VERSION 5.8 ;
BUSBITCHARS "[]" ;
DIVIDERCHAR "/" ;
UNITS
    DATABASE MICRONS 1000 ;
END UNITS

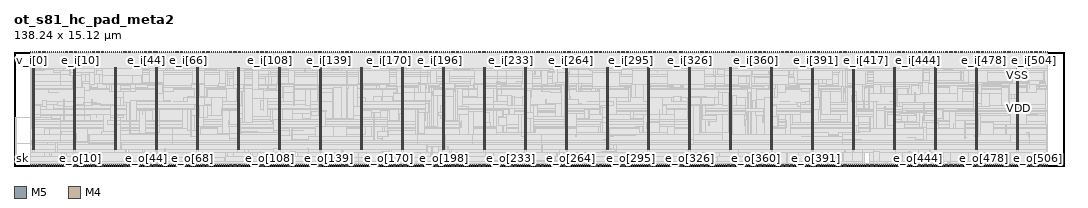
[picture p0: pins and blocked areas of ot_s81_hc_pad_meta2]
MACRO ot_s81_hc_pad_meta2
  FOREIGN ot_s81_hc_pad_meta2 0 0 ;
  CLASS BLOCK ;
  SIZE 138.24 BY 15.12 ;
  PIN e_i[0]
    DIRECTION INPUT ;
    USE SIGNAL ;
    PORT
      LAYER M5 ;
        RECT  6.192 14.928 6.216 15.12 ;
    END
  END e_i[0]
  PIN e_i[100]
    DIRECTION INPUT ;
    USE SIGNAL ;
    PORT
      LAYER M5 ;
        RECT  31.632 14.928 31.656 15.12 ;
    END
  END e_i[100]
  PIN e_i[101]
    DIRECTION INPUT ;
    USE SIGNAL ;
    PORT
      LAYER M5 ;
        RECT  31.872 14.928 31.896 15.12 ;
    END
  END e_i[101]
  PIN e_i[102]
    DIRECTION INPUT ;
    USE SIGNAL ;
    PORT
      LAYER M5 ;
        RECT  32.112 14.928 32.136 15.12 ;
    END
  END e_i[102]
  PIN e_i[103]
    DIRECTION INPUT ;
    USE SIGNAL ;
    PORT
      LAYER M5 ;
        RECT  32.4 14.928 32.424 15.12 ;
    END
  END e_i[103]
  PIN e_i[104]
    DIRECTION INPUT ;
    USE SIGNAL ;
    PORT
      LAYER M5 ;
        RECT  32.64 14.928 32.664 15.12 ;
    END
  END e_i[104]
  PIN e_i[105]
    DIRECTION INPUT ;
    USE SIGNAL ;
    PORT
      LAYER M5 ;
        RECT  32.88 14.928 32.904 15.12 ;
    END
  END e_i[105]
  PIN e_i[106]
    DIRECTION INPUT ;
    USE SIGNAL ;
    PORT
      LAYER M5 ;
        RECT  33.168 14.928 33.192 15.12 ;
    END
  END e_i[106]
  PIN e_i[107]
    DIRECTION INPUT ;
    USE SIGNAL ;
    PORT
      LAYER M5 ;
        RECT  33.408 14.928 33.432 15.12 ;
    END
  END e_i[107]
  PIN e_i[108]
    DIRECTION INPUT ;
    USE SIGNAL ;
    PORT
      LAYER M5 ;
        RECT  33.648 14.928 33.672 15.12 ;
    END
  END e_i[108]
  PIN e_i[109]
    DIRECTION INPUT ;
    USE SIGNAL ;
    PORT
      LAYER M5 ;
        RECT  33.936 14.928 33.96 15.12 ;
    END
  END e_i[109]
  PIN e_i[10]
    DIRECTION INPUT ;
    USE SIGNAL ;
    PORT
      LAYER M5 ;
        RECT  8.736 14.928 8.76 15.12 ;
    END
  END e_i[10]
  PIN e_i[110]
    DIRECTION INPUT ;
    USE SIGNAL ;
    PORT
      LAYER M5 ;
        RECT  34.176 14.928 34.2 15.12 ;
    END
  END e_i[110]
  PIN e_i[111]
    DIRECTION INPUT ;
    USE SIGNAL ;
    PORT
      LAYER M5 ;
        RECT  34.416 14.928 34.44 15.12 ;
    END
  END e_i[111]
  PIN e_i[112]
    DIRECTION INPUT ;
    USE SIGNAL ;
    PORT
      LAYER M5 ;
        RECT  34.656 14.928 34.68 15.12 ;
    END
  END e_i[112]
  PIN e_i[113]
    DIRECTION INPUT ;
    USE SIGNAL ;
    PORT
      LAYER M5 ;
        RECT  34.944 14.928 34.968 15.12 ;
    END
  END e_i[113]
  PIN e_i[114]
    DIRECTION INPUT ;
    USE SIGNAL ;
    PORT
      LAYER M5 ;
        RECT  35.184 14.928 35.208 15.12 ;
    END
  END e_i[114]
  PIN e_i[115]
    DIRECTION INPUT ;
    USE SIGNAL ;
    PORT
      LAYER M5 ;
        RECT  35.424 14.928 35.448 15.12 ;
    END
  END e_i[115]
  PIN e_i[116]
    DIRECTION INPUT ;
    USE SIGNAL ;
    PORT
      LAYER M5 ;
        RECT  35.712 14.928 35.736 15.12 ;
    END
  END e_i[116]
  PIN e_i[117]
    DIRECTION INPUT ;
    USE SIGNAL ;
    PORT
      LAYER M5 ;
        RECT  35.952 14.928 35.976 15.12 ;
    END
  END e_i[117]
  PIN e_i[118]
    DIRECTION INPUT ;
    USE SIGNAL ;
    PORT
      LAYER M5 ;
        RECT  36.192 14.928 36.216 15.12 ;
    END
  END e_i[118]
  PIN e_i[119]
    DIRECTION INPUT ;
    USE SIGNAL ;
    PORT
      LAYER M5 ;
        RECT  36.432 14.928 36.456 15.12 ;
    END
  END e_i[119]
  PIN e_i[11]
    DIRECTION INPUT ;
    USE SIGNAL ;
    PORT
      LAYER M5 ;
        RECT  9.024 14.928 9.048 15.12 ;
    END
  END e_i[11]
  PIN e_i[120]
    DIRECTION INPUT ;
    USE SIGNAL ;
    PORT
      LAYER M5 ;
        RECT  36.72 14.928 36.744 15.12 ;
    END
  END e_i[120]
  PIN e_i[121]
    DIRECTION INPUT ;
    USE SIGNAL ;
    PORT
      LAYER M5 ;
        RECT  36.96 14.928 36.984 15.12 ;
    END
  END e_i[121]
  PIN e_i[122]
    DIRECTION INPUT ;
    USE SIGNAL ;
    PORT
      LAYER M5 ;
        RECT  37.2 14.928 37.224 15.12 ;
    END
  END e_i[122]
  PIN e_i[123]
    DIRECTION INPUT ;
    USE SIGNAL ;
    PORT
      LAYER M5 ;
        RECT  37.488 14.928 37.512 15.12 ;
    END
  END e_i[123]
  PIN e_i[124]
    DIRECTION INPUT ;
    USE SIGNAL ;
    PORT
      LAYER M5 ;
        RECT  37.728 14.928 37.752 15.12 ;
    END
  END e_i[124]
  PIN e_i[125]
    DIRECTION INPUT ;
    USE SIGNAL ;
    PORT
      LAYER M5 ;
        RECT  37.968 14.928 37.992 15.12 ;
    END
  END e_i[125]
  PIN e_i[126]
    DIRECTION INPUT ;
    USE SIGNAL ;
    PORT
      LAYER M5 ;
        RECT  38.256 14.928 38.28 15.12 ;
    END
  END e_i[126]
  PIN e_i[127]
    DIRECTION INPUT ;
    USE SIGNAL ;
    PORT
      LAYER M5 ;
        RECT  38.496 14.928 38.52 15.12 ;
    END
  END e_i[127]
  PIN e_i[128]
    DIRECTION INPUT ;
    USE SIGNAL ;
    PORT
      LAYER M5 ;
        RECT  38.736 14.928 38.76 15.12 ;
    END
  END e_i[128]
  PIN e_i[129]
    DIRECTION INPUT ;
    USE SIGNAL ;
    PORT
      LAYER M5 ;
        RECT  38.976 14.928 39 15.12 ;
    END
  END e_i[129]
  PIN e_i[12]
    DIRECTION INPUT ;
    USE SIGNAL ;
    PORT
      LAYER M5 ;
        RECT  9.264 14.928 9.288 15.12 ;
    END
  END e_i[12]
  PIN e_i[130]
    DIRECTION INPUT ;
    USE SIGNAL ;
    PORT
      LAYER M5 ;
        RECT  39.264 14.928 39.288 15.12 ;
    END
  END e_i[130]
  PIN e_i[131]
    DIRECTION INPUT ;
    USE SIGNAL ;
    PORT
      LAYER M5 ;
        RECT  39.504 14.928 39.528 15.12 ;
    END
  END e_i[131]
  PIN e_i[132]
    DIRECTION INPUT ;
    USE SIGNAL ;
    PORT
      LAYER M5 ;
        RECT  39.744 14.928 39.768 15.12 ;
    END
  END e_i[132]
  PIN e_i[133]
    DIRECTION INPUT ;
    USE SIGNAL ;
    PORT
      LAYER M5 ;
        RECT  40.032 14.928 40.056 15.12 ;
    END
  END e_i[133]
  PIN e_i[134]
    DIRECTION INPUT ;
    USE SIGNAL ;
    PORT
      LAYER M5 ;
        RECT  40.272 14.928 40.296 15.12 ;
    END
  END e_i[134]
  PIN e_i[135]
    DIRECTION INPUT ;
    USE SIGNAL ;
    PORT
      LAYER M5 ;
        RECT  40.512 14.928 40.536 15.12 ;
    END
  END e_i[135]
  PIN e_i[136]
    DIRECTION INPUT ;
    USE SIGNAL ;
    PORT
      LAYER M5 ;
        RECT  40.752 14.928 40.776 15.12 ;
    END
  END e_i[136]
  PIN e_i[137]
    DIRECTION INPUT ;
    USE SIGNAL ;
    PORT
      LAYER M5 ;
        RECT  41.04 14.928 41.064 15.12 ;
    END
  END e_i[137]
  PIN e_i[138]
    DIRECTION INPUT ;
    USE SIGNAL ;
    PORT
      LAYER M5 ;
        RECT  41.28 14.928 41.304 15.12 ;
    END
  END e_i[138]
  PIN e_i[139]
    DIRECTION INPUT ;
    USE SIGNAL ;
    PORT
      LAYER M5 ;
        RECT  41.52 14.928 41.544 15.12 ;
    END
  END e_i[139]
  PIN e_i[13]
    DIRECTION INPUT ;
    USE SIGNAL ;
    PORT
      LAYER M5 ;
        RECT  9.504 14.928 9.528 15.12 ;
    END
  END e_i[13]
  PIN e_i[140]
    DIRECTION INPUT ;
    USE SIGNAL ;
    PORT
      LAYER M5 ;
        RECT  41.808 14.928 41.832 15.12 ;
    END
  END e_i[140]
  PIN e_i[141]
    DIRECTION INPUT ;
    USE SIGNAL ;
    PORT
      LAYER M5 ;
        RECT  42.048 14.928 42.072 15.12 ;
    END
  END e_i[141]
  PIN e_i[142]
    DIRECTION INPUT ;
    USE SIGNAL ;
    PORT
      LAYER M5 ;
        RECT  42.288 14.928 42.312 15.12 ;
    END
  END e_i[142]
  PIN e_i[143]
    DIRECTION INPUT ;
    USE SIGNAL ;
    PORT
      LAYER M5 ;
        RECT  42.576 14.928 42.6 15.12 ;
    END
  END e_i[143]
  PIN e_i[144]
    DIRECTION INPUT ;
    USE SIGNAL ;
    PORT
      LAYER M5 ;
        RECT  42.816 14.928 42.84 15.12 ;
    END
  END e_i[144]
  PIN e_i[145]
    DIRECTION INPUT ;
    USE SIGNAL ;
    PORT
      LAYER M5 ;
        RECT  43.056 14.928 43.08 15.12 ;
    END
  END e_i[145]
  PIN e_i[146]
    DIRECTION INPUT ;
    USE SIGNAL ;
    PORT
      LAYER M5 ;
        RECT  43.296 14.928 43.32 15.12 ;
    END
  END e_i[146]
  PIN e_i[147]
    DIRECTION INPUT ;
    USE SIGNAL ;
    PORT
      LAYER M5 ;
        RECT  43.584 14.928 43.608 15.12 ;
    END
  END e_i[147]
  PIN e_i[148]
    DIRECTION INPUT ;
    USE SIGNAL ;
    PORT
      LAYER M5 ;
        RECT  43.824 14.928 43.848 15.12 ;
    END
  END e_i[148]
  PIN e_i[149]
    DIRECTION INPUT ;
    USE SIGNAL ;
    PORT
      LAYER M5 ;
        RECT  44.064 14.928 44.088 15.12 ;
    END
  END e_i[149]
  PIN e_i[14]
    DIRECTION INPUT ;
    USE SIGNAL ;
    PORT
      LAYER M5 ;
        RECT  9.792 14.928 9.816 15.12 ;
    END
  END e_i[14]
  PIN e_i[150]
    DIRECTION INPUT ;
    USE SIGNAL ;
    PORT
      LAYER M5 ;
        RECT  44.352 14.928 44.376 15.12 ;
    END
  END e_i[150]
  PIN e_i[151]
    DIRECTION INPUT ;
    USE SIGNAL ;
    PORT
      LAYER M5 ;
        RECT  44.592 14.928 44.616 15.12 ;
    END
  END e_i[151]
  PIN e_i[152]
    DIRECTION INPUT ;
    USE SIGNAL ;
    PORT
      LAYER M5 ;
        RECT  44.832 14.928 44.856 15.12 ;
    END
  END e_i[152]
  PIN e_i[153]
    DIRECTION INPUT ;
    USE SIGNAL ;
    PORT
      LAYER M5 ;
        RECT  45.072 14.928 45.096 15.12 ;
    END
  END e_i[153]
  PIN e_i[154]
    DIRECTION INPUT ;
    USE SIGNAL ;
    PORT
      LAYER M5 ;
        RECT  45.36 14.928 45.384 15.12 ;
    END
  END e_i[154]
  PIN e_i[155]
    DIRECTION INPUT ;
    USE SIGNAL ;
    PORT
      LAYER M5 ;
        RECT  45.6 14.928 45.624 15.12 ;
    END
  END e_i[155]
  PIN e_i[156]
    DIRECTION INPUT ;
    USE SIGNAL ;
    PORT
      LAYER M5 ;
        RECT  45.84 14.928 45.864 15.12 ;
    END
  END e_i[156]
  PIN e_i[157]
    DIRECTION INPUT ;
    USE SIGNAL ;
    PORT
      LAYER M5 ;
        RECT  46.128 14.928 46.152 15.12 ;
    END
  END e_i[157]
  PIN e_i[158]
    DIRECTION INPUT ;
    USE SIGNAL ;
    PORT
      LAYER M5 ;
        RECT  46.368 14.928 46.392 15.12 ;
    END
  END e_i[158]
  PIN e_i[159]
    DIRECTION INPUT ;
    USE SIGNAL ;
    PORT
      LAYER M5 ;
        RECT  46.608 14.928 46.632 15.12 ;
    END
  END e_i[159]
  PIN e_i[15]
    DIRECTION INPUT ;
    USE SIGNAL ;
    PORT
      LAYER M5 ;
        RECT  10.032 14.928 10.056 15.12 ;
    END
  END e_i[15]
  PIN e_i[160]
    DIRECTION INPUT ;
    USE SIGNAL ;
    PORT
      LAYER M5 ;
        RECT  46.896 14.928 46.92 15.12 ;
    END
  END e_i[160]
  PIN e_i[161]
    DIRECTION INPUT ;
    USE SIGNAL ;
    PORT
      LAYER M5 ;
        RECT  47.136 14.928 47.16 15.12 ;
    END
  END e_i[161]
  PIN e_i[162]
    DIRECTION INPUT ;
    USE SIGNAL ;
    PORT
      LAYER M5 ;
        RECT  47.376 14.928 47.4 15.12 ;
    END
  END e_i[162]
  PIN e_i[163]
    DIRECTION INPUT ;
    USE SIGNAL ;
    PORT
      LAYER M5 ;
        RECT  47.616 14.928 47.64 15.12 ;
    END
  END e_i[163]
  PIN e_i[164]
    DIRECTION INPUT ;
    USE SIGNAL ;
    PORT
      LAYER M5 ;
        RECT  47.904 14.928 47.928 15.12 ;
    END
  END e_i[164]
  PIN e_i[165]
    DIRECTION INPUT ;
    USE SIGNAL ;
    PORT
      LAYER M5 ;
        RECT  48.144 14.928 48.168 15.12 ;
    END
  END e_i[165]
  PIN e_i[166]
    DIRECTION INPUT ;
    USE SIGNAL ;
    PORT
      LAYER M5 ;
        RECT  48.384 14.928 48.408 15.12 ;
    END
  END e_i[166]
  PIN e_i[167]
    DIRECTION INPUT ;
    USE SIGNAL ;
    PORT
      LAYER M5 ;
        RECT  48.672 14.928 48.696 15.12 ;
    END
  END e_i[167]
  PIN e_i[168]
    DIRECTION INPUT ;
    USE SIGNAL ;
    PORT
      LAYER M5 ;
        RECT  48.912 14.928 48.936 15.12 ;
    END
  END e_i[168]
  PIN e_i[169]
    DIRECTION INPUT ;
    USE SIGNAL ;
    PORT
      LAYER M5 ;
        RECT  49.152 14.928 49.176 15.12 ;
    END
  END e_i[169]
  PIN e_i[16]
    DIRECTION INPUT ;
    USE SIGNAL ;
    PORT
      LAYER M5 ;
        RECT  10.272 14.928 10.296 15.12 ;
    END
  END e_i[16]
  PIN e_i[170]
    DIRECTION INPUT ;
    USE SIGNAL ;
    PORT
      LAYER M5 ;
        RECT  49.392 14.928 49.416 15.12 ;
    END
  END e_i[170]
  PIN e_i[171]
    DIRECTION INPUT ;
    USE SIGNAL ;
    PORT
      LAYER M5 ;
        RECT  49.68 14.928 49.704 15.12 ;
    END
  END e_i[171]
  PIN e_i[172]
    DIRECTION INPUT ;
    USE SIGNAL ;
    PORT
      LAYER M5 ;
        RECT  49.92 14.928 49.944 15.12 ;
    END
  END e_i[172]
  PIN e_i[173]
    DIRECTION INPUT ;
    USE SIGNAL ;
    PORT
      LAYER M5 ;
        RECT  50.16 14.928 50.184 15.12 ;
    END
  END e_i[173]
  PIN e_i[174]
    DIRECTION INPUT ;
    USE SIGNAL ;
    PORT
      LAYER M5 ;
        RECT  50.448 14.928 50.472 15.12 ;
    END
  END e_i[174]
  PIN e_i[175]
    DIRECTION INPUT ;
    USE SIGNAL ;
    PORT
      LAYER M5 ;
        RECT  50.688 14.928 50.712 15.12 ;
    END
  END e_i[175]
  PIN e_i[176]
    DIRECTION INPUT ;
    USE SIGNAL ;
    PORT
      LAYER M5 ;
        RECT  50.928 14.928 50.952 15.12 ;
    END
  END e_i[176]
  PIN e_i[177]
    DIRECTION INPUT ;
    USE SIGNAL ;
    PORT
      LAYER M5 ;
        RECT  51.216 14.928 51.24 15.12 ;
    END
  END e_i[177]
  PIN e_i[178]
    DIRECTION INPUT ;
    USE SIGNAL ;
    PORT
      LAYER M5 ;
        RECT  51.456 14.928 51.48 15.12 ;
    END
  END e_i[178]
  PIN e_i[179]
    DIRECTION INPUT ;
    USE SIGNAL ;
    PORT
      LAYER M5 ;
        RECT  51.696 14.928 51.72 15.12 ;
    END
  END e_i[179]
  PIN e_i[17]
    DIRECTION INPUT ;
    USE SIGNAL ;
    PORT
      LAYER M5 ;
        RECT  10.512 14.928 10.536 15.12 ;
    END
  END e_i[17]
  PIN e_i[180]
    DIRECTION INPUT ;
    USE SIGNAL ;
    PORT
      LAYER M5 ;
        RECT  51.936 14.928 51.96 15.12 ;
    END
  END e_i[180]
  PIN e_i[181]
    DIRECTION INPUT ;
    USE SIGNAL ;
    PORT
      LAYER M5 ;
        RECT  52.224 14.928 52.248 15.12 ;
    END
  END e_i[181]
  PIN e_i[182]
    DIRECTION INPUT ;
    USE SIGNAL ;
    PORT
      LAYER M5 ;
        RECT  52.464 14.928 52.488 15.12 ;
    END
  END e_i[182]
  PIN e_i[183]
    DIRECTION INPUT ;
    USE SIGNAL ;
    PORT
      LAYER M5 ;
        RECT  52.704 14.928 52.728 15.12 ;
    END
  END e_i[183]
  PIN e_i[184]
    DIRECTION INPUT ;
    USE SIGNAL ;
    PORT
      LAYER M5 ;
        RECT  52.992 14.928 53.016 15.12 ;
    END
  END e_i[184]
  PIN e_i[185]
    DIRECTION INPUT ;
    USE SIGNAL ;
    PORT
      LAYER M5 ;
        RECT  53.232 14.928 53.256 15.12 ;
    END
  END e_i[185]
  PIN e_i[186]
    DIRECTION INPUT ;
    USE SIGNAL ;
    PORT
      LAYER M5 ;
        RECT  53.472 14.928 53.496 15.12 ;
    END
  END e_i[186]
  PIN e_i[187]
    DIRECTION INPUT ;
    USE SIGNAL ;
    PORT
      LAYER M5 ;
        RECT  53.712 14.928 53.736 15.12 ;
    END
  END e_i[187]
  PIN e_i[188]
    DIRECTION INPUT ;
    USE SIGNAL ;
    PORT
      LAYER M5 ;
        RECT  54 14.928 54.024 15.12 ;
    END
  END e_i[188]
  PIN e_i[189]
    DIRECTION INPUT ;
    USE SIGNAL ;
    PORT
      LAYER M5 ;
        RECT  54.24 14.928 54.264 15.12 ;
    END
  END e_i[189]
  PIN e_i[18]
    DIRECTION INPUT ;
    USE SIGNAL ;
    PORT
      LAYER M5 ;
        RECT  10.8 14.928 10.824 15.12 ;
    END
  END e_i[18]
  PIN e_i[190]
    DIRECTION INPUT ;
    USE SIGNAL ;
    PORT
      LAYER M5 ;
        RECT  54.48 14.928 54.504 15.12 ;
    END
  END e_i[190]
  PIN e_i[191]
    DIRECTION INPUT ;
    USE SIGNAL ;
    PORT
      LAYER M5 ;
        RECT  54.768 14.928 54.792 15.12 ;
    END
  END e_i[191]
  PIN e_i[192]
    DIRECTION INPUT ;
    USE SIGNAL ;
    PORT
      LAYER M5 ;
        RECT  55.008 14.928 55.032 15.12 ;
    END
  END e_i[192]
  PIN e_i[193]
    DIRECTION INPUT ;
    USE SIGNAL ;
    PORT
      LAYER M5 ;
        RECT  55.248 14.928 55.272 15.12 ;
    END
  END e_i[193]
  PIN e_i[194]
    DIRECTION INPUT ;
    USE SIGNAL ;
    PORT
      LAYER M5 ;
        RECT  55.536 14.928 55.56 15.12 ;
    END
  END e_i[194]
  PIN e_i[195]
    DIRECTION INPUT ;
    USE SIGNAL ;
    PORT
      LAYER M5 ;
        RECT  55.776 14.928 55.8 15.12 ;
    END
  END e_i[195]
  PIN e_i[196]
    DIRECTION INPUT ;
    USE SIGNAL ;
    PORT
      LAYER M5 ;
        RECT  56.016 14.928 56.04 15.12 ;
    END
  END e_i[196]
  PIN e_i[197]
    DIRECTION INPUT ;
    USE SIGNAL ;
    PORT
      LAYER M5 ;
        RECT  56.256 14.928 56.28 15.12 ;
    END
  END e_i[197]
  PIN e_i[198]
    DIRECTION INPUT ;
    USE SIGNAL ;
    PORT
      LAYER M5 ;
        RECT  56.544 14.928 56.568 15.12 ;
    END
  END e_i[198]
  PIN e_i[199]
    DIRECTION INPUT ;
    USE SIGNAL ;
    PORT
      LAYER M5 ;
        RECT  56.784 14.928 56.808 15.12 ;
    END
  END e_i[199]
  PIN e_i[19]
    DIRECTION INPUT ;
    USE SIGNAL ;
    PORT
      LAYER M5 ;
        RECT  11.04 14.928 11.064 15.12 ;
    END
  END e_i[19]
  PIN e_i[1]
    DIRECTION INPUT ;
    USE SIGNAL ;
    PORT
      LAYER M5 ;
        RECT  6.48 14.928 6.504 15.12 ;
    END
  END e_i[1]
  PIN e_i[200]
    DIRECTION INPUT ;
    USE SIGNAL ;
    PORT
      LAYER M5 ;
        RECT  57.024 14.928 57.048 15.12 ;
    END
  END e_i[200]
  PIN e_i[201]
    DIRECTION INPUT ;
    USE SIGNAL ;
    PORT
      LAYER M5 ;
        RECT  57.312 14.928 57.336 15.12 ;
    END
  END e_i[201]
  PIN e_i[202]
    DIRECTION INPUT ;
    USE SIGNAL ;
    PORT
      LAYER M5 ;
        RECT  57.552 14.928 57.576 15.12 ;
    END
  END e_i[202]
  PIN e_i[203]
    DIRECTION INPUT ;
    USE SIGNAL ;
    PORT
      LAYER M5 ;
        RECT  57.792 14.928 57.816 15.12 ;
    END
  END e_i[203]
  PIN e_i[204]
    DIRECTION INPUT ;
    USE SIGNAL ;
    PORT
      LAYER M5 ;
        RECT  58.032 14.928 58.056 15.12 ;
    END
  END e_i[204]
  PIN e_i[205]
    DIRECTION INPUT ;
    USE SIGNAL ;
    PORT
      LAYER M5 ;
        RECT  58.32 14.928 58.344 15.12 ;
    END
  END e_i[205]
  PIN e_i[206]
    DIRECTION INPUT ;
    USE SIGNAL ;
    PORT
      LAYER M5 ;
        RECT  58.56 14.928 58.584 15.12 ;
    END
  END e_i[206]
  PIN e_i[207]
    DIRECTION INPUT ;
    USE SIGNAL ;
    PORT
      LAYER M5 ;
        RECT  58.8 14.928 58.824 15.12 ;
    END
  END e_i[207]
  PIN e_i[208]
    DIRECTION INPUT ;
    USE SIGNAL ;
    PORT
      LAYER M5 ;
        RECT  59.088 14.928 59.112 15.12 ;
    END
  END e_i[208]
  PIN e_i[209]
    DIRECTION INPUT ;
    USE SIGNAL ;
    PORT
      LAYER M5 ;
        RECT  59.328 14.928 59.352 15.12 ;
    END
  END e_i[209]
  PIN e_i[20]
    DIRECTION INPUT ;
    USE SIGNAL ;
    PORT
      LAYER M5 ;
        RECT  11.28 14.928 11.304 15.12 ;
    END
  END e_i[20]
  PIN e_i[210]
    DIRECTION INPUT ;
    USE SIGNAL ;
    PORT
      LAYER M5 ;
        RECT  59.568 14.928 59.592 15.12 ;
    END
  END e_i[210]
  PIN e_i[211]
    DIRECTION INPUT ;
    USE SIGNAL ;
    PORT
      LAYER M5 ;
        RECT  59.856 14.928 59.88 15.12 ;
    END
  END e_i[211]
  PIN e_i[212]
    DIRECTION INPUT ;
    USE SIGNAL ;
    PORT
      LAYER M5 ;
        RECT  60.096 14.928 60.12 15.12 ;
    END
  END e_i[212]
  PIN e_i[213]
    DIRECTION INPUT ;
    USE SIGNAL ;
    PORT
      LAYER M5 ;
        RECT  60.336 14.928 60.36 15.12 ;
    END
  END e_i[213]
  PIN e_i[214]
    DIRECTION INPUT ;
    USE SIGNAL ;
    PORT
      LAYER M5 ;
        RECT  60.576 14.928 60.6 15.12 ;
    END
  END e_i[214]
  PIN e_i[215]
    DIRECTION INPUT ;
    USE SIGNAL ;
    PORT
      LAYER M5 ;
        RECT  60.864 14.928 60.888 15.12 ;
    END
  END e_i[215]
  PIN e_i[216]
    DIRECTION INPUT ;
    USE SIGNAL ;
    PORT
      LAYER M5 ;
        RECT  61.104 14.928 61.128 15.12 ;
    END
  END e_i[216]
  PIN e_i[217]
    DIRECTION INPUT ;
    USE SIGNAL ;
    PORT
      LAYER M5 ;
        RECT  61.344 14.928 61.368 15.12 ;
    END
  END e_i[217]
  PIN e_i[218]
    DIRECTION INPUT ;
    USE SIGNAL ;
    PORT
      LAYER M5 ;
        RECT  61.632 14.928 61.656 15.12 ;
    END
  END e_i[218]
  PIN e_i[219]
    DIRECTION INPUT ;
    USE SIGNAL ;
    PORT
      LAYER M5 ;
        RECT  61.872 14.928 61.896 15.12 ;
    END
  END e_i[219]
  PIN e_i[21]
    DIRECTION INPUT ;
    USE SIGNAL ;
    PORT
      LAYER M5 ;
        RECT  11.568 14.928 11.592 15.12 ;
    END
  END e_i[21]
  PIN e_i[220]
    DIRECTION INPUT ;
    USE SIGNAL ;
    PORT
      LAYER M5 ;
        RECT  62.112 14.928 62.136 15.12 ;
    END
  END e_i[220]
  PIN e_i[221]
    DIRECTION INPUT ;
    USE SIGNAL ;
    PORT
      LAYER M5 ;
        RECT  62.352 14.928 62.376 15.12 ;
    END
  END e_i[221]
  PIN e_i[222]
    DIRECTION INPUT ;
    USE SIGNAL ;
    PORT
      LAYER M5 ;
        RECT  62.64 14.928 62.664 15.12 ;
    END
  END e_i[222]
  PIN e_i[223]
    DIRECTION INPUT ;
    USE SIGNAL ;
    PORT
      LAYER M5 ;
        RECT  62.88 14.928 62.904 15.12 ;
    END
  END e_i[223]
  PIN e_i[224]
    DIRECTION INPUT ;
    USE SIGNAL ;
    PORT
      LAYER M5 ;
        RECT  63.12 14.928 63.144 15.12 ;
    END
  END e_i[224]
  PIN e_i[225]
    DIRECTION INPUT ;
    USE SIGNAL ;
    PORT
      LAYER M5 ;
        RECT  63.408 14.928 63.432 15.12 ;
    END
  END e_i[225]
  PIN e_i[226]
    DIRECTION INPUT ;
    USE SIGNAL ;
    PORT
      LAYER M5 ;
        RECT  63.648 14.928 63.672 15.12 ;
    END
  END e_i[226]
  PIN e_i[227]
    DIRECTION INPUT ;
    USE SIGNAL ;
    PORT
      LAYER M5 ;
        RECT  63.888 14.928 63.912 15.12 ;
    END
  END e_i[227]
  PIN e_i[228]
    DIRECTION INPUT ;
    USE SIGNAL ;
    PORT
      LAYER M5 ;
        RECT  64.176 14.928 64.2 15.12 ;
    END
  END e_i[228]
  PIN e_i[229]
    DIRECTION INPUT ;
    USE SIGNAL ;
    PORT
      LAYER M5 ;
        RECT  64.416 14.928 64.44 15.12 ;
    END
  END e_i[229]
  PIN e_i[22]
    DIRECTION INPUT ;
    USE SIGNAL ;
    PORT
      LAYER M5 ;
        RECT  11.808 14.928 11.832 15.12 ;
    END
  END e_i[22]
  PIN e_i[230]
    DIRECTION INPUT ;
    USE SIGNAL ;
    PORT
      LAYER M5 ;
        RECT  64.656 14.928 64.68 15.12 ;
    END
  END e_i[230]
  PIN e_i[231]
    DIRECTION INPUT ;
    USE SIGNAL ;
    PORT
      LAYER M5 ;
        RECT  64.896 14.928 64.92 15.12 ;
    END
  END e_i[231]
  PIN e_i[232]
    DIRECTION INPUT ;
    USE SIGNAL ;
    PORT
      LAYER M5 ;
        RECT  65.184 14.928 65.208 15.12 ;
    END
  END e_i[232]
  PIN e_i[233]
    DIRECTION INPUT ;
    USE SIGNAL ;
    PORT
      LAYER M5 ;
        RECT  65.424 14.928 65.448 15.12 ;
    END
  END e_i[233]
  PIN e_i[234]
    DIRECTION INPUT ;
    USE SIGNAL ;
    PORT
      LAYER M5 ;
        RECT  65.664 14.928 65.688 15.12 ;
    END
  END e_i[234]
  PIN e_i[235]
    DIRECTION INPUT ;
    USE SIGNAL ;
    PORT
      LAYER M5 ;
        RECT  65.952 14.928 65.976 15.12 ;
    END
  END e_i[235]
  PIN e_i[236]
    DIRECTION INPUT ;
    USE SIGNAL ;
    PORT
      LAYER M5 ;
        RECT  66.192 14.928 66.216 15.12 ;
    END
  END e_i[236]
  PIN e_i[237]
    DIRECTION INPUT ;
    USE SIGNAL ;
    PORT
      LAYER M5 ;
        RECT  66.432 14.928 66.456 15.12 ;
    END
  END e_i[237]
  PIN e_i[238]
    DIRECTION INPUT ;
    USE SIGNAL ;
    PORT
      LAYER M5 ;
        RECT  66.672 14.928 66.696 15.12 ;
    END
  END e_i[238]
  PIN e_i[239]
    DIRECTION INPUT ;
    USE SIGNAL ;
    PORT
      LAYER M5 ;
        RECT  66.96 14.928 66.984 15.12 ;
    END
  END e_i[239]
  PIN e_i[23]
    DIRECTION INPUT ;
    USE SIGNAL ;
    PORT
      LAYER M5 ;
        RECT  12.048 14.928 12.072 15.12 ;
    END
  END e_i[23]
  PIN e_i[240]
    DIRECTION INPUT ;
    USE SIGNAL ;
    PORT
      LAYER M5 ;
        RECT  67.2 14.928 67.224 15.12 ;
    END
  END e_i[240]
  PIN e_i[241]
    DIRECTION INPUT ;
    USE SIGNAL ;
    PORT
      LAYER M5 ;
        RECT  67.44 14.928 67.464 15.12 ;
    END
  END e_i[241]
  PIN e_i[242]
    DIRECTION INPUT ;
    USE SIGNAL ;
    PORT
      LAYER M5 ;
        RECT  67.728 14.928 67.752 15.12 ;
    END
  END e_i[242]
  PIN e_i[243]
    DIRECTION INPUT ;
    USE SIGNAL ;
    PORT
      LAYER M5 ;
        RECT  67.968 14.928 67.992 15.12 ;
    END
  END e_i[243]
  PIN e_i[244]
    DIRECTION INPUT ;
    USE SIGNAL ;
    PORT
      LAYER M5 ;
        RECT  68.208 14.928 68.232 15.12 ;
    END
  END e_i[244]
  PIN e_i[245]
    DIRECTION INPUT ;
    USE SIGNAL ;
    PORT
      LAYER M5 ;
        RECT  68.496 14.928 68.52 15.12 ;
    END
  END e_i[245]
  PIN e_i[246]
    DIRECTION INPUT ;
    USE SIGNAL ;
    PORT
      LAYER M5 ;
        RECT  68.736 14.928 68.76 15.12 ;
    END
  END e_i[246]
  PIN e_i[247]
    DIRECTION INPUT ;
    USE SIGNAL ;
    PORT
      LAYER M5 ;
        RECT  68.976 14.928 69 15.12 ;
    END
  END e_i[247]
  PIN e_i[248]
    DIRECTION INPUT ;
    USE SIGNAL ;
    PORT
      LAYER M5 ;
        RECT  69.216 14.928 69.24 15.12 ;
    END
  END e_i[248]
  PIN e_i[249]
    DIRECTION INPUT ;
    USE SIGNAL ;
    PORT
      LAYER M5 ;
        RECT  69.504 14.928 69.528 15.12 ;
    END
  END e_i[249]
  PIN e_i[24]
    DIRECTION INPUT ;
    USE SIGNAL ;
    PORT
      LAYER M5 ;
        RECT  12.336 14.928 12.36 15.12 ;
    END
  END e_i[24]
  PIN e_i[250]
    DIRECTION INPUT ;
    USE SIGNAL ;
    PORT
      LAYER M5 ;
        RECT  69.744 14.928 69.768 15.12 ;
    END
  END e_i[250]
  PIN e_i[251]
    DIRECTION INPUT ;
    USE SIGNAL ;
    PORT
      LAYER M5 ;
        RECT  69.984 14.928 70.008 15.12 ;
    END
  END e_i[251]
  PIN e_i[252]
    DIRECTION INPUT ;
    USE SIGNAL ;
    PORT
      LAYER M5 ;
        RECT  70.272 14.928 70.296 15.12 ;
    END
  END e_i[252]
  PIN e_i[253]
    DIRECTION INPUT ;
    USE SIGNAL ;
    PORT
      LAYER M5 ;
        RECT  70.512 14.928 70.536 15.12 ;
    END
  END e_i[253]
  PIN e_i[254]
    DIRECTION INPUT ;
    USE SIGNAL ;
    PORT
      LAYER M5 ;
        RECT  70.752 14.928 70.776 15.12 ;
    END
  END e_i[254]
  PIN e_i[255]
    DIRECTION INPUT ;
    USE SIGNAL ;
    PORT
      LAYER M5 ;
        RECT  70.992 14.928 71.016 15.12 ;
    END
  END e_i[255]
  PIN e_i[256]
    DIRECTION INPUT ;
    USE SIGNAL ;
    PORT
      LAYER M5 ;
        RECT  71.28 14.928 71.304 15.12 ;
    END
  END e_i[256]
  PIN e_i[257]
    DIRECTION INPUT ;
    USE SIGNAL ;
    PORT
      LAYER M5 ;
        RECT  71.52 14.928 71.544 15.12 ;
    END
  END e_i[257]
  PIN e_i[258]
    DIRECTION INPUT ;
    USE SIGNAL ;
    PORT
      LAYER M5 ;
        RECT  71.76 14.928 71.784 15.12 ;
    END
  END e_i[258]
  PIN e_i[259]
    DIRECTION INPUT ;
    USE SIGNAL ;
    PORT
      LAYER M5 ;
        RECT  72.048 14.928 72.072 15.12 ;
    END
  END e_i[259]
  PIN e_i[25]
    DIRECTION INPUT ;
    USE SIGNAL ;
    PORT
      LAYER M5 ;
        RECT  12.576 14.928 12.6 15.12 ;
    END
  END e_i[25]
  PIN e_i[260]
    DIRECTION INPUT ;
    USE SIGNAL ;
    PORT
      LAYER M5 ;
        RECT  72.288 14.928 72.312 15.12 ;
    END
  END e_i[260]
  PIN e_i[261]
    DIRECTION INPUT ;
    USE SIGNAL ;
    PORT
      LAYER M5 ;
        RECT  72.528 14.928 72.552 15.12 ;
    END
  END e_i[261]
  PIN e_i[262]
    DIRECTION INPUT ;
    USE SIGNAL ;
    PORT
      LAYER M5 ;
        RECT  72.816 14.928 72.84 15.12 ;
    END
  END e_i[262]
  PIN e_i[263]
    DIRECTION INPUT ;
    USE SIGNAL ;
    PORT
      LAYER M5 ;
        RECT  73.056 14.928 73.08 15.12 ;
    END
  END e_i[263]
  PIN e_i[264]
    DIRECTION INPUT ;
    USE SIGNAL ;
    PORT
      LAYER M5 ;
        RECT  73.296 14.928 73.32 15.12 ;
    END
  END e_i[264]
  PIN e_i[265]
    DIRECTION INPUT ;
    USE SIGNAL ;
    PORT
      LAYER M5 ;
        RECT  73.536 14.928 73.56 15.12 ;
    END
  END e_i[265]
  PIN e_i[266]
    DIRECTION INPUT ;
    USE SIGNAL ;
    PORT
      LAYER M5 ;
        RECT  73.824 14.928 73.848 15.12 ;
    END
  END e_i[266]
  PIN e_i[267]
    DIRECTION INPUT ;
    USE SIGNAL ;
    PORT
      LAYER M5 ;
        RECT  74.064 14.928 74.088 15.12 ;
    END
  END e_i[267]
  PIN e_i[268]
    DIRECTION INPUT ;
    USE SIGNAL ;
    PORT
      LAYER M5 ;
        RECT  74.304 14.928 74.328 15.12 ;
    END
  END e_i[268]
  PIN e_i[269]
    DIRECTION INPUT ;
    USE SIGNAL ;
    PORT
      LAYER M5 ;
        RECT  74.592 14.928 74.616 15.12 ;
    END
  END e_i[269]
  PIN e_i[26]
    DIRECTION INPUT ;
    USE SIGNAL ;
    PORT
      LAYER M5 ;
        RECT  12.816 14.928 12.84 15.12 ;
    END
  END e_i[26]
  PIN e_i[270]
    DIRECTION INPUT ;
    USE SIGNAL ;
    PORT
      LAYER M5 ;
        RECT  74.832 14.928 74.856 15.12 ;
    END
  END e_i[270]
  PIN e_i[271]
    DIRECTION INPUT ;
    USE SIGNAL ;
    PORT
      LAYER M5 ;
        RECT  75.072 14.928 75.096 15.12 ;
    END
  END e_i[271]
  PIN e_i[272]
    DIRECTION INPUT ;
    USE SIGNAL ;
    PORT
      LAYER M5 ;
        RECT  75.312 14.928 75.336 15.12 ;
    END
  END e_i[272]
  PIN e_i[273]
    DIRECTION INPUT ;
    USE SIGNAL ;
    PORT
      LAYER M5 ;
        RECT  75.6 14.928 75.624 15.12 ;
    END
  END e_i[273]
  PIN e_i[274]
    DIRECTION INPUT ;
    USE SIGNAL ;
    PORT
      LAYER M5 ;
        RECT  75.84 14.928 75.864 15.12 ;
    END
  END e_i[274]
  PIN e_i[275]
    DIRECTION INPUT ;
    USE SIGNAL ;
    PORT
      LAYER M5 ;
        RECT  76.08 14.928 76.104 15.12 ;
    END
  END e_i[275]
  PIN e_i[276]
    DIRECTION INPUT ;
    USE SIGNAL ;
    PORT
      LAYER M5 ;
        RECT  76.368 14.928 76.392 15.12 ;
    END
  END e_i[276]
  PIN e_i[277]
    DIRECTION INPUT ;
    USE SIGNAL ;
    PORT
      LAYER M5 ;
        RECT  76.608 14.928 76.632 15.12 ;
    END
  END e_i[277]
  PIN e_i[278]
    DIRECTION INPUT ;
    USE SIGNAL ;
    PORT
      LAYER M5 ;
        RECT  76.848 14.928 76.872 15.12 ;
    END
  END e_i[278]
  PIN e_i[279]
    DIRECTION INPUT ;
    USE SIGNAL ;
    PORT
      LAYER M5 ;
        RECT  77.136 14.928 77.16 15.12 ;
    END
  END e_i[279]
  PIN e_i[27]
    DIRECTION INPUT ;
    USE SIGNAL ;
    PORT
      LAYER M5 ;
        RECT  13.056 14.928 13.08 15.12 ;
    END
  END e_i[27]
  PIN e_i[280]
    DIRECTION INPUT ;
    USE SIGNAL ;
    PORT
      LAYER M5 ;
        RECT  77.376 14.928 77.4 15.12 ;
    END
  END e_i[280]
  PIN e_i[281]
    DIRECTION INPUT ;
    USE SIGNAL ;
    PORT
      LAYER M5 ;
        RECT  77.616 14.928 77.64 15.12 ;
    END
  END e_i[281]
  PIN e_i[282]
    DIRECTION INPUT ;
    USE SIGNAL ;
    PORT
      LAYER M5 ;
        RECT  77.856 14.928 77.88 15.12 ;
    END
  END e_i[282]
  PIN e_i[283]
    DIRECTION INPUT ;
    USE SIGNAL ;
    PORT
      LAYER M5 ;
        RECT  78.144 14.928 78.168 15.12 ;
    END
  END e_i[283]
  PIN e_i[284]
    DIRECTION INPUT ;
    USE SIGNAL ;
    PORT
      LAYER M5 ;
        RECT  78.384 14.928 78.408 15.12 ;
    END
  END e_i[284]
  PIN e_i[285]
    DIRECTION INPUT ;
    USE SIGNAL ;
    PORT
      LAYER M5 ;
        RECT  78.624 14.928 78.648 15.12 ;
    END
  END e_i[285]
  PIN e_i[286]
    DIRECTION INPUT ;
    USE SIGNAL ;
    PORT
      LAYER M5 ;
        RECT  78.912 14.928 78.936 15.12 ;
    END
  END e_i[286]
  PIN e_i[287]
    DIRECTION INPUT ;
    USE SIGNAL ;
    PORT
      LAYER M5 ;
        RECT  79.152 14.928 79.176 15.12 ;
    END
  END e_i[287]
  PIN e_i[288]
    DIRECTION INPUT ;
    USE SIGNAL ;
    PORT
      LAYER M5 ;
        RECT  79.392 14.928 79.416 15.12 ;
    END
  END e_i[288]
  PIN e_i[289]
    DIRECTION INPUT ;
    USE SIGNAL ;
    PORT
      LAYER M5 ;
        RECT  79.632 14.928 79.656 15.12 ;
    END
  END e_i[289]
  PIN e_i[28]
    DIRECTION INPUT ;
    USE SIGNAL ;
    PORT
      LAYER M5 ;
        RECT  13.344 14.928 13.368 15.12 ;
    END
  END e_i[28]
  PIN e_i[290]
    DIRECTION INPUT ;
    USE SIGNAL ;
    PORT
      LAYER M5 ;
        RECT  79.92 14.928 79.944 15.12 ;
    END
  END e_i[290]
  PIN e_i[291]
    DIRECTION INPUT ;
    USE SIGNAL ;
    PORT
      LAYER M5 ;
        RECT  80.16 14.928 80.184 15.12 ;
    END
  END e_i[291]
  PIN e_i[292]
    DIRECTION INPUT ;
    USE SIGNAL ;
    PORT
      LAYER M5 ;
        RECT  80.4 14.928 80.424 15.12 ;
    END
  END e_i[292]
  PIN e_i[293]
    DIRECTION INPUT ;
    USE SIGNAL ;
    PORT
      LAYER M5 ;
        RECT  80.688 14.928 80.712 15.12 ;
    END
  END e_i[293]
  PIN e_i[294]
    DIRECTION INPUT ;
    USE SIGNAL ;
    PORT
      LAYER M5 ;
        RECT  80.928 14.928 80.952 15.12 ;
    END
  END e_i[294]
  PIN e_i[295]
    DIRECTION INPUT ;
    USE SIGNAL ;
    PORT
      LAYER M5 ;
        RECT  81.168 14.928 81.192 15.12 ;
    END
  END e_i[295]
  PIN e_i[296]
    DIRECTION INPUT ;
    USE SIGNAL ;
    PORT
      LAYER M5 ;
        RECT  81.456 14.928 81.48 15.12 ;
    END
  END e_i[296]
  PIN e_i[297]
    DIRECTION INPUT ;
    USE SIGNAL ;
    PORT
      LAYER M5 ;
        RECT  81.696 14.928 81.72 15.12 ;
    END
  END e_i[297]
  PIN e_i[298]
    DIRECTION INPUT ;
    USE SIGNAL ;
    PORT
      LAYER M5 ;
        RECT  81.936 14.928 81.96 15.12 ;
    END
  END e_i[298]
  PIN e_i[299]
    DIRECTION INPUT ;
    USE SIGNAL ;
    PORT
      LAYER M5 ;
        RECT  82.176 14.928 82.2 15.12 ;
    END
  END e_i[299]
  PIN e_i[29]
    DIRECTION INPUT ;
    USE SIGNAL ;
    PORT
      LAYER M5 ;
        RECT  13.584 14.928 13.608 15.12 ;
    END
  END e_i[29]
  PIN e_i[2]
    DIRECTION INPUT ;
    USE SIGNAL ;
    PORT
      LAYER M5 ;
        RECT  6.72 14.928 6.744 15.12 ;
    END
  END e_i[2]
  PIN e_i[300]
    DIRECTION INPUT ;
    USE SIGNAL ;
    PORT
      LAYER M5 ;
        RECT  82.464 14.928 82.488 15.12 ;
    END
  END e_i[300]
  PIN e_i[301]
    DIRECTION INPUT ;
    USE SIGNAL ;
    PORT
      LAYER M5 ;
        RECT  82.704 14.928 82.728 15.12 ;
    END
  END e_i[301]
  PIN e_i[302]
    DIRECTION INPUT ;
    USE SIGNAL ;
    PORT
      LAYER M5 ;
        RECT  82.944 14.928 82.968 15.12 ;
    END
  END e_i[302]
  PIN e_i[303]
    DIRECTION INPUT ;
    USE SIGNAL ;
    PORT
      LAYER M5 ;
        RECT  83.232 14.928 83.256 15.12 ;
    END
  END e_i[303]
  PIN e_i[304]
    DIRECTION INPUT ;
    USE SIGNAL ;
    PORT
      LAYER M5 ;
        RECT  83.472 14.928 83.496 15.12 ;
    END
  END e_i[304]
  PIN e_i[305]
    DIRECTION INPUT ;
    USE SIGNAL ;
    PORT
      LAYER M5 ;
        RECT  83.712 14.928 83.736 15.12 ;
    END
  END e_i[305]
  PIN e_i[306]
    DIRECTION INPUT ;
    USE SIGNAL ;
    PORT
      LAYER M5 ;
        RECT  83.952 14.928 83.976 15.12 ;
    END
  END e_i[306]
  PIN e_i[307]
    DIRECTION INPUT ;
    USE SIGNAL ;
    PORT
      LAYER M5 ;
        RECT  84.24 14.928 84.264 15.12 ;
    END
  END e_i[307]
  PIN e_i[308]
    DIRECTION INPUT ;
    USE SIGNAL ;
    PORT
      LAYER M5 ;
        RECT  84.48 14.928 84.504 15.12 ;
    END
  END e_i[308]
  PIN e_i[309]
    DIRECTION INPUT ;
    USE SIGNAL ;
    PORT
      LAYER M5 ;
        RECT  84.72 14.928 84.744 15.12 ;
    END
  END e_i[309]
  PIN e_i[30]
    DIRECTION INPUT ;
    USE SIGNAL ;
    PORT
      LAYER M5 ;
        RECT  13.824 14.928 13.848 15.12 ;
    END
  END e_i[30]
  PIN e_i[310]
    DIRECTION INPUT ;
    USE SIGNAL ;
    PORT
      LAYER M5 ;
        RECT  85.008 14.928 85.032 15.12 ;
    END
  END e_i[310]
  PIN e_i[311]
    DIRECTION INPUT ;
    USE SIGNAL ;
    PORT
      LAYER M5 ;
        RECT  85.248 14.928 85.272 15.12 ;
    END
  END e_i[311]
  PIN e_i[312]
    DIRECTION INPUT ;
    USE SIGNAL ;
    PORT
      LAYER M5 ;
        RECT  85.488 14.928 85.512 15.12 ;
    END
  END e_i[312]
  PIN e_i[313]
    DIRECTION INPUT ;
    USE SIGNAL ;
    PORT
      LAYER M5 ;
        RECT  85.776 14.928 85.8 15.12 ;
    END
  END e_i[313]
  PIN e_i[314]
    DIRECTION INPUT ;
    USE SIGNAL ;
    PORT
      LAYER M5 ;
        RECT  86.016 14.928 86.04 15.12 ;
    END
  END e_i[314]
  PIN e_i[315]
    DIRECTION INPUT ;
    USE SIGNAL ;
    PORT
      LAYER M5 ;
        RECT  86.256 14.928 86.28 15.12 ;
    END
  END e_i[315]
  PIN e_i[316]
    DIRECTION INPUT ;
    USE SIGNAL ;
    PORT
      LAYER M5 ;
        RECT  86.496 14.928 86.52 15.12 ;
    END
  END e_i[316]
  PIN e_i[317]
    DIRECTION INPUT ;
    USE SIGNAL ;
    PORT
      LAYER M5 ;
        RECT  86.784 14.928 86.808 15.12 ;
    END
  END e_i[317]
  PIN e_i[318]
    DIRECTION INPUT ;
    USE SIGNAL ;
    PORT
      LAYER M5 ;
        RECT  87.024 14.928 87.048 15.12 ;
    END
  END e_i[318]
  PIN e_i[319]
    DIRECTION INPUT ;
    USE SIGNAL ;
    PORT
      LAYER M5 ;
        RECT  87.264 14.928 87.288 15.12 ;
    END
  END e_i[319]
  PIN e_i[31]
    DIRECTION INPUT ;
    USE SIGNAL ;
    PORT
      LAYER M5 ;
        RECT  14.112 14.928 14.136 15.12 ;
    END
  END e_i[31]
  PIN e_i[320]
    DIRECTION INPUT ;
    USE SIGNAL ;
    PORT
      LAYER M5 ;
        RECT  87.552 14.928 87.576 15.12 ;
    END
  END e_i[320]
  PIN e_i[321]
    DIRECTION INPUT ;
    USE SIGNAL ;
    PORT
      LAYER M5 ;
        RECT  87.792 14.928 87.816 15.12 ;
    END
  END e_i[321]
  PIN e_i[322]
    DIRECTION INPUT ;
    USE SIGNAL ;
    PORT
      LAYER M5 ;
        RECT  88.032 14.928 88.056 15.12 ;
    END
  END e_i[322]
  PIN e_i[323]
    DIRECTION INPUT ;
    USE SIGNAL ;
    PORT
      LAYER M5 ;
        RECT  88.272 14.928 88.296 15.12 ;
    END
  END e_i[323]
  PIN e_i[324]
    DIRECTION INPUT ;
    USE SIGNAL ;
    PORT
      LAYER M5 ;
        RECT  88.56 14.928 88.584 15.12 ;
    END
  END e_i[324]
  PIN e_i[325]
    DIRECTION INPUT ;
    USE SIGNAL ;
    PORT
      LAYER M5 ;
        RECT  88.8 14.928 88.824 15.12 ;
    END
  END e_i[325]
  PIN e_i[326]
    DIRECTION INPUT ;
    USE SIGNAL ;
    PORT
      LAYER M5 ;
        RECT  89.04 14.928 89.064 15.12 ;
    END
  END e_i[326]
  PIN e_i[327]
    DIRECTION INPUT ;
    USE SIGNAL ;
    PORT
      LAYER M5 ;
        RECT  89.328 14.928 89.352 15.12 ;
    END
  END e_i[327]
  PIN e_i[328]
    DIRECTION INPUT ;
    USE SIGNAL ;
    PORT
      LAYER M5 ;
        RECT  89.568 14.928 89.592 15.12 ;
    END
  END e_i[328]
  PIN e_i[329]
    DIRECTION INPUT ;
    USE SIGNAL ;
    PORT
      LAYER M5 ;
        RECT  89.808 14.928 89.832 15.12 ;
    END
  END e_i[329]
  PIN e_i[32]
    DIRECTION INPUT ;
    USE SIGNAL ;
    PORT
      LAYER M5 ;
        RECT  14.352 14.928 14.376 15.12 ;
    END
  END e_i[32]
  PIN e_i[330]
    DIRECTION INPUT ;
    USE SIGNAL ;
    PORT
      LAYER M5 ;
        RECT  90.096 14.928 90.12 15.12 ;
    END
  END e_i[330]
  PIN e_i[331]
    DIRECTION INPUT ;
    USE SIGNAL ;
    PORT
      LAYER M5 ;
        RECT  90.336 14.928 90.36 15.12 ;
    END
  END e_i[331]
  PIN e_i[332]
    DIRECTION INPUT ;
    USE SIGNAL ;
    PORT
      LAYER M5 ;
        RECT  90.576 14.928 90.6 15.12 ;
    END
  END e_i[332]
  PIN e_i[333]
    DIRECTION INPUT ;
    USE SIGNAL ;
    PORT
      LAYER M5 ;
        RECT  90.816 14.928 90.84 15.12 ;
    END
  END e_i[333]
  PIN e_i[334]
    DIRECTION INPUT ;
    USE SIGNAL ;
    PORT
      LAYER M5 ;
        RECT  91.104 14.928 91.128 15.12 ;
    END
  END e_i[334]
  PIN e_i[335]
    DIRECTION INPUT ;
    USE SIGNAL ;
    PORT
      LAYER M5 ;
        RECT  91.344 14.928 91.368 15.12 ;
    END
  END e_i[335]
  PIN e_i[336]
    DIRECTION INPUT ;
    USE SIGNAL ;
    PORT
      LAYER M5 ;
        RECT  91.584 14.928 91.608 15.12 ;
    END
  END e_i[336]
  PIN e_i[337]
    DIRECTION INPUT ;
    USE SIGNAL ;
    PORT
      LAYER M5 ;
        RECT  91.872 14.928 91.896 15.12 ;
    END
  END e_i[337]
  PIN e_i[338]
    DIRECTION INPUT ;
    USE SIGNAL ;
    PORT
      LAYER M5 ;
        RECT  92.112 14.928 92.136 15.12 ;
    END
  END e_i[338]
  PIN e_i[339]
    DIRECTION INPUT ;
    USE SIGNAL ;
    PORT
      LAYER M5 ;
        RECT  92.352 14.928 92.376 15.12 ;
    END
  END e_i[339]
  PIN e_i[33]
    DIRECTION INPUT ;
    USE SIGNAL ;
    PORT
      LAYER M5 ;
        RECT  14.592 14.928 14.616 15.12 ;
    END
  END e_i[33]
  PIN e_i[340]
    DIRECTION INPUT ;
    USE SIGNAL ;
    PORT
      LAYER M5 ;
        RECT  92.592 14.928 92.616 15.12 ;
    END
  END e_i[340]
  PIN e_i[341]
    DIRECTION INPUT ;
    USE SIGNAL ;
    PORT
      LAYER M5 ;
        RECT  92.88 14.928 92.904 15.12 ;
    END
  END e_i[341]
  PIN e_i[342]
    DIRECTION INPUT ;
    USE SIGNAL ;
    PORT
      LAYER M5 ;
        RECT  93.12 14.928 93.144 15.12 ;
    END
  END e_i[342]
  PIN e_i[343]
    DIRECTION INPUT ;
    USE SIGNAL ;
    PORT
      LAYER M5 ;
        RECT  93.36 14.928 93.384 15.12 ;
    END
  END e_i[343]
  PIN e_i[344]
    DIRECTION INPUT ;
    USE SIGNAL ;
    PORT
      LAYER M5 ;
        RECT  93.648 14.928 93.672 15.12 ;
    END
  END e_i[344]
  PIN e_i[345]
    DIRECTION INPUT ;
    USE SIGNAL ;
    PORT
      LAYER M5 ;
        RECT  93.888 14.928 93.912 15.12 ;
    END
  END e_i[345]
  PIN e_i[346]
    DIRECTION INPUT ;
    USE SIGNAL ;
    PORT
      LAYER M5 ;
        RECT  94.128 14.928 94.152 15.12 ;
    END
  END e_i[346]
  PIN e_i[347]
    DIRECTION INPUT ;
    USE SIGNAL ;
    PORT
      LAYER M5 ;
        RECT  94.416 14.928 94.44 15.12 ;
    END
  END e_i[347]
  PIN e_i[348]
    DIRECTION INPUT ;
    USE SIGNAL ;
    PORT
      LAYER M5 ;
        RECT  94.656 14.928 94.68 15.12 ;
    END
  END e_i[348]
  PIN e_i[349]
    DIRECTION INPUT ;
    USE SIGNAL ;
    PORT
      LAYER M5 ;
        RECT  94.896 14.928 94.92 15.12 ;
    END
  END e_i[349]
  PIN e_i[34]
    DIRECTION INPUT ;
    USE SIGNAL ;
    PORT
      LAYER M5 ;
        RECT  14.832 14.928 14.856 15.12 ;
    END
  END e_i[34]
  PIN e_i[350]
    DIRECTION INPUT ;
    USE SIGNAL ;
    PORT
      LAYER M5 ;
        RECT  95.136 14.928 95.16 15.12 ;
    END
  END e_i[350]
  PIN e_i[351]
    DIRECTION INPUT ;
    USE SIGNAL ;
    PORT
      LAYER M5 ;
        RECT  95.424 14.928 95.448 15.12 ;
    END
  END e_i[351]
  PIN e_i[352]
    DIRECTION INPUT ;
    USE SIGNAL ;
    PORT
      LAYER M5 ;
        RECT  95.664 14.928 95.688 15.12 ;
    END
  END e_i[352]
  PIN e_i[353]
    DIRECTION INPUT ;
    USE SIGNAL ;
    PORT
      LAYER M5 ;
        RECT  95.904 14.928 95.928 15.12 ;
    END
  END e_i[353]
  PIN e_i[354]
    DIRECTION INPUT ;
    USE SIGNAL ;
    PORT
      LAYER M5 ;
        RECT  96.192 14.928 96.216 15.12 ;
    END
  END e_i[354]
  PIN e_i[355]
    DIRECTION INPUT ;
    USE SIGNAL ;
    PORT
      LAYER M5 ;
        RECT  96.432 14.928 96.456 15.12 ;
    END
  END e_i[355]
  PIN e_i[356]
    DIRECTION INPUT ;
    USE SIGNAL ;
    PORT
      LAYER M5 ;
        RECT  96.672 14.928 96.696 15.12 ;
    END
  END e_i[356]
  PIN e_i[357]
    DIRECTION INPUT ;
    USE SIGNAL ;
    PORT
      LAYER M5 ;
        RECT  96.912 14.928 96.936 15.12 ;
    END
  END e_i[357]
  PIN e_i[358]
    DIRECTION INPUT ;
    USE SIGNAL ;
    PORT
      LAYER M5 ;
        RECT  97.2 14.928 97.224 15.12 ;
    END
  END e_i[358]
  PIN e_i[359]
    DIRECTION INPUT ;
    USE SIGNAL ;
    PORT
      LAYER M5 ;
        RECT  97.44 14.928 97.464 15.12 ;
    END
  END e_i[359]
  PIN e_i[35]
    DIRECTION INPUT ;
    USE SIGNAL ;
    PORT
      LAYER M5 ;
        RECT  15.12 14.928 15.144 15.12 ;
    END
  END e_i[35]
  PIN e_i[360]
    DIRECTION INPUT ;
    USE SIGNAL ;
    PORT
      LAYER M5 ;
        RECT  97.68 14.928 97.704 15.12 ;
    END
  END e_i[360]
  PIN e_i[361]
    DIRECTION INPUT ;
    USE SIGNAL ;
    PORT
      LAYER M5 ;
        RECT  97.968 14.928 97.992 15.12 ;
    END
  END e_i[361]
  PIN e_i[362]
    DIRECTION INPUT ;
    USE SIGNAL ;
    PORT
      LAYER M5 ;
        RECT  98.208 14.928 98.232 15.12 ;
    END
  END e_i[362]
  PIN e_i[363]
    DIRECTION INPUT ;
    USE SIGNAL ;
    PORT
      LAYER M5 ;
        RECT  98.448 14.928 98.472 15.12 ;
    END
  END e_i[363]
  PIN e_i[364]
    DIRECTION INPUT ;
    USE SIGNAL ;
    PORT
      LAYER M5 ;
        RECT  98.736 14.928 98.76 15.12 ;
    END
  END e_i[364]
  PIN e_i[365]
    DIRECTION INPUT ;
    USE SIGNAL ;
    PORT
      LAYER M5 ;
        RECT  98.976 14.928 99 15.12 ;
    END
  END e_i[365]
  PIN e_i[366]
    DIRECTION INPUT ;
    USE SIGNAL ;
    PORT
      LAYER M5 ;
        RECT  99.216 14.928 99.24 15.12 ;
    END
  END e_i[366]
  PIN e_i[367]
    DIRECTION INPUT ;
    USE SIGNAL ;
    PORT
      LAYER M5 ;
        RECT  99.456 14.928 99.48 15.12 ;
    END
  END e_i[367]
  PIN e_i[368]
    DIRECTION INPUT ;
    USE SIGNAL ;
    PORT
      LAYER M5 ;
        RECT  99.744 14.928 99.768 15.12 ;
    END
  END e_i[368]
  PIN e_i[369]
    DIRECTION INPUT ;
    USE SIGNAL ;
    PORT
      LAYER M5 ;
        RECT  99.984 14.928 100.008 15.12 ;
    END
  END e_i[369]
  PIN e_i[36]
    DIRECTION INPUT ;
    USE SIGNAL ;
    PORT
      LAYER M5 ;
        RECT  15.36 14.928 15.384 15.12 ;
    END
  END e_i[36]
  PIN e_i[370]
    DIRECTION INPUT ;
    USE SIGNAL ;
    PORT
      LAYER M5 ;
        RECT  100.224 14.928 100.248 15.12 ;
    END
  END e_i[370]
  PIN e_i[371]
    DIRECTION INPUT ;
    USE SIGNAL ;
    PORT
      LAYER M5 ;
        RECT  100.512 14.928 100.536 15.12 ;
    END
  END e_i[371]
  PIN e_i[372]
    DIRECTION INPUT ;
    USE SIGNAL ;
    PORT
      LAYER M5 ;
        RECT  100.752 14.928 100.776 15.12 ;
    END
  END e_i[372]
  PIN e_i[373]
    DIRECTION INPUT ;
    USE SIGNAL ;
    PORT
      LAYER M5 ;
        RECT  100.992 14.928 101.016 15.12 ;
    END
  END e_i[373]
  PIN e_i[374]
    DIRECTION INPUT ;
    USE SIGNAL ;
    PORT
      LAYER M5 ;
        RECT  101.232 14.928 101.256 15.12 ;
    END
  END e_i[374]
  PIN e_i[375]
    DIRECTION INPUT ;
    USE SIGNAL ;
    PORT
      LAYER M5 ;
        RECT  101.52 14.928 101.544 15.12 ;
    END
  END e_i[375]
  PIN e_i[376]
    DIRECTION INPUT ;
    USE SIGNAL ;
    PORT
      LAYER M5 ;
        RECT  101.76 14.928 101.784 15.12 ;
    END
  END e_i[376]
  PIN e_i[377]
    DIRECTION INPUT ;
    USE SIGNAL ;
    PORT
      LAYER M5 ;
        RECT  102 14.928 102.024 15.12 ;
    END
  END e_i[377]
  PIN e_i[378]
    DIRECTION INPUT ;
    USE SIGNAL ;
    PORT
      LAYER M5 ;
        RECT  102.288 14.928 102.312 15.12 ;
    END
  END e_i[378]
  PIN e_i[379]
    DIRECTION INPUT ;
    USE SIGNAL ;
    PORT
      LAYER M5 ;
        RECT  102.528 14.928 102.552 15.12 ;
    END
  END e_i[379]
  PIN e_i[37]
    DIRECTION INPUT ;
    USE SIGNAL ;
    PORT
      LAYER M5 ;
        RECT  15.6 14.928 15.624 15.12 ;
    END
  END e_i[37]
  PIN e_i[380]
    DIRECTION INPUT ;
    USE SIGNAL ;
    PORT
      LAYER M5 ;
        RECT  102.768 14.928 102.792 15.12 ;
    END
  END e_i[380]
  PIN e_i[381]
    DIRECTION INPUT ;
    USE SIGNAL ;
    PORT
      LAYER M5 ;
        RECT  103.056 14.928 103.08 15.12 ;
    END
  END e_i[381]
  PIN e_i[382]
    DIRECTION INPUT ;
    USE SIGNAL ;
    PORT
      LAYER M5 ;
        RECT  103.296 14.928 103.32 15.12 ;
    END
  END e_i[382]
  PIN e_i[383]
    DIRECTION INPUT ;
    USE SIGNAL ;
    PORT
      LAYER M5 ;
        RECT  103.536 14.928 103.56 15.12 ;
    END
  END e_i[383]
  PIN e_i[384]
    DIRECTION INPUT ;
    USE SIGNAL ;
    PORT
      LAYER M5 ;
        RECT  103.776 14.928 103.8 15.12 ;
    END
  END e_i[384]
  PIN e_i[385]
    DIRECTION INPUT ;
    USE SIGNAL ;
    PORT
      LAYER M5 ;
        RECT  104.064 14.928 104.088 15.12 ;
    END
  END e_i[385]
  PIN e_i[386]
    DIRECTION INPUT ;
    USE SIGNAL ;
    PORT
      LAYER M5 ;
        RECT  104.304 14.928 104.328 15.12 ;
    END
  END e_i[386]
  PIN e_i[387]
    DIRECTION INPUT ;
    USE SIGNAL ;
    PORT
      LAYER M5 ;
        RECT  104.544 14.928 104.568 15.12 ;
    END
  END e_i[387]
  PIN e_i[388]
    DIRECTION INPUT ;
    USE SIGNAL ;
    PORT
      LAYER M5 ;
        RECT  104.832 14.928 104.856 15.12 ;
    END
  END e_i[388]
  PIN e_i[389]
    DIRECTION INPUT ;
    USE SIGNAL ;
    PORT
      LAYER M5 ;
        RECT  105.072 14.928 105.096 15.12 ;
    END
  END e_i[389]
  PIN e_i[38]
    DIRECTION INPUT ;
    USE SIGNAL ;
    PORT
      LAYER M5 ;
        RECT  15.888 14.928 15.912 15.12 ;
    END
  END e_i[38]
  PIN e_i[390]
    DIRECTION INPUT ;
    USE SIGNAL ;
    PORT
      LAYER M5 ;
        RECT  105.312 14.928 105.336 15.12 ;
    END
  END e_i[390]
  PIN e_i[391]
    DIRECTION INPUT ;
    USE SIGNAL ;
    PORT
      LAYER M5 ;
        RECT  105.552 14.928 105.576 15.12 ;
    END
  END e_i[391]
  PIN e_i[392]
    DIRECTION INPUT ;
    USE SIGNAL ;
    PORT
      LAYER M5 ;
        RECT  105.84 14.928 105.864 15.12 ;
    END
  END e_i[392]
  PIN e_i[393]
    DIRECTION INPUT ;
    USE SIGNAL ;
    PORT
      LAYER M5 ;
        RECT  106.08 14.928 106.104 15.12 ;
    END
  END e_i[393]
  PIN e_i[394]
    DIRECTION INPUT ;
    USE SIGNAL ;
    PORT
      LAYER M5 ;
        RECT  106.32 14.928 106.344 15.12 ;
    END
  END e_i[394]
  PIN e_i[395]
    DIRECTION INPUT ;
    USE SIGNAL ;
    PORT
      LAYER M5 ;
        RECT  106.608 14.928 106.632 15.12 ;
    END
  END e_i[395]
  PIN e_i[396]
    DIRECTION INPUT ;
    USE SIGNAL ;
    PORT
      LAYER M5 ;
        RECT  106.848 14.928 106.872 15.12 ;
    END
  END e_i[396]
  PIN e_i[397]
    DIRECTION INPUT ;
    USE SIGNAL ;
    PORT
      LAYER M5 ;
        RECT  107.088 14.928 107.112 15.12 ;
    END
  END e_i[397]
  PIN e_i[398]
    DIRECTION INPUT ;
    USE SIGNAL ;
    PORT
      LAYER M5 ;
        RECT  107.376 14.928 107.4 15.12 ;
    END
  END e_i[398]
  PIN e_i[399]
    DIRECTION INPUT ;
    USE SIGNAL ;
    PORT
      LAYER M5 ;
        RECT  107.616 14.928 107.64 15.12 ;
    END
  END e_i[399]
  PIN e_i[39]
    DIRECTION INPUT ;
    USE SIGNAL ;
    PORT
      LAYER M5 ;
        RECT  16.128 14.928 16.152 15.12 ;
    END
  END e_i[39]
  PIN e_i[3]
    DIRECTION INPUT ;
    USE SIGNAL ;
    PORT
      LAYER M5 ;
        RECT  6.96 14.928 6.984 15.12 ;
    END
  END e_i[3]
  PIN e_i[400]
    DIRECTION INPUT ;
    USE SIGNAL ;
    PORT
      LAYER M5 ;
        RECT  107.856 14.928 107.88 15.12 ;
    END
  END e_i[400]
  PIN e_i[401]
    DIRECTION INPUT ;
    USE SIGNAL ;
    PORT
      LAYER M5 ;
        RECT  108.096 14.928 108.12 15.12 ;
    END
  END e_i[401]
  PIN e_i[402]
    DIRECTION INPUT ;
    USE SIGNAL ;
    PORT
      LAYER M5 ;
        RECT  108.384 14.928 108.408 15.12 ;
    END
  END e_i[402]
  PIN e_i[403]
    DIRECTION INPUT ;
    USE SIGNAL ;
    PORT
      LAYER M5 ;
        RECT  108.624 14.928 108.648 15.12 ;
    END
  END e_i[403]
  PIN e_i[404]
    DIRECTION INPUT ;
    USE SIGNAL ;
    PORT
      LAYER M5 ;
        RECT  108.864 14.928 108.888 15.12 ;
    END
  END e_i[404]
  PIN e_i[405]
    DIRECTION INPUT ;
    USE SIGNAL ;
    PORT
      LAYER M5 ;
        RECT  109.152 14.928 109.176 15.12 ;
    END
  END e_i[405]
  PIN e_i[406]
    DIRECTION INPUT ;
    USE SIGNAL ;
    PORT
      LAYER M5 ;
        RECT  109.392 14.928 109.416 15.12 ;
    END
  END e_i[406]
  PIN e_i[407]
    DIRECTION INPUT ;
    USE SIGNAL ;
    PORT
      LAYER M5 ;
        RECT  109.632 14.928 109.656 15.12 ;
    END
  END e_i[407]
  PIN e_i[408]
    DIRECTION INPUT ;
    USE SIGNAL ;
    PORT
      LAYER M5 ;
        RECT  109.872 14.928 109.896 15.12 ;
    END
  END e_i[408]
  PIN e_i[409]
    DIRECTION INPUT ;
    USE SIGNAL ;
    PORT
      LAYER M5 ;
        RECT  110.16 14.928 110.184 15.12 ;
    END
  END e_i[409]
  PIN e_i[40]
    DIRECTION INPUT ;
    USE SIGNAL ;
    PORT
      LAYER M5 ;
        RECT  16.368 14.928 16.392 15.12 ;
    END
  END e_i[40]
  PIN e_i[410]
    DIRECTION INPUT ;
    USE SIGNAL ;
    PORT
      LAYER M5 ;
        RECT  110.4 14.928 110.424 15.12 ;
    END
  END e_i[410]
  PIN e_i[411]
    DIRECTION INPUT ;
    USE SIGNAL ;
    PORT
      LAYER M5 ;
        RECT  110.64 14.928 110.664 15.12 ;
    END
  END e_i[411]
  PIN e_i[412]
    DIRECTION INPUT ;
    USE SIGNAL ;
    PORT
      LAYER M5 ;
        RECT  110.928 14.928 110.952 15.12 ;
    END
  END e_i[412]
  PIN e_i[413]
    DIRECTION INPUT ;
    USE SIGNAL ;
    PORT
      LAYER M5 ;
        RECT  111.168 14.928 111.192 15.12 ;
    END
  END e_i[413]
  PIN e_i[414]
    DIRECTION INPUT ;
    USE SIGNAL ;
    PORT
      LAYER M5 ;
        RECT  111.408 14.928 111.432 15.12 ;
    END
  END e_i[414]
  PIN e_i[415]
    DIRECTION INPUT ;
    USE SIGNAL ;
    PORT
      LAYER M5 ;
        RECT  111.696 14.928 111.72 15.12 ;
    END
  END e_i[415]
  PIN e_i[416]
    DIRECTION INPUT ;
    USE SIGNAL ;
    PORT
      LAYER M5 ;
        RECT  111.936 14.928 111.96 15.12 ;
    END
  END e_i[416]
  PIN e_i[417]
    DIRECTION INPUT ;
    USE SIGNAL ;
    PORT
      LAYER M5 ;
        RECT  112.176 14.928 112.2 15.12 ;
    END
  END e_i[417]
  PIN e_i[418]
    DIRECTION INPUT ;
    USE SIGNAL ;
    PORT
      LAYER M5 ;
        RECT  112.416 14.928 112.44 15.12 ;
    END
  END e_i[418]
  PIN e_i[419]
    DIRECTION INPUT ;
    USE SIGNAL ;
    PORT
      LAYER M5 ;
        RECT  112.704 14.928 112.728 15.12 ;
    END
  END e_i[419]
  PIN e_i[41]
    DIRECTION INPUT ;
    USE SIGNAL ;
    PORT
      LAYER M5 ;
        RECT  16.656 14.928 16.68 15.12 ;
    END
  END e_i[41]
  PIN e_i[420]
    DIRECTION INPUT ;
    USE SIGNAL ;
    PORT
      LAYER M5 ;
        RECT  112.944 14.928 112.968 15.12 ;
    END
  END e_i[420]
  PIN e_i[421]
    DIRECTION INPUT ;
    USE SIGNAL ;
    PORT
      LAYER M5 ;
        RECT  113.184 14.928 113.208 15.12 ;
    END
  END e_i[421]
  PIN e_i[422]
    DIRECTION INPUT ;
    USE SIGNAL ;
    PORT
      LAYER M5 ;
        RECT  113.472 14.928 113.496 15.12 ;
    END
  END e_i[422]
  PIN e_i[423]
    DIRECTION INPUT ;
    USE SIGNAL ;
    PORT
      LAYER M5 ;
        RECT  113.712 14.928 113.736 15.12 ;
    END
  END e_i[423]
  PIN e_i[424]
    DIRECTION INPUT ;
    USE SIGNAL ;
    PORT
      LAYER M5 ;
        RECT  113.952 14.928 113.976 15.12 ;
    END
  END e_i[424]
  PIN e_i[425]
    DIRECTION INPUT ;
    USE SIGNAL ;
    PORT
      LAYER M5 ;
        RECT  114.192 14.928 114.216 15.12 ;
    END
  END e_i[425]
  PIN e_i[426]
    DIRECTION INPUT ;
    USE SIGNAL ;
    PORT
      LAYER M5 ;
        RECT  114.48 14.928 114.504 15.12 ;
    END
  END e_i[426]
  PIN e_i[427]
    DIRECTION INPUT ;
    USE SIGNAL ;
    PORT
      LAYER M5 ;
        RECT  114.72 14.928 114.744 15.12 ;
    END
  END e_i[427]
  PIN e_i[428]
    DIRECTION INPUT ;
    USE SIGNAL ;
    PORT
      LAYER M5 ;
        RECT  114.96 14.928 114.984 15.12 ;
    END
  END e_i[428]
  PIN e_i[429]
    DIRECTION INPUT ;
    USE SIGNAL ;
    PORT
      LAYER M5 ;
        RECT  115.248 14.928 115.272 15.12 ;
    END
  END e_i[429]
  PIN e_i[42]
    DIRECTION INPUT ;
    USE SIGNAL ;
    PORT
      LAYER M5 ;
        RECT  16.896 14.928 16.92 15.12 ;
    END
  END e_i[42]
  PIN e_i[430]
    DIRECTION INPUT ;
    USE SIGNAL ;
    PORT
      LAYER M5 ;
        RECT  115.488 14.928 115.512 15.12 ;
    END
  END e_i[430]
  PIN e_i[431]
    DIRECTION INPUT ;
    USE SIGNAL ;
    PORT
      LAYER M5 ;
        RECT  115.728 14.928 115.752 15.12 ;
    END
  END e_i[431]
  PIN e_i[432]
    DIRECTION INPUT ;
    USE SIGNAL ;
    PORT
      LAYER M5 ;
        RECT  116.016 14.928 116.04 15.12 ;
    END
  END e_i[432]
  PIN e_i[433]
    DIRECTION INPUT ;
    USE SIGNAL ;
    PORT
      LAYER M5 ;
        RECT  116.256 14.928 116.28 15.12 ;
    END
  END e_i[433]
  PIN e_i[434]
    DIRECTION INPUT ;
    USE SIGNAL ;
    PORT
      LAYER M5 ;
        RECT  116.496 14.928 116.52 15.12 ;
    END
  END e_i[434]
  PIN e_i[435]
    DIRECTION INPUT ;
    USE SIGNAL ;
    PORT
      LAYER M5 ;
        RECT  116.736 14.928 116.76 15.12 ;
    END
  END e_i[435]
  PIN e_i[436]
    DIRECTION INPUT ;
    USE SIGNAL ;
    PORT
      LAYER M5 ;
        RECT  117.024 14.928 117.048 15.12 ;
    END
  END e_i[436]
  PIN e_i[437]
    DIRECTION INPUT ;
    USE SIGNAL ;
    PORT
      LAYER M5 ;
        RECT  117.264 14.928 117.288 15.12 ;
    END
  END e_i[437]
  PIN e_i[438]
    DIRECTION INPUT ;
    USE SIGNAL ;
    PORT
      LAYER M5 ;
        RECT  117.504 14.928 117.528 15.12 ;
    END
  END e_i[438]
  PIN e_i[439]
    DIRECTION INPUT ;
    USE SIGNAL ;
    PORT
      LAYER M5 ;
        RECT  117.792 14.928 117.816 15.12 ;
    END
  END e_i[439]
  PIN e_i[43]
    DIRECTION INPUT ;
    USE SIGNAL ;
    PORT
      LAYER M5 ;
        RECT  17.136 14.928 17.16 15.12 ;
    END
  END e_i[43]
  PIN e_i[440]
    DIRECTION INPUT ;
    USE SIGNAL ;
    PORT
      LAYER M5 ;
        RECT  118.032 14.928 118.056 15.12 ;
    END
  END e_i[440]
  PIN e_i[441]
    DIRECTION INPUT ;
    USE SIGNAL ;
    PORT
      LAYER M5 ;
        RECT  118.272 14.928 118.296 15.12 ;
    END
  END e_i[441]
  PIN e_i[442]
    DIRECTION INPUT ;
    USE SIGNAL ;
    PORT
      LAYER M5 ;
        RECT  118.512 14.928 118.536 15.12 ;
    END
  END e_i[442]
  PIN e_i[443]
    DIRECTION INPUT ;
    USE SIGNAL ;
    PORT
      LAYER M5 ;
        RECT  118.8 14.928 118.824 15.12 ;
    END
  END e_i[443]
  PIN e_i[444]
    DIRECTION INPUT ;
    USE SIGNAL ;
    PORT
      LAYER M5 ;
        RECT  119.04 14.928 119.064 15.12 ;
    END
  END e_i[444]
  PIN e_i[445]
    DIRECTION INPUT ;
    USE SIGNAL ;
    PORT
      LAYER M5 ;
        RECT  119.28 14.928 119.304 15.12 ;
    END
  END e_i[445]
  PIN e_i[446]
    DIRECTION INPUT ;
    USE SIGNAL ;
    PORT
      LAYER M5 ;
        RECT  119.568 14.928 119.592 15.12 ;
    END
  END e_i[446]
  PIN e_i[447]
    DIRECTION INPUT ;
    USE SIGNAL ;
    PORT
      LAYER M5 ;
        RECT  119.808 14.928 119.832 15.12 ;
    END
  END e_i[447]
  PIN e_i[448]
    DIRECTION INPUT ;
    USE SIGNAL ;
    PORT
      LAYER M5 ;
        RECT  120.048 14.928 120.072 15.12 ;
    END
  END e_i[448]
  PIN e_i[449]
    DIRECTION INPUT ;
    USE SIGNAL ;
    PORT
      LAYER M5 ;
        RECT  120.336 14.928 120.36 15.12 ;
    END
  END e_i[449]
  PIN e_i[44]
    DIRECTION INPUT ;
    USE SIGNAL ;
    PORT
      LAYER M5 ;
        RECT  17.376 14.928 17.4 15.12 ;
    END
  END e_i[44]
  PIN e_i[450]
    DIRECTION INPUT ;
    USE SIGNAL ;
    PORT
      LAYER M5 ;
        RECT  120.576 14.928 120.6 15.12 ;
    END
  END e_i[450]
  PIN e_i[451]
    DIRECTION INPUT ;
    USE SIGNAL ;
    PORT
      LAYER M5 ;
        RECT  120.816 14.928 120.84 15.12 ;
    END
  END e_i[451]
  PIN e_i[452]
    DIRECTION INPUT ;
    USE SIGNAL ;
    PORT
      LAYER M5 ;
        RECT  121.056 14.928 121.08 15.12 ;
    END
  END e_i[452]
  PIN e_i[453]
    DIRECTION INPUT ;
    USE SIGNAL ;
    PORT
      LAYER M5 ;
        RECT  121.344 14.928 121.368 15.12 ;
    END
  END e_i[453]
  PIN e_i[454]
    DIRECTION INPUT ;
    USE SIGNAL ;
    PORT
      LAYER M5 ;
        RECT  121.584 14.928 121.608 15.12 ;
    END
  END e_i[454]
  PIN e_i[455]
    DIRECTION INPUT ;
    USE SIGNAL ;
    PORT
      LAYER M5 ;
        RECT  121.824 14.928 121.848 15.12 ;
    END
  END e_i[455]
  PIN e_i[456]
    DIRECTION INPUT ;
    USE SIGNAL ;
    PORT
      LAYER M5 ;
        RECT  122.112 14.928 122.136 15.12 ;
    END
  END e_i[456]
  PIN e_i[457]
    DIRECTION INPUT ;
    USE SIGNAL ;
    PORT
      LAYER M5 ;
        RECT  122.352 14.928 122.376 15.12 ;
    END
  END e_i[457]
  PIN e_i[458]
    DIRECTION INPUT ;
    USE SIGNAL ;
    PORT
      LAYER M5 ;
        RECT  122.592 14.928 122.616 15.12 ;
    END
  END e_i[458]
  PIN e_i[459]
    DIRECTION INPUT ;
    USE SIGNAL ;
    PORT
      LAYER M5 ;
        RECT  122.832 14.928 122.856 15.12 ;
    END
  END e_i[459]
  PIN e_i[45]
    DIRECTION INPUT ;
    USE SIGNAL ;
    PORT
      LAYER M5 ;
        RECT  17.664 14.928 17.688 15.12 ;
    END
  END e_i[45]
  PIN e_i[460]
    DIRECTION INPUT ;
    USE SIGNAL ;
    PORT
      LAYER M5 ;
        RECT  123.12 14.928 123.144 15.12 ;
    END
  END e_i[460]
  PIN e_i[461]
    DIRECTION INPUT ;
    USE SIGNAL ;
    PORT
      LAYER M5 ;
        RECT  123.36 14.928 123.384 15.12 ;
    END
  END e_i[461]
  PIN e_i[462]
    DIRECTION INPUT ;
    USE SIGNAL ;
    PORT
      LAYER M5 ;
        RECT  123.6 14.928 123.624 15.12 ;
    END
  END e_i[462]
  PIN e_i[463]
    DIRECTION INPUT ;
    USE SIGNAL ;
    PORT
      LAYER M5 ;
        RECT  123.888 14.928 123.912 15.12 ;
    END
  END e_i[463]
  PIN e_i[464]
    DIRECTION INPUT ;
    USE SIGNAL ;
    PORT
      LAYER M5 ;
        RECT  124.128 14.928 124.152 15.12 ;
    END
  END e_i[464]
  PIN e_i[465]
    DIRECTION INPUT ;
    USE SIGNAL ;
    PORT
      LAYER M5 ;
        RECT  124.368 14.928 124.392 15.12 ;
    END
  END e_i[465]
  PIN e_i[466]
    DIRECTION INPUT ;
    USE SIGNAL ;
    PORT
      LAYER M5 ;
        RECT  124.656 14.928 124.68 15.12 ;
    END
  END e_i[466]
  PIN e_i[467]
    DIRECTION INPUT ;
    USE SIGNAL ;
    PORT
      LAYER M5 ;
        RECT  124.896 14.928 124.92 15.12 ;
    END
  END e_i[467]
  PIN e_i[468]
    DIRECTION INPUT ;
    USE SIGNAL ;
    PORT
      LAYER M5 ;
        RECT  125.136 14.928 125.16 15.12 ;
    END
  END e_i[468]
  PIN e_i[469]
    DIRECTION INPUT ;
    USE SIGNAL ;
    PORT
      LAYER M5 ;
        RECT  125.376 14.928 125.4 15.12 ;
    END
  END e_i[469]
  PIN e_i[46]
    DIRECTION INPUT ;
    USE SIGNAL ;
    PORT
      LAYER M5 ;
        RECT  17.904 14.928 17.928 15.12 ;
    END
  END e_i[46]
  PIN e_i[470]
    DIRECTION INPUT ;
    USE SIGNAL ;
    PORT
      LAYER M5 ;
        RECT  125.664 14.928 125.688 15.12 ;
    END
  END e_i[470]
  PIN e_i[471]
    DIRECTION INPUT ;
    USE SIGNAL ;
    PORT
      LAYER M5 ;
        RECT  125.904 14.928 125.928 15.12 ;
    END
  END e_i[471]
  PIN e_i[472]
    DIRECTION INPUT ;
    USE SIGNAL ;
    PORT
      LAYER M5 ;
        RECT  126.144 14.928 126.168 15.12 ;
    END
  END e_i[472]
  PIN e_i[473]
    DIRECTION INPUT ;
    USE SIGNAL ;
    PORT
      LAYER M5 ;
        RECT  126.432 14.928 126.456 15.12 ;
    END
  END e_i[473]
  PIN e_i[474]
    DIRECTION INPUT ;
    USE SIGNAL ;
    PORT
      LAYER M5 ;
        RECT  126.672 14.928 126.696 15.12 ;
    END
  END e_i[474]
  PIN e_i[475]
    DIRECTION INPUT ;
    USE SIGNAL ;
    PORT
      LAYER M5 ;
        RECT  126.912 14.928 126.936 15.12 ;
    END
  END e_i[475]
  PIN e_i[476]
    DIRECTION INPUT ;
    USE SIGNAL ;
    PORT
      LAYER M5 ;
        RECT  127.152 14.928 127.176 15.12 ;
    END
  END e_i[476]
  PIN e_i[477]
    DIRECTION INPUT ;
    USE SIGNAL ;
    PORT
      LAYER M5 ;
        RECT  127.44 14.928 127.464 15.12 ;
    END
  END e_i[477]
  PIN e_i[478]
    DIRECTION INPUT ;
    USE SIGNAL ;
    PORT
      LAYER M5 ;
        RECT  127.68 14.928 127.704 15.12 ;
    END
  END e_i[478]
  PIN e_i[479]
    DIRECTION INPUT ;
    USE SIGNAL ;
    PORT
      LAYER M5 ;
        RECT  127.92 14.928 127.944 15.12 ;
    END
  END e_i[479]
  PIN e_i[47]
    DIRECTION INPUT ;
    USE SIGNAL ;
    PORT
      LAYER M5 ;
        RECT  18.144 14.928 18.168 15.12 ;
    END
  END e_i[47]
  PIN e_i[480]
    DIRECTION INPUT ;
    USE SIGNAL ;
    PORT
      LAYER M5 ;
        RECT  128.208 14.928 128.232 15.12 ;
    END
  END e_i[480]
  PIN e_i[481]
    DIRECTION INPUT ;
    USE SIGNAL ;
    PORT
      LAYER M5 ;
        RECT  128.448 14.928 128.472 15.12 ;
    END
  END e_i[481]
  PIN e_i[482]
    DIRECTION INPUT ;
    USE SIGNAL ;
    PORT
      LAYER M5 ;
        RECT  128.688 14.928 128.712 15.12 ;
    END
  END e_i[482]
  PIN e_i[483]
    DIRECTION INPUT ;
    USE SIGNAL ;
    PORT
      LAYER M5 ;
        RECT  128.976 14.928 129 15.12 ;
    END
  END e_i[483]
  PIN e_i[484]
    DIRECTION INPUT ;
    USE SIGNAL ;
    PORT
      LAYER M5 ;
        RECT  129.216 14.928 129.24 15.12 ;
    END
  END e_i[484]
  PIN e_i[485]
    DIRECTION INPUT ;
    USE SIGNAL ;
    PORT
      LAYER M5 ;
        RECT  129.456 14.928 129.48 15.12 ;
    END
  END e_i[485]
  PIN e_i[486]
    DIRECTION INPUT ;
    USE SIGNAL ;
    PORT
      LAYER M5 ;
        RECT  129.696 14.928 129.72 15.12 ;
    END
  END e_i[486]
  PIN e_i[487]
    DIRECTION INPUT ;
    USE SIGNAL ;
    PORT
      LAYER M5 ;
        RECT  129.984 14.928 130.008 15.12 ;
    END
  END e_i[487]
  PIN e_i[488]
    DIRECTION INPUT ;
    USE SIGNAL ;
    PORT
      LAYER M5 ;
        RECT  130.224 14.928 130.248 15.12 ;
    END
  END e_i[488]
  PIN e_i[489]
    DIRECTION INPUT ;
    USE SIGNAL ;
    PORT
      LAYER M5 ;
        RECT  130.464 14.928 130.488 15.12 ;
    END
  END e_i[489]
  PIN e_i[48]
    DIRECTION INPUT ;
    USE SIGNAL ;
    PORT
      LAYER M5 ;
        RECT  18.432 14.928 18.456 15.12 ;
    END
  END e_i[48]
  PIN e_i[490]
    DIRECTION INPUT ;
    USE SIGNAL ;
    PORT
      LAYER M5 ;
        RECT  130.752 14.928 130.776 15.12 ;
    END
  END e_i[490]
  PIN e_i[491]
    DIRECTION INPUT ;
    USE SIGNAL ;
    PORT
      LAYER M5 ;
        RECT  130.992 14.928 131.016 15.12 ;
    END
  END e_i[491]
  PIN e_i[492]
    DIRECTION INPUT ;
    USE SIGNAL ;
    PORT
      LAYER M5 ;
        RECT  131.232 14.928 131.256 15.12 ;
    END
  END e_i[492]
  PIN e_i[493]
    DIRECTION INPUT ;
    USE SIGNAL ;
    PORT
      LAYER M5 ;
        RECT  131.472 14.928 131.496 15.12 ;
    END
  END e_i[493]
  PIN e_i[494]
    DIRECTION INPUT ;
    USE SIGNAL ;
    PORT
      LAYER M5 ;
        RECT  131.76 14.928 131.784 15.12 ;
    END
  END e_i[494]
  PIN e_i[495]
    DIRECTION INPUT ;
    USE SIGNAL ;
    PORT
      LAYER M5 ;
        RECT  132 14.928 132.024 15.12 ;
    END
  END e_i[495]
  PIN e_i[496]
    DIRECTION INPUT ;
    USE SIGNAL ;
    PORT
      LAYER M5 ;
        RECT  132.24 14.928 132.264 15.12 ;
    END
  END e_i[496]
  PIN e_i[497]
    DIRECTION INPUT ;
    USE SIGNAL ;
    PORT
      LAYER M5 ;
        RECT  132.528 14.928 132.552 15.12 ;
    END
  END e_i[497]
  PIN e_i[498]
    DIRECTION INPUT ;
    USE SIGNAL ;
    PORT
      LAYER M5 ;
        RECT  132.768 14.928 132.792 15.12 ;
    END
  END e_i[498]
  PIN e_i[499]
    DIRECTION INPUT ;
    USE SIGNAL ;
    PORT
      LAYER M5 ;
        RECT  133.008 14.928 133.032 15.12 ;
    END
  END e_i[499]
  PIN e_i[49]
    DIRECTION INPUT ;
    USE SIGNAL ;
    PORT
      LAYER M5 ;
        RECT  18.672 14.928 18.696 15.12 ;
    END
  END e_i[49]
  PIN e_i[4]
    DIRECTION INPUT ;
    USE SIGNAL ;
    PORT
      LAYER M5 ;
        RECT  7.248 14.928 7.272 15.12 ;
    END
  END e_i[4]
  PIN e_i[500]
    DIRECTION INPUT ;
    USE SIGNAL ;
    PORT
      LAYER M5 ;
        RECT  133.296 14.928 133.32 15.12 ;
    END
  END e_i[500]
  PIN e_i[501]
    DIRECTION INPUT ;
    USE SIGNAL ;
    PORT
      LAYER M5 ;
        RECT  133.536 14.928 133.56 15.12 ;
    END
  END e_i[501]
  PIN e_i[502]
    DIRECTION INPUT ;
    USE SIGNAL ;
    PORT
      LAYER M5 ;
        RECT  133.776 14.928 133.8 15.12 ;
    END
  END e_i[502]
  PIN e_i[503]
    DIRECTION INPUT ;
    USE SIGNAL ;
    PORT
      LAYER M5 ;
        RECT  134.016 14.928 134.04 15.12 ;
    END
  END e_i[503]
  PIN e_i[504]
    DIRECTION INPUT ;
    USE SIGNAL ;
    PORT
      LAYER M5 ;
        RECT  134.304 14.928 134.328 15.12 ;
    END
  END e_i[504]
  PIN e_i[505]
    DIRECTION INPUT ;
    USE SIGNAL ;
    PORT
      LAYER M5 ;
        RECT  134.544 14.928 134.568 15.12 ;
    END
  END e_i[505]
  PIN e_i[506]
    DIRECTION INPUT ;
    USE SIGNAL ;
    PORT
      LAYER M5 ;
        RECT  134.784 14.928 134.808 15.12 ;
    END
  END e_i[506]
  PIN e_i[507]
    DIRECTION INPUT ;
    USE SIGNAL ;
    PORT
      LAYER M5 ;
        RECT  135.072 14.928 135.096 15.12 ;
    END
  END e_i[507]
  PIN e_i[508]
    DIRECTION INPUT ;
    USE SIGNAL ;
    PORT
      LAYER M5 ;
        RECT  135.312 14.928 135.336 15.12 ;
    END
  END e_i[508]
  PIN e_i[509]
    DIRECTION INPUT ;
    USE SIGNAL ;
    PORT
      LAYER M5 ;
        RECT  135.552 14.928 135.576 15.12 ;
    END
  END e_i[509]
  PIN e_i[50]
    DIRECTION INPUT ;
    USE SIGNAL ;
    PORT
      LAYER M5 ;
        RECT  18.912 14.928 18.936 15.12 ;
    END
  END e_i[50]
  PIN e_i[510]
    DIRECTION INPUT ;
    USE SIGNAL ;
    PORT
      LAYER M5 ;
        RECT  135.792 14.928 135.816 15.12 ;
    END
  END e_i[510]
  PIN e_i[511]
    DIRECTION INPUT ;
    USE SIGNAL ;
    PORT
      LAYER M5 ;
        RECT  136.08 14.928 136.104 15.12 ;
    END
  END e_i[511]
  PIN e_i[51]
    DIRECTION INPUT ;
    USE SIGNAL ;
    PORT
      LAYER M5 ;
        RECT  19.152 14.928 19.176 15.12 ;
    END
  END e_i[51]
  PIN e_i[52]
    DIRECTION INPUT ;
    USE SIGNAL ;
    PORT
      LAYER M5 ;
        RECT  19.44 14.928 19.464 15.12 ;
    END
  END e_i[52]
  PIN e_i[53]
    DIRECTION INPUT ;
    USE SIGNAL ;
    PORT
      LAYER M5 ;
        RECT  19.68 14.928 19.704 15.12 ;
    END
  END e_i[53]
  PIN e_i[54]
    DIRECTION INPUT ;
    USE SIGNAL ;
    PORT
      LAYER M5 ;
        RECT  19.92 14.928 19.944 15.12 ;
    END
  END e_i[54]
  PIN e_i[55]
    DIRECTION INPUT ;
    USE SIGNAL ;
    PORT
      LAYER M5 ;
        RECT  20.208 14.928 20.232 15.12 ;
    END
  END e_i[55]
  PIN e_i[56]
    DIRECTION INPUT ;
    USE SIGNAL ;
    PORT
      LAYER M5 ;
        RECT  20.448 14.928 20.472 15.12 ;
    END
  END e_i[56]
  PIN e_i[57]
    DIRECTION INPUT ;
    USE SIGNAL ;
    PORT
      LAYER M5 ;
        RECT  20.688 14.928 20.712 15.12 ;
    END
  END e_i[57]
  PIN e_i[58]
    DIRECTION INPUT ;
    USE SIGNAL ;
    PORT
      LAYER M5 ;
        RECT  20.976 14.928 21 15.12 ;
    END
  END e_i[58]
  PIN e_i[59]
    DIRECTION INPUT ;
    USE SIGNAL ;
    PORT
      LAYER M5 ;
        RECT  21.216 14.928 21.24 15.12 ;
    END
  END e_i[59]
  PIN e_i[5]
    DIRECTION INPUT ;
    USE SIGNAL ;
    PORT
      LAYER M5 ;
        RECT  7.488 14.928 7.512 15.12 ;
    END
  END e_i[5]
  PIN e_i[60]
    DIRECTION INPUT ;
    USE SIGNAL ;
    PORT
      LAYER M5 ;
        RECT  21.456 14.928 21.48 15.12 ;
    END
  END e_i[60]
  PIN e_i[61]
    DIRECTION INPUT ;
    USE SIGNAL ;
    PORT
      LAYER M5 ;
        RECT  21.696 14.928 21.72 15.12 ;
    END
  END e_i[61]
  PIN e_i[62]
    DIRECTION INPUT ;
    USE SIGNAL ;
    PORT
      LAYER M5 ;
        RECT  21.984 14.928 22.008 15.12 ;
    END
  END e_i[62]
  PIN e_i[63]
    DIRECTION INPUT ;
    USE SIGNAL ;
    PORT
      LAYER M5 ;
        RECT  22.224 14.928 22.248 15.12 ;
    END
  END e_i[63]
  PIN e_i[64]
    DIRECTION INPUT ;
    USE SIGNAL ;
    PORT
      LAYER M5 ;
        RECT  22.464 14.928 22.488 15.12 ;
    END
  END e_i[64]
  PIN e_i[65]
    DIRECTION INPUT ;
    USE SIGNAL ;
    PORT
      LAYER M5 ;
        RECT  22.752 14.928 22.776 15.12 ;
    END
  END e_i[65]
  PIN e_i[66]
    DIRECTION INPUT ;
    USE SIGNAL ;
    PORT
      LAYER M5 ;
        RECT  22.992 14.928 23.016 15.12 ;
    END
  END e_i[66]
  PIN e_i[67]
    DIRECTION INPUT ;
    USE SIGNAL ;
    PORT
      LAYER M5 ;
        RECT  23.232 14.928 23.256 15.12 ;
    END
  END e_i[67]
  PIN e_i[68]
    DIRECTION INPUT ;
    USE SIGNAL ;
    PORT
      LAYER M5 ;
        RECT  23.472 14.928 23.496 15.12 ;
    END
  END e_i[68]
  PIN e_i[69]
    DIRECTION INPUT ;
    USE SIGNAL ;
    PORT
      LAYER M5 ;
        RECT  23.76 14.928 23.784 15.12 ;
    END
  END e_i[69]
  PIN e_i[6]
    DIRECTION INPUT ;
    USE SIGNAL ;
    PORT
      LAYER M5 ;
        RECT  7.728 14.928 7.752 15.12 ;
    END
  END e_i[6]
  PIN e_i[70]
    DIRECTION INPUT ;
    USE SIGNAL ;
    PORT
      LAYER M5 ;
        RECT  24 14.928 24.024 15.12 ;
    END
  END e_i[70]
  PIN e_i[71]
    DIRECTION INPUT ;
    USE SIGNAL ;
    PORT
      LAYER M5 ;
        RECT  24.24 14.928 24.264 15.12 ;
    END
  END e_i[71]
  PIN e_i[72]
    DIRECTION INPUT ;
    USE SIGNAL ;
    PORT
      LAYER M5 ;
        RECT  24.528 14.928 24.552 15.12 ;
    END
  END e_i[72]
  PIN e_i[73]
    DIRECTION INPUT ;
    USE SIGNAL ;
    PORT
      LAYER M5 ;
        RECT  24.768 14.928 24.792 15.12 ;
    END
  END e_i[73]
  PIN e_i[74]
    DIRECTION INPUT ;
    USE SIGNAL ;
    PORT
      LAYER M5 ;
        RECT  25.008 14.928 25.032 15.12 ;
    END
  END e_i[74]
  PIN e_i[75]
    DIRECTION INPUT ;
    USE SIGNAL ;
    PORT
      LAYER M5 ;
        RECT  25.296 14.928 25.32 15.12 ;
    END
  END e_i[75]
  PIN e_i[76]
    DIRECTION INPUT ;
    USE SIGNAL ;
    PORT
      LAYER M5 ;
        RECT  25.536 14.928 25.56 15.12 ;
    END
  END e_i[76]
  PIN e_i[77]
    DIRECTION INPUT ;
    USE SIGNAL ;
    PORT
      LAYER M5 ;
        RECT  25.776 14.928 25.8 15.12 ;
    END
  END e_i[77]
  PIN e_i[78]
    DIRECTION INPUT ;
    USE SIGNAL ;
    PORT
      LAYER M5 ;
        RECT  26.016 14.928 26.04 15.12 ;
    END
  END e_i[78]
  PIN e_i[79]
    DIRECTION INPUT ;
    USE SIGNAL ;
    PORT
      LAYER M5 ;
        RECT  26.304 14.928 26.328 15.12 ;
    END
  END e_i[79]
  PIN e_i[7]
    DIRECTION INPUT ;
    USE SIGNAL ;
    PORT
      LAYER M5 ;
        RECT  8.016 14.928 8.04 15.12 ;
    END
  END e_i[7]
  PIN e_i[80]
    DIRECTION INPUT ;
    USE SIGNAL ;
    PORT
      LAYER M5 ;
        RECT  26.544 14.928 26.568 15.12 ;
    END
  END e_i[80]
  PIN e_i[81]
    DIRECTION INPUT ;
    USE SIGNAL ;
    PORT
      LAYER M5 ;
        RECT  26.784 14.928 26.808 15.12 ;
    END
  END e_i[81]
  PIN e_i[82]
    DIRECTION INPUT ;
    USE SIGNAL ;
    PORT
      LAYER M5 ;
        RECT  27.072 14.928 27.096 15.12 ;
    END
  END e_i[82]
  PIN e_i[83]
    DIRECTION INPUT ;
    USE SIGNAL ;
    PORT
      LAYER M5 ;
        RECT  27.312 14.928 27.336 15.12 ;
    END
  END e_i[83]
  PIN e_i[84]
    DIRECTION INPUT ;
    USE SIGNAL ;
    PORT
      LAYER M5 ;
        RECT  27.552 14.928 27.576 15.12 ;
    END
  END e_i[84]
  PIN e_i[85]
    DIRECTION INPUT ;
    USE SIGNAL ;
    PORT
      LAYER M5 ;
        RECT  27.792 14.928 27.816 15.12 ;
    END
  END e_i[85]
  PIN e_i[86]
    DIRECTION INPUT ;
    USE SIGNAL ;
    PORT
      LAYER M5 ;
        RECT  28.08 14.928 28.104 15.12 ;
    END
  END e_i[86]
  PIN e_i[87]
    DIRECTION INPUT ;
    USE SIGNAL ;
    PORT
      LAYER M5 ;
        RECT  28.32 14.928 28.344 15.12 ;
    END
  END e_i[87]
  PIN e_i[88]
    DIRECTION INPUT ;
    USE SIGNAL ;
    PORT
      LAYER M5 ;
        RECT  28.56 14.928 28.584 15.12 ;
    END
  END e_i[88]
  PIN e_i[89]
    DIRECTION INPUT ;
    USE SIGNAL ;
    PORT
      LAYER M5 ;
        RECT  28.848 14.928 28.872 15.12 ;
    END
  END e_i[89]
  PIN e_i[8]
    DIRECTION INPUT ;
    USE SIGNAL ;
    PORT
      LAYER M5 ;
        RECT  8.256 14.928 8.28 15.12 ;
    END
  END e_i[8]
  PIN e_i[90]
    DIRECTION INPUT ;
    USE SIGNAL ;
    PORT
      LAYER M5 ;
        RECT  29.088 14.928 29.112 15.12 ;
    END
  END e_i[90]
  PIN e_i[91]
    DIRECTION INPUT ;
    USE SIGNAL ;
    PORT
      LAYER M5 ;
        RECT  29.328 14.928 29.352 15.12 ;
    END
  END e_i[91]
  PIN e_i[92]
    DIRECTION INPUT ;
    USE SIGNAL ;
    PORT
      LAYER M5 ;
        RECT  29.616 14.928 29.64 15.12 ;
    END
  END e_i[92]
  PIN e_i[93]
    DIRECTION INPUT ;
    USE SIGNAL ;
    PORT
      LAYER M5 ;
        RECT  29.856 14.928 29.88 15.12 ;
    END
  END e_i[93]
  PIN e_i[94]
    DIRECTION INPUT ;
    USE SIGNAL ;
    PORT
      LAYER M5 ;
        RECT  30.096 14.928 30.12 15.12 ;
    END
  END e_i[94]
  PIN e_i[95]
    DIRECTION INPUT ;
    USE SIGNAL ;
    PORT
      LAYER M5 ;
        RECT  30.336 14.928 30.36 15.12 ;
    END
  END e_i[95]
  PIN e_i[96]
    DIRECTION INPUT ;
    USE SIGNAL ;
    PORT
      LAYER M5 ;
        RECT  30.624 14.928 30.648 15.12 ;
    END
  END e_i[96]
  PIN e_i[97]
    DIRECTION INPUT ;
    USE SIGNAL ;
    PORT
      LAYER M5 ;
        RECT  30.864 14.928 30.888 15.12 ;
    END
  END e_i[97]
  PIN e_i[98]
    DIRECTION INPUT ;
    USE SIGNAL ;
    PORT
      LAYER M5 ;
        RECT  31.104 14.928 31.128 15.12 ;
    END
  END e_i[98]
  PIN e_i[99]
    DIRECTION INPUT ;
    USE SIGNAL ;
    PORT
      LAYER M5 ;
        RECT  31.392 14.928 31.416 15.12 ;
    END
  END e_i[99]
  PIN e_i[9]
    DIRECTION INPUT ;
    USE SIGNAL ;
    PORT
      LAYER M5 ;
        RECT  8.496 14.928 8.52 15.12 ;
    END
  END e_i[9]
  PIN e_o[0]
    DIRECTION OUTPUT ;
    USE SIGNAL ;
    PORT
      LAYER M5 ;
        RECT  6.192 0 6.216 0.192 ;
    END
  END e_o[0]
  PIN e_o[100]
    DIRECTION OUTPUT ;
    USE SIGNAL ;
    PORT
      LAYER M5 ;
        RECT  31.632 0 31.656 0.192 ;
    END
  END e_o[100]
  PIN e_o[101]
    DIRECTION OUTPUT ;
    USE SIGNAL ;
    PORT
      LAYER M5 ;
        RECT  31.872 0 31.896 0.192 ;
    END
  END e_o[101]
  PIN e_o[102]
    DIRECTION OUTPUT ;
    USE SIGNAL ;
    PORT
      LAYER M5 ;
        RECT  32.112 0 32.136 0.192 ;
    END
  END e_o[102]
  PIN e_o[103]
    DIRECTION OUTPUT ;
    USE SIGNAL ;
    PORT
      LAYER M5 ;
        RECT  32.4 0 32.424 0.192 ;
    END
  END e_o[103]
  PIN e_o[104]
    DIRECTION OUTPUT ;
    USE SIGNAL ;
    PORT
      LAYER M5 ;
        RECT  32.64 0 32.664 0.192 ;
    END
  END e_o[104]
  PIN e_o[105]
    DIRECTION OUTPUT ;
    USE SIGNAL ;
    PORT
      LAYER M5 ;
        RECT  32.88 0 32.904 0.192 ;
    END
  END e_o[105]
  PIN e_o[106]
    DIRECTION OUTPUT ;
    USE SIGNAL ;
    PORT
      LAYER M5 ;
        RECT  33.168 0 33.192 0.192 ;
    END
  END e_o[106]
  PIN e_o[107]
    DIRECTION OUTPUT ;
    USE SIGNAL ;
    PORT
      LAYER M5 ;
        RECT  33.408 0 33.432 0.192 ;
    END
  END e_o[107]
  PIN e_o[108]
    DIRECTION OUTPUT ;
    USE SIGNAL ;
    PORT
      LAYER M5 ;
        RECT  33.648 0 33.672 0.192 ;
    END
  END e_o[108]
  PIN e_o[109]
    DIRECTION OUTPUT ;
    USE SIGNAL ;
    PORT
      LAYER M5 ;
        RECT  33.936 0 33.96 0.192 ;
    END
  END e_o[109]
  PIN e_o[10]
    DIRECTION OUTPUT ;
    USE SIGNAL ;
    PORT
      LAYER M5 ;
        RECT  8.736 0 8.76 0.192 ;
    END
  END e_o[10]
  PIN e_o[110]
    DIRECTION OUTPUT ;
    USE SIGNAL ;
    PORT
      LAYER M5 ;
        RECT  34.176 0 34.2 0.192 ;
    END
  END e_o[110]
  PIN e_o[111]
    DIRECTION OUTPUT ;
    USE SIGNAL ;
    PORT
      LAYER M5 ;
        RECT  34.416 0 34.44 0.192 ;
    END
  END e_o[111]
  PIN e_o[112]
    DIRECTION OUTPUT ;
    USE SIGNAL ;
    PORT
      LAYER M5 ;
        RECT  34.656 0 34.68 0.192 ;
    END
  END e_o[112]
  PIN e_o[113]
    DIRECTION OUTPUT ;
    USE SIGNAL ;
    PORT
      LAYER M5 ;
        RECT  34.944 0 34.968 0.192 ;
    END
  END e_o[113]
  PIN e_o[114]
    DIRECTION OUTPUT ;
    USE SIGNAL ;
    PORT
      LAYER M5 ;
        RECT  35.184 0 35.208 0.192 ;
    END
  END e_o[114]
  PIN e_o[115]
    DIRECTION OUTPUT ;
    USE SIGNAL ;
    PORT
      LAYER M5 ;
        RECT  35.424 0 35.448 0.192 ;
    END
  END e_o[115]
  PIN e_o[116]
    DIRECTION OUTPUT ;
    USE SIGNAL ;
    PORT
      LAYER M5 ;
        RECT  35.712 0 35.736 0.192 ;
    END
  END e_o[116]
  PIN e_o[117]
    DIRECTION OUTPUT ;
    USE SIGNAL ;
    PORT
      LAYER M5 ;
        RECT  35.952 0 35.976 0.192 ;
    END
  END e_o[117]
  PIN e_o[118]
    DIRECTION OUTPUT ;
    USE SIGNAL ;
    PORT
      LAYER M5 ;
        RECT  36.192 0 36.216 0.192 ;
    END
  END e_o[118]
  PIN e_o[119]
    DIRECTION OUTPUT ;
    USE SIGNAL ;
    PORT
      LAYER M5 ;
        RECT  36.432 0 36.456 0.192 ;
    END
  END e_o[119]
  PIN e_o[11]
    DIRECTION OUTPUT ;
    USE SIGNAL ;
    PORT
      LAYER M5 ;
        RECT  9.024 0 9.048 0.192 ;
    END
  END e_o[11]
  PIN e_o[120]
    DIRECTION OUTPUT ;
    USE SIGNAL ;
    PORT
      LAYER M5 ;
        RECT  36.72 0 36.744 0.192 ;
    END
  END e_o[120]
  PIN e_o[121]
    DIRECTION OUTPUT ;
    USE SIGNAL ;
    PORT
      LAYER M5 ;
        RECT  36.96 0 36.984 0.192 ;
    END
  END e_o[121]
  PIN e_o[122]
    DIRECTION OUTPUT ;
    USE SIGNAL ;
    PORT
      LAYER M5 ;
        RECT  37.2 0 37.224 0.192 ;
    END
  END e_o[122]
  PIN e_o[123]
    DIRECTION OUTPUT ;
    USE SIGNAL ;
    PORT
      LAYER M5 ;
        RECT  37.488 0 37.512 0.192 ;
    END
  END e_o[123]
  PIN e_o[124]
    DIRECTION OUTPUT ;
    USE SIGNAL ;
    PORT
      LAYER M5 ;
        RECT  37.728 0 37.752 0.192 ;
    END
  END e_o[124]
  PIN e_o[125]
    DIRECTION OUTPUT ;
    USE SIGNAL ;
    PORT
      LAYER M5 ;
        RECT  37.968 0 37.992 0.192 ;
    END
  END e_o[125]
  PIN e_o[126]
    DIRECTION OUTPUT ;
    USE SIGNAL ;
    PORT
      LAYER M5 ;
        RECT  38.256 0 38.28 0.192 ;
    END
  END e_o[126]
  PIN e_o[127]
    DIRECTION OUTPUT ;
    USE SIGNAL ;
    PORT
      LAYER M5 ;
        RECT  38.496 0 38.52 0.192 ;
    END
  END e_o[127]
  PIN e_o[128]
    DIRECTION OUTPUT ;
    USE SIGNAL ;
    PORT
      LAYER M5 ;
        RECT  38.736 0 38.76 0.192 ;
    END
  END e_o[128]
  PIN e_o[129]
    DIRECTION OUTPUT ;
    USE SIGNAL ;
    PORT
      LAYER M5 ;
        RECT  38.976 0 39 0.192 ;
    END
  END e_o[129]
  PIN e_o[12]
    DIRECTION OUTPUT ;
    USE SIGNAL ;
    PORT
      LAYER M5 ;
        RECT  9.264 0 9.288 0.192 ;
    END
  END e_o[12]
  PIN e_o[130]
    DIRECTION OUTPUT ;
    USE SIGNAL ;
    PORT
      LAYER M5 ;
        RECT  39.264 0 39.288 0.192 ;
    END
  END e_o[130]
  PIN e_o[131]
    DIRECTION OUTPUT ;
    USE SIGNAL ;
    PORT
      LAYER M5 ;
        RECT  39.504 0 39.528 0.192 ;
    END
  END e_o[131]
  PIN e_o[132]
    DIRECTION OUTPUT ;
    USE SIGNAL ;
    PORT
      LAYER M5 ;
        RECT  39.744 0 39.768 0.192 ;
    END
  END e_o[132]
  PIN e_o[133]
    DIRECTION OUTPUT ;
    USE SIGNAL ;
    PORT
      LAYER M5 ;
        RECT  40.032 0 40.056 0.192 ;
    END
  END e_o[133]
  PIN e_o[134]
    DIRECTION OUTPUT ;
    USE SIGNAL ;
    PORT
      LAYER M5 ;
        RECT  40.272 0 40.296 0.192 ;
    END
  END e_o[134]
  PIN e_o[135]
    DIRECTION OUTPUT ;
    USE SIGNAL ;
    PORT
      LAYER M5 ;
        RECT  40.512 0 40.536 0.192 ;
    END
  END e_o[135]
  PIN e_o[136]
    DIRECTION OUTPUT ;
    USE SIGNAL ;
    PORT
      LAYER M5 ;
        RECT  40.752 0 40.776 0.192 ;
    END
  END e_o[136]
  PIN e_o[137]
    DIRECTION OUTPUT ;
    USE SIGNAL ;
    PORT
      LAYER M5 ;
        RECT  41.04 0 41.064 0.192 ;
    END
  END e_o[137]
  PIN e_o[138]
    DIRECTION OUTPUT ;
    USE SIGNAL ;
    PORT
      LAYER M5 ;
        RECT  41.28 0 41.304 0.192 ;
    END
  END e_o[138]
  PIN e_o[139]
    DIRECTION OUTPUT ;
    USE SIGNAL ;
    PORT
      LAYER M5 ;
        RECT  41.52 0 41.544 0.192 ;
    END
  END e_o[139]
  PIN e_o[13]
    DIRECTION OUTPUT ;
    USE SIGNAL ;
    PORT
      LAYER M5 ;
        RECT  9.504 0 9.528 0.192 ;
    END
  END e_o[13]
  PIN e_o[140]
    DIRECTION OUTPUT ;
    USE SIGNAL ;
    PORT
      LAYER M5 ;
        RECT  41.808 0 41.832 0.192 ;
    END
  END e_o[140]
  PIN e_o[141]
    DIRECTION OUTPUT ;
    USE SIGNAL ;
    PORT
      LAYER M5 ;
        RECT  42.048 0 42.072 0.192 ;
    END
  END e_o[141]
  PIN e_o[142]
    DIRECTION OUTPUT ;
    USE SIGNAL ;
    PORT
      LAYER M5 ;
        RECT  42.288 0 42.312 0.192 ;
    END
  END e_o[142]
  PIN e_o[143]
    DIRECTION OUTPUT ;
    USE SIGNAL ;
    PORT
      LAYER M5 ;
        RECT  42.576 0 42.6 0.192 ;
    END
  END e_o[143]
  PIN e_o[144]
    DIRECTION OUTPUT ;
    USE SIGNAL ;
    PORT
      LAYER M5 ;
        RECT  42.816 0 42.84 0.192 ;
    END
  END e_o[144]
  PIN e_o[145]
    DIRECTION OUTPUT ;
    USE SIGNAL ;
    PORT
      LAYER M5 ;
        RECT  43.056 0 43.08 0.192 ;
    END
  END e_o[145]
  PIN e_o[146]
    DIRECTION OUTPUT ;
    USE SIGNAL ;
    PORT
      LAYER M5 ;
        RECT  43.296 0 43.32 0.192 ;
    END
  END e_o[146]
  PIN e_o[147]
    DIRECTION OUTPUT ;
    USE SIGNAL ;
    PORT
      LAYER M5 ;
        RECT  43.584 0 43.608 0.192 ;
    END
  END e_o[147]
  PIN e_o[148]
    DIRECTION OUTPUT ;
    USE SIGNAL ;
    PORT
      LAYER M5 ;
        RECT  43.824 0 43.848 0.192 ;
    END
  END e_o[148]
  PIN e_o[149]
    DIRECTION OUTPUT ;
    USE SIGNAL ;
    PORT
      LAYER M5 ;
        RECT  44.064 0 44.088 0.192 ;
    END
  END e_o[149]
  PIN e_o[14]
    DIRECTION OUTPUT ;
    USE SIGNAL ;
    PORT
      LAYER M5 ;
        RECT  9.792 0 9.816 0.192 ;
    END
  END e_o[14]
  PIN e_o[150]
    DIRECTION OUTPUT ;
    USE SIGNAL ;
    PORT
      LAYER M5 ;
        RECT  44.352 0 44.376 0.192 ;
    END
  END e_o[150]
  PIN e_o[151]
    DIRECTION OUTPUT ;
    USE SIGNAL ;
    PORT
      LAYER M5 ;
        RECT  44.592 0 44.616 0.192 ;
    END
  END e_o[151]
  PIN e_o[152]
    DIRECTION OUTPUT ;
    USE SIGNAL ;
    PORT
      LAYER M5 ;
        RECT  44.832 0 44.856 0.192 ;
    END
  END e_o[152]
  PIN e_o[153]
    DIRECTION OUTPUT ;
    USE SIGNAL ;
    PORT
      LAYER M5 ;
        RECT  45.072 0 45.096 0.192 ;
    END
  END e_o[153]
  PIN e_o[154]
    DIRECTION OUTPUT ;
    USE SIGNAL ;
    PORT
      LAYER M5 ;
        RECT  45.36 0 45.384 0.192 ;
    END
  END e_o[154]
  PIN e_o[155]
    DIRECTION OUTPUT ;
    USE SIGNAL ;
    PORT
      LAYER M5 ;
        RECT  45.6 0 45.624 0.192 ;
    END
  END e_o[155]
  PIN e_o[156]
    DIRECTION OUTPUT ;
    USE SIGNAL ;
    PORT
      LAYER M5 ;
        RECT  45.84 0 45.864 0.192 ;
    END
  END e_o[156]
  PIN e_o[157]
    DIRECTION OUTPUT ;
    USE SIGNAL ;
    PORT
      LAYER M5 ;
        RECT  46.128 0 46.152 0.192 ;
    END
  END e_o[157]
  PIN e_o[158]
    DIRECTION OUTPUT ;
    USE SIGNAL ;
    PORT
      LAYER M5 ;
        RECT  46.368 0 46.392 0.192 ;
    END
  END e_o[158]
  PIN e_o[159]
    DIRECTION OUTPUT ;
    USE SIGNAL ;
    PORT
      LAYER M5 ;
        RECT  46.608 0 46.632 0.192 ;
    END
  END e_o[159]
  PIN e_o[15]
    DIRECTION OUTPUT ;
    USE SIGNAL ;
    PORT
      LAYER M5 ;
        RECT  10.032 0 10.056 0.192 ;
    END
  END e_o[15]
  PIN e_o[160]
    DIRECTION OUTPUT ;
    USE SIGNAL ;
    PORT
      LAYER M5 ;
        RECT  46.896 0 46.92 0.192 ;
    END
  END e_o[160]
  PIN e_o[161]
    DIRECTION OUTPUT ;
    USE SIGNAL ;
    PORT
      LAYER M5 ;
        RECT  47.136 0 47.16 0.192 ;
    END
  END e_o[161]
  PIN e_o[162]
    DIRECTION OUTPUT ;
    USE SIGNAL ;
    PORT
      LAYER M5 ;
        RECT  47.376 0 47.4 0.192 ;
    END
  END e_o[162]
  PIN e_o[163]
    DIRECTION OUTPUT ;
    USE SIGNAL ;
    PORT
      LAYER M5 ;
        RECT  47.616 0 47.64 0.192 ;
    END
  END e_o[163]
  PIN e_o[164]
    DIRECTION OUTPUT ;
    USE SIGNAL ;
    PORT
      LAYER M5 ;
        RECT  47.904 0 47.928 0.192 ;
    END
  END e_o[164]
  PIN e_o[165]
    DIRECTION OUTPUT ;
    USE SIGNAL ;
    PORT
      LAYER M5 ;
        RECT  48.144 0 48.168 0.192 ;
    END
  END e_o[165]
  PIN e_o[166]
    DIRECTION OUTPUT ;
    USE SIGNAL ;
    PORT
      LAYER M5 ;
        RECT  48.384 0 48.408 0.192 ;
    END
  END e_o[166]
  PIN e_o[167]
    DIRECTION OUTPUT ;
    USE SIGNAL ;
    PORT
      LAYER M5 ;
        RECT  48.672 0 48.696 0.192 ;
    END
  END e_o[167]
  PIN e_o[168]
    DIRECTION OUTPUT ;
    USE SIGNAL ;
    PORT
      LAYER M5 ;
        RECT  48.912 0 48.936 0.192 ;
    END
  END e_o[168]
  PIN e_o[169]
    DIRECTION OUTPUT ;
    USE SIGNAL ;
    PORT
      LAYER M5 ;
        RECT  49.152 0 49.176 0.192 ;
    END
  END e_o[169]
  PIN e_o[16]
    DIRECTION OUTPUT ;
    USE SIGNAL ;
    PORT
      LAYER M5 ;
        RECT  10.272 0 10.296 0.192 ;
    END
  END e_o[16]
  PIN e_o[170]
    DIRECTION OUTPUT ;
    USE SIGNAL ;
    PORT
      LAYER M5 ;
        RECT  49.392 0 49.416 0.192 ;
    END
  END e_o[170]
  PIN e_o[171]
    DIRECTION OUTPUT ;
    USE SIGNAL ;
    PORT
      LAYER M5 ;
        RECT  49.68 0 49.704 0.192 ;
    END
  END e_o[171]
  PIN e_o[172]
    DIRECTION OUTPUT ;
    USE SIGNAL ;
    PORT
      LAYER M5 ;
        RECT  49.92 0 49.944 0.192 ;
    END
  END e_o[172]
  PIN e_o[173]
    DIRECTION OUTPUT ;
    USE SIGNAL ;
    PORT
      LAYER M5 ;
        RECT  50.16 0 50.184 0.192 ;
    END
  END e_o[173]
  PIN e_o[174]
    DIRECTION OUTPUT ;
    USE SIGNAL ;
    PORT
      LAYER M5 ;
        RECT  50.448 0 50.472 0.192 ;
    END
  END e_o[174]
  PIN e_o[175]
    DIRECTION OUTPUT ;
    USE SIGNAL ;
    PORT
      LAYER M5 ;
        RECT  50.688 0 50.712 0.192 ;
    END
  END e_o[175]
  PIN e_o[176]
    DIRECTION OUTPUT ;
    USE SIGNAL ;
    PORT
      LAYER M5 ;
        RECT  50.928 0 50.952 0.192 ;
    END
  END e_o[176]
  PIN e_o[177]
    DIRECTION OUTPUT ;
    USE SIGNAL ;
    PORT
      LAYER M5 ;
        RECT  51.216 0 51.24 0.192 ;
    END
  END e_o[177]
  PIN e_o[178]
    DIRECTION OUTPUT ;
    USE SIGNAL ;
    PORT
      LAYER M5 ;
        RECT  51.456 0 51.48 0.192 ;
    END
  END e_o[178]
  PIN e_o[179]
    DIRECTION OUTPUT ;
    USE SIGNAL ;
    PORT
      LAYER M5 ;
        RECT  51.696 0 51.72 0.192 ;
    END
  END e_o[179]
  PIN e_o[17]
    DIRECTION OUTPUT ;
    USE SIGNAL ;
    PORT
      LAYER M5 ;
        RECT  10.512 0 10.536 0.192 ;
    END
  END e_o[17]
  PIN e_o[180]
    DIRECTION OUTPUT ;
    USE SIGNAL ;
    PORT
      LAYER M5 ;
        RECT  51.936 0 51.96 0.192 ;
    END
  END e_o[180]
  PIN e_o[181]
    DIRECTION OUTPUT ;
    USE SIGNAL ;
    PORT
      LAYER M5 ;
        RECT  52.224 0 52.248 0.192 ;
    END
  END e_o[181]
  PIN e_o[182]
    DIRECTION OUTPUT ;
    USE SIGNAL ;
    PORT
      LAYER M5 ;
        RECT  52.464 0 52.488 0.192 ;
    END
  END e_o[182]
  PIN e_o[183]
    DIRECTION OUTPUT ;
    USE SIGNAL ;
    PORT
      LAYER M5 ;
        RECT  52.704 0 52.728 0.192 ;
    END
  END e_o[183]
  PIN e_o[184]
    DIRECTION OUTPUT ;
    USE SIGNAL ;
    PORT
      LAYER M5 ;
        RECT  52.992 0 53.016 0.192 ;
    END
  END e_o[184]
  PIN e_o[185]
    DIRECTION OUTPUT ;
    USE SIGNAL ;
    PORT
      LAYER M5 ;
        RECT  53.232 0 53.256 0.192 ;
    END
  END e_o[185]
  PIN e_o[186]
    DIRECTION OUTPUT ;
    USE SIGNAL ;
    PORT
      LAYER M5 ;
        RECT  53.472 0 53.496 0.192 ;
    END
  END e_o[186]
  PIN e_o[187]
    DIRECTION OUTPUT ;
    USE SIGNAL ;
    PORT
      LAYER M5 ;
        RECT  53.712 0 53.736 0.192 ;
    END
  END e_o[187]
  PIN e_o[188]
    DIRECTION OUTPUT ;
    USE SIGNAL ;
    PORT
      LAYER M5 ;
        RECT  54 0 54.024 0.192 ;
    END
  END e_o[188]
  PIN e_o[189]
    DIRECTION OUTPUT ;
    USE SIGNAL ;
    PORT
      LAYER M5 ;
        RECT  54.24 0 54.264 0.192 ;
    END
  END e_o[189]
  PIN e_o[18]
    DIRECTION OUTPUT ;
    USE SIGNAL ;
    PORT
      LAYER M5 ;
        RECT  10.8 0 10.824 0.192 ;
    END
  END e_o[18]
  PIN e_o[190]
    DIRECTION OUTPUT ;
    USE SIGNAL ;
    PORT
      LAYER M5 ;
        RECT  54.48 0 54.504 0.192 ;
    END
  END e_o[190]
  PIN e_o[191]
    DIRECTION OUTPUT ;
    USE SIGNAL ;
    PORT
      LAYER M5 ;
        RECT  54.768 0 54.792 0.192 ;
    END
  END e_o[191]
  PIN e_o[192]
    DIRECTION OUTPUT ;
    USE SIGNAL ;
    PORT
      LAYER M5 ;
        RECT  55.008 0 55.032 0.192 ;
    END
  END e_o[192]
  PIN e_o[193]
    DIRECTION OUTPUT ;
    USE SIGNAL ;
    PORT
      LAYER M5 ;
        RECT  55.248 0 55.272 0.192 ;
    END
  END e_o[193]
  PIN e_o[194]
    DIRECTION OUTPUT ;
    USE SIGNAL ;
    PORT
      LAYER M5 ;
        RECT  55.536 0 55.56 0.192 ;
    END
  END e_o[194]
  PIN e_o[195]
    DIRECTION OUTPUT ;
    USE SIGNAL ;
    PORT
      LAYER M5 ;
        RECT  55.776 0 55.8 0.192 ;
    END
  END e_o[195]
  PIN e_o[196]
    DIRECTION OUTPUT ;
    USE SIGNAL ;
    PORT
      LAYER M5 ;
        RECT  56.016 0 56.04 0.192 ;
    END
  END e_o[196]
  PIN e_o[197]
    DIRECTION OUTPUT ;
    USE SIGNAL ;
    PORT
      LAYER M5 ;
        RECT  56.256 0 56.28 0.192 ;
    END
  END e_o[197]
  PIN e_o[198]
    DIRECTION OUTPUT ;
    USE SIGNAL ;
    PORT
      LAYER M5 ;
        RECT  56.544 0 56.568 0.192 ;
    END
  END e_o[198]
  PIN e_o[199]
    DIRECTION OUTPUT ;
    USE SIGNAL ;
    PORT
      LAYER M5 ;
        RECT  56.784 0 56.808 0.192 ;
    END
  END e_o[199]
  PIN e_o[19]
    DIRECTION OUTPUT ;
    USE SIGNAL ;
    PORT
      LAYER M5 ;
        RECT  11.04 0 11.064 0.192 ;
    END
  END e_o[19]
  PIN e_o[1]
    DIRECTION OUTPUT ;
    USE SIGNAL ;
    PORT
      LAYER M5 ;
        RECT  6.48 0 6.504 0.192 ;
    END
  END e_o[1]
  PIN e_o[200]
    DIRECTION OUTPUT ;
    USE SIGNAL ;
    PORT
      LAYER M5 ;
        RECT  57.024 0 57.048 0.192 ;
    END
  END e_o[200]
  PIN e_o[201]
    DIRECTION OUTPUT ;
    USE SIGNAL ;
    PORT
      LAYER M5 ;
        RECT  57.312 0 57.336 0.192 ;
    END
  END e_o[201]
  PIN e_o[202]
    DIRECTION OUTPUT ;
    USE SIGNAL ;
    PORT
      LAYER M5 ;
        RECT  57.552 0 57.576 0.192 ;
    END
  END e_o[202]
  PIN e_o[203]
    DIRECTION OUTPUT ;
    USE SIGNAL ;
    PORT
      LAYER M5 ;
        RECT  57.792 0 57.816 0.192 ;
    END
  END e_o[203]
  PIN e_o[204]
    DIRECTION OUTPUT ;
    USE SIGNAL ;
    PORT
      LAYER M5 ;
        RECT  58.032 0 58.056 0.192 ;
    END
  END e_o[204]
  PIN e_o[205]
    DIRECTION OUTPUT ;
    USE SIGNAL ;
    PORT
      LAYER M5 ;
        RECT  58.32 0 58.344 0.192 ;
    END
  END e_o[205]
  PIN e_o[206]
    DIRECTION OUTPUT ;
    USE SIGNAL ;
    PORT
      LAYER M5 ;
        RECT  58.56 0 58.584 0.192 ;
    END
  END e_o[206]
  PIN e_o[207]
    DIRECTION OUTPUT ;
    USE SIGNAL ;
    PORT
      LAYER M5 ;
        RECT  58.8 0 58.824 0.192 ;
    END
  END e_o[207]
  PIN e_o[208]
    DIRECTION OUTPUT ;
    USE SIGNAL ;
    PORT
      LAYER M5 ;
        RECT  59.088 0 59.112 0.192 ;
    END
  END e_o[208]
  PIN e_o[209]
    DIRECTION OUTPUT ;
    USE SIGNAL ;
    PORT
      LAYER M5 ;
        RECT  59.328 0 59.352 0.192 ;
    END
  END e_o[209]
  PIN e_o[20]
    DIRECTION OUTPUT ;
    USE SIGNAL ;
    PORT
      LAYER M5 ;
        RECT  11.28 0 11.304 0.192 ;
    END
  END e_o[20]
  PIN e_o[210]
    DIRECTION OUTPUT ;
    USE SIGNAL ;
    PORT
      LAYER M5 ;
        RECT  59.568 0 59.592 0.192 ;
    END
  END e_o[210]
  PIN e_o[211]
    DIRECTION OUTPUT ;
    USE SIGNAL ;
    PORT
      LAYER M5 ;
        RECT  59.856 0 59.88 0.192 ;
    END
  END e_o[211]
  PIN e_o[212]
    DIRECTION OUTPUT ;
    USE SIGNAL ;
    PORT
      LAYER M5 ;
        RECT  60.096 0 60.12 0.192 ;
    END
  END e_o[212]
  PIN e_o[213]
    DIRECTION OUTPUT ;
    USE SIGNAL ;
    PORT
      LAYER M5 ;
        RECT  60.336 0 60.36 0.192 ;
    END
  END e_o[213]
  PIN e_o[214]
    DIRECTION OUTPUT ;
    USE SIGNAL ;
    PORT
      LAYER M5 ;
        RECT  60.576 0 60.6 0.192 ;
    END
  END e_o[214]
  PIN e_o[215]
    DIRECTION OUTPUT ;
    USE SIGNAL ;
    PORT
      LAYER M5 ;
        RECT  60.864 0 60.888 0.192 ;
    END
  END e_o[215]
  PIN e_o[216]
    DIRECTION OUTPUT ;
    USE SIGNAL ;
    PORT
      LAYER M5 ;
        RECT  61.104 0 61.128 0.192 ;
    END
  END e_o[216]
  PIN e_o[217]
    DIRECTION OUTPUT ;
    USE SIGNAL ;
    PORT
      LAYER M5 ;
        RECT  61.344 0 61.368 0.192 ;
    END
  END e_o[217]
  PIN e_o[218]
    DIRECTION OUTPUT ;
    USE SIGNAL ;
    PORT
      LAYER M5 ;
        RECT  61.632 0 61.656 0.192 ;
    END
  END e_o[218]
  PIN e_o[219]
    DIRECTION OUTPUT ;
    USE SIGNAL ;
    PORT
      LAYER M5 ;
        RECT  61.872 0 61.896 0.192 ;
    END
  END e_o[219]
  PIN e_o[21]
    DIRECTION OUTPUT ;
    USE SIGNAL ;
    PORT
      LAYER M5 ;
        RECT  11.568 0 11.592 0.192 ;
    END
  END e_o[21]
  PIN e_o[220]
    DIRECTION OUTPUT ;
    USE SIGNAL ;
    PORT
      LAYER M5 ;
        RECT  62.112 0 62.136 0.192 ;
    END
  END e_o[220]
  PIN e_o[221]
    DIRECTION OUTPUT ;
    USE SIGNAL ;
    PORT
      LAYER M5 ;
        RECT  62.352 0 62.376 0.192 ;
    END
  END e_o[221]
  PIN e_o[222]
    DIRECTION OUTPUT ;
    USE SIGNAL ;
    PORT
      LAYER M5 ;
        RECT  62.64 0 62.664 0.192 ;
    END
  END e_o[222]
  PIN e_o[223]
    DIRECTION OUTPUT ;
    USE SIGNAL ;
    PORT
      LAYER M5 ;
        RECT  62.88 0 62.904 0.192 ;
    END
  END e_o[223]
  PIN e_o[224]
    DIRECTION OUTPUT ;
    USE SIGNAL ;
    PORT
      LAYER M5 ;
        RECT  63.12 0 63.144 0.192 ;
    END
  END e_o[224]
  PIN e_o[225]
    DIRECTION OUTPUT ;
    USE SIGNAL ;
    PORT
      LAYER M5 ;
        RECT  63.408 0 63.432 0.192 ;
    END
  END e_o[225]
  PIN e_o[226]
    DIRECTION OUTPUT ;
    USE SIGNAL ;
    PORT
      LAYER M5 ;
        RECT  63.648 0 63.672 0.192 ;
    END
  END e_o[226]
  PIN e_o[227]
    DIRECTION OUTPUT ;
    USE SIGNAL ;
    PORT
      LAYER M5 ;
        RECT  63.888 0 63.912 0.192 ;
    END
  END e_o[227]
  PIN e_o[228]
    DIRECTION OUTPUT ;
    USE SIGNAL ;
    PORT
      LAYER M5 ;
        RECT  64.176 0 64.2 0.192 ;
    END
  END e_o[228]
  PIN e_o[229]
    DIRECTION OUTPUT ;
    USE SIGNAL ;
    PORT
      LAYER M5 ;
        RECT  64.416 0 64.44 0.192 ;
    END
  END e_o[229]
  PIN e_o[22]
    DIRECTION OUTPUT ;
    USE SIGNAL ;
    PORT
      LAYER M5 ;
        RECT  11.808 0 11.832 0.192 ;
    END
  END e_o[22]
  PIN e_o[230]
    DIRECTION OUTPUT ;
    USE SIGNAL ;
    PORT
      LAYER M5 ;
        RECT  64.656 0 64.68 0.192 ;
    END
  END e_o[230]
  PIN e_o[231]
    DIRECTION OUTPUT ;
    USE SIGNAL ;
    PORT
      LAYER M5 ;
        RECT  64.896 0 64.92 0.192 ;
    END
  END e_o[231]
  PIN e_o[232]
    DIRECTION OUTPUT ;
    USE SIGNAL ;
    PORT
      LAYER M5 ;
        RECT  65.184 0 65.208 0.192 ;
    END
  END e_o[232]
  PIN e_o[233]
    DIRECTION OUTPUT ;
    USE SIGNAL ;
    PORT
      LAYER M5 ;
        RECT  65.424 0 65.448 0.192 ;
    END
  END e_o[233]
  PIN e_o[234]
    DIRECTION OUTPUT ;
    USE SIGNAL ;
    PORT
      LAYER M5 ;
        RECT  65.664 0 65.688 0.192 ;
    END
  END e_o[234]
  PIN e_o[235]
    DIRECTION OUTPUT ;
    USE SIGNAL ;
    PORT
      LAYER M5 ;
        RECT  65.952 0 65.976 0.192 ;
    END
  END e_o[235]
  PIN e_o[236]
    DIRECTION OUTPUT ;
    USE SIGNAL ;
    PORT
      LAYER M5 ;
        RECT  66.192 0 66.216 0.192 ;
    END
  END e_o[236]
  PIN e_o[237]
    DIRECTION OUTPUT ;
    USE SIGNAL ;
    PORT
      LAYER M5 ;
        RECT  66.432 0 66.456 0.192 ;
    END
  END e_o[237]
  PIN e_o[238]
    DIRECTION OUTPUT ;
    USE SIGNAL ;
    PORT
      LAYER M5 ;
        RECT  66.672 0 66.696 0.192 ;
    END
  END e_o[238]
  PIN e_o[239]
    DIRECTION OUTPUT ;
    USE SIGNAL ;
    PORT
      LAYER M5 ;
        RECT  66.96 0 66.984 0.192 ;
    END
  END e_o[239]
  PIN e_o[23]
    DIRECTION OUTPUT ;
    USE SIGNAL ;
    PORT
      LAYER M5 ;
        RECT  12.048 0 12.072 0.192 ;
    END
  END e_o[23]
  PIN e_o[240]
    DIRECTION OUTPUT ;
    USE SIGNAL ;
    PORT
      LAYER M5 ;
        RECT  67.2 0 67.224 0.192 ;
    END
  END e_o[240]
  PIN e_o[241]
    DIRECTION OUTPUT ;
    USE SIGNAL ;
    PORT
      LAYER M5 ;
        RECT  67.44 0 67.464 0.192 ;
    END
  END e_o[241]
  PIN e_o[242]
    DIRECTION OUTPUT ;
    USE SIGNAL ;
    PORT
      LAYER M5 ;
        RECT  67.728 0 67.752 0.192 ;
    END
  END e_o[242]
  PIN e_o[243]
    DIRECTION OUTPUT ;
    USE SIGNAL ;
    PORT
      LAYER M5 ;
        RECT  67.968 0 67.992 0.192 ;
    END
  END e_o[243]
  PIN e_o[244]
    DIRECTION OUTPUT ;
    USE SIGNAL ;
    PORT
      LAYER M5 ;
        RECT  68.208 0 68.232 0.192 ;
    END
  END e_o[244]
  PIN e_o[245]
    DIRECTION OUTPUT ;
    USE SIGNAL ;
    PORT
      LAYER M5 ;
        RECT  68.496 0 68.52 0.192 ;
    END
  END e_o[245]
  PIN e_o[246]
    DIRECTION OUTPUT ;
    USE SIGNAL ;
    PORT
      LAYER M5 ;
        RECT  68.736 0 68.76 0.192 ;
    END
  END e_o[246]
  PIN e_o[247]
    DIRECTION OUTPUT ;
    USE SIGNAL ;
    PORT
      LAYER M5 ;
        RECT  68.976 0 69 0.192 ;
    END
  END e_o[247]
  PIN e_o[248]
    DIRECTION OUTPUT ;
    USE SIGNAL ;
    PORT
      LAYER M5 ;
        RECT  69.216 0 69.24 0.192 ;
    END
  END e_o[248]
  PIN e_o[249]
    DIRECTION OUTPUT ;
    USE SIGNAL ;
    PORT
      LAYER M5 ;
        RECT  69.504 0 69.528 0.192 ;
    END
  END e_o[249]
  PIN e_o[24]
    DIRECTION OUTPUT ;
    USE SIGNAL ;
    PORT
      LAYER M5 ;
        RECT  12.336 0 12.36 0.192 ;
    END
  END e_o[24]
  PIN e_o[250]
    DIRECTION OUTPUT ;
    USE SIGNAL ;
    PORT
      LAYER M5 ;
        RECT  69.744 0 69.768 0.192 ;
    END
  END e_o[250]
  PIN e_o[251]
    DIRECTION OUTPUT ;
    USE SIGNAL ;
    PORT
      LAYER M5 ;
        RECT  69.984 0 70.008 0.192 ;
    END
  END e_o[251]
  PIN e_o[252]
    DIRECTION OUTPUT ;
    USE SIGNAL ;
    PORT
      LAYER M5 ;
        RECT  70.272 0 70.296 0.192 ;
    END
  END e_o[252]
  PIN e_o[253]
    DIRECTION OUTPUT ;
    USE SIGNAL ;
    PORT
      LAYER M5 ;
        RECT  70.512 0 70.536 0.192 ;
    END
  END e_o[253]
  PIN e_o[254]
    DIRECTION OUTPUT ;
    USE SIGNAL ;
    PORT
      LAYER M5 ;
        RECT  70.752 0 70.776 0.192 ;
    END
  END e_o[254]
  PIN e_o[255]
    DIRECTION OUTPUT ;
    USE SIGNAL ;
    PORT
      LAYER M5 ;
        RECT  70.992 0 71.016 0.192 ;
    END
  END e_o[255]
  PIN e_o[256]
    DIRECTION OUTPUT ;
    USE SIGNAL ;
    PORT
      LAYER M5 ;
        RECT  71.28 0 71.304 0.192 ;
    END
  END e_o[256]
  PIN e_o[257]
    DIRECTION OUTPUT ;
    USE SIGNAL ;
    PORT
      LAYER M5 ;
        RECT  71.52 0 71.544 0.192 ;
    END
  END e_o[257]
  PIN e_o[258]
    DIRECTION OUTPUT ;
    USE SIGNAL ;
    PORT
      LAYER M5 ;
        RECT  71.76 0 71.784 0.192 ;
    END
  END e_o[258]
  PIN e_o[259]
    DIRECTION OUTPUT ;
    USE SIGNAL ;
    PORT
      LAYER M5 ;
        RECT  72.048 0 72.072 0.192 ;
    END
  END e_o[259]
  PIN e_o[25]
    DIRECTION OUTPUT ;
    USE SIGNAL ;
    PORT
      LAYER M5 ;
        RECT  12.576 0 12.6 0.192 ;
    END
  END e_o[25]
  PIN e_o[260]
    DIRECTION OUTPUT ;
    USE SIGNAL ;
    PORT
      LAYER M5 ;
        RECT  72.288 0 72.312 0.192 ;
    END
  END e_o[260]
  PIN e_o[261]
    DIRECTION OUTPUT ;
    USE SIGNAL ;
    PORT
      LAYER M5 ;
        RECT  72.528 0 72.552 0.192 ;
    END
  END e_o[261]
  PIN e_o[262]
    DIRECTION OUTPUT ;
    USE SIGNAL ;
    PORT
      LAYER M5 ;
        RECT  72.816 0 72.84 0.192 ;
    END
  END e_o[262]
  PIN e_o[263]
    DIRECTION OUTPUT ;
    USE SIGNAL ;
    PORT
      LAYER M5 ;
        RECT  73.056 0 73.08 0.192 ;
    END
  END e_o[263]
  PIN e_o[264]
    DIRECTION OUTPUT ;
    USE SIGNAL ;
    PORT
      LAYER M5 ;
        RECT  73.296 0 73.32 0.192 ;
    END
  END e_o[264]
  PIN e_o[265]
    DIRECTION OUTPUT ;
    USE SIGNAL ;
    PORT
      LAYER M5 ;
        RECT  73.536 0 73.56 0.192 ;
    END
  END e_o[265]
  PIN e_o[266]
    DIRECTION OUTPUT ;
    USE SIGNAL ;
    PORT
      LAYER M5 ;
        RECT  73.824 0 73.848 0.192 ;
    END
  END e_o[266]
  PIN e_o[267]
    DIRECTION OUTPUT ;
    USE SIGNAL ;
    PORT
      LAYER M5 ;
        RECT  74.064 0 74.088 0.192 ;
    END
  END e_o[267]
  PIN e_o[268]
    DIRECTION OUTPUT ;
    USE SIGNAL ;
    PORT
      LAYER M5 ;
        RECT  74.304 0 74.328 0.192 ;
    END
  END e_o[268]
  PIN e_o[269]
    DIRECTION OUTPUT ;
    USE SIGNAL ;
    PORT
      LAYER M5 ;
        RECT  74.592 0 74.616 0.192 ;
    END
  END e_o[269]
  PIN e_o[26]
    DIRECTION OUTPUT ;
    USE SIGNAL ;
    PORT
      LAYER M5 ;
        RECT  12.816 0 12.84 0.192 ;
    END
  END e_o[26]
  PIN e_o[270]
    DIRECTION OUTPUT ;
    USE SIGNAL ;
    PORT
      LAYER M5 ;
        RECT  74.832 0 74.856 0.192 ;
    END
  END e_o[270]
  PIN e_o[271]
    DIRECTION OUTPUT ;
    USE SIGNAL ;
    PORT
      LAYER M5 ;
        RECT  75.072 0 75.096 0.192 ;
    END
  END e_o[271]
  PIN e_o[272]
    DIRECTION OUTPUT ;
    USE SIGNAL ;
    PORT
      LAYER M5 ;
        RECT  75.312 0 75.336 0.192 ;
    END
  END e_o[272]
  PIN e_o[273]
    DIRECTION OUTPUT ;
    USE SIGNAL ;
    PORT
      LAYER M5 ;
        RECT  75.6 0 75.624 0.192 ;
    END
  END e_o[273]
  PIN e_o[274]
    DIRECTION OUTPUT ;
    USE SIGNAL ;
    PORT
      LAYER M5 ;
        RECT  75.84 0 75.864 0.192 ;
    END
  END e_o[274]
  PIN e_o[275]
    DIRECTION OUTPUT ;
    USE SIGNAL ;
    PORT
      LAYER M5 ;
        RECT  76.08 0 76.104 0.192 ;
    END
  END e_o[275]
  PIN e_o[276]
    DIRECTION OUTPUT ;
    USE SIGNAL ;
    PORT
      LAYER M5 ;
        RECT  76.368 0 76.392 0.192 ;
    END
  END e_o[276]
  PIN e_o[277]
    DIRECTION OUTPUT ;
    USE SIGNAL ;
    PORT
      LAYER M5 ;
        RECT  76.608 0 76.632 0.192 ;
    END
  END e_o[277]
  PIN e_o[278]
    DIRECTION OUTPUT ;
    USE SIGNAL ;
    PORT
      LAYER M5 ;
        RECT  76.848 0 76.872 0.192 ;
    END
  END e_o[278]
  PIN e_o[279]
    DIRECTION OUTPUT ;
    USE SIGNAL ;
    PORT
      LAYER M5 ;
        RECT  77.136 0 77.16 0.192 ;
    END
  END e_o[279]
  PIN e_o[27]
    DIRECTION OUTPUT ;
    USE SIGNAL ;
    PORT
      LAYER M5 ;
        RECT  13.056 0 13.08 0.192 ;
    END
  END e_o[27]
  PIN e_o[280]
    DIRECTION OUTPUT ;
    USE SIGNAL ;
    PORT
      LAYER M5 ;
        RECT  77.376 0 77.4 0.192 ;
    END
  END e_o[280]
  PIN e_o[281]
    DIRECTION OUTPUT ;
    USE SIGNAL ;
    PORT
      LAYER M5 ;
        RECT  77.616 0 77.64 0.192 ;
    END
  END e_o[281]
  PIN e_o[282]
    DIRECTION OUTPUT ;
    USE SIGNAL ;
    PORT
      LAYER M5 ;
        RECT  77.856 0 77.88 0.192 ;
    END
  END e_o[282]
  PIN e_o[283]
    DIRECTION OUTPUT ;
    USE SIGNAL ;
    PORT
      LAYER M5 ;
        RECT  78.144 0 78.168 0.192 ;
    END
  END e_o[283]
  PIN e_o[284]
    DIRECTION OUTPUT ;
    USE SIGNAL ;
    PORT
      LAYER M5 ;
        RECT  78.384 0 78.408 0.192 ;
    END
  END e_o[284]
  PIN e_o[285]
    DIRECTION OUTPUT ;
    USE SIGNAL ;
    PORT
      LAYER M5 ;
        RECT  78.624 0 78.648 0.192 ;
    END
  END e_o[285]
  PIN e_o[286]
    DIRECTION OUTPUT ;
    USE SIGNAL ;
    PORT
      LAYER M5 ;
        RECT  78.912 0 78.936 0.192 ;
    END
  END e_o[286]
  PIN e_o[287]
    DIRECTION OUTPUT ;
    USE SIGNAL ;
    PORT
      LAYER M5 ;
        RECT  79.152 0 79.176 0.192 ;
    END
  END e_o[287]
  PIN e_o[288]
    DIRECTION OUTPUT ;
    USE SIGNAL ;
    PORT
      LAYER M5 ;
        RECT  79.392 0 79.416 0.192 ;
    END
  END e_o[288]
  PIN e_o[289]
    DIRECTION OUTPUT ;
    USE SIGNAL ;
    PORT
      LAYER M5 ;
        RECT  79.632 0 79.656 0.192 ;
    END
  END e_o[289]
  PIN e_o[28]
    DIRECTION OUTPUT ;
    USE SIGNAL ;
    PORT
      LAYER M5 ;
        RECT  13.344 0 13.368 0.192 ;
    END
  END e_o[28]
  PIN e_o[290]
    DIRECTION OUTPUT ;
    USE SIGNAL ;
    PORT
      LAYER M5 ;
        RECT  79.92 0 79.944 0.192 ;
    END
  END e_o[290]
  PIN e_o[291]
    DIRECTION OUTPUT ;
    USE SIGNAL ;
    PORT
      LAYER M5 ;
        RECT  80.16 0 80.184 0.192 ;
    END
  END e_o[291]
  PIN e_o[292]
    DIRECTION OUTPUT ;
    USE SIGNAL ;
    PORT
      LAYER M5 ;
        RECT  80.4 0 80.424 0.192 ;
    END
  END e_o[292]
  PIN e_o[293]
    DIRECTION OUTPUT ;
    USE SIGNAL ;
    PORT
      LAYER M5 ;
        RECT  80.688 0 80.712 0.192 ;
    END
  END e_o[293]
  PIN e_o[294]
    DIRECTION OUTPUT ;
    USE SIGNAL ;
    PORT
      LAYER M5 ;
        RECT  80.928 0 80.952 0.192 ;
    END
  END e_o[294]
  PIN e_o[295]
    DIRECTION OUTPUT ;
    USE SIGNAL ;
    PORT
      LAYER M5 ;
        RECT  81.168 0 81.192 0.192 ;
    END
  END e_o[295]
  PIN e_o[296]
    DIRECTION OUTPUT ;
    USE SIGNAL ;
    PORT
      LAYER M5 ;
        RECT  81.456 0 81.48 0.192 ;
    END
  END e_o[296]
  PIN e_o[297]
    DIRECTION OUTPUT ;
    USE SIGNAL ;
    PORT
      LAYER M5 ;
        RECT  81.696 0 81.72 0.192 ;
    END
  END e_o[297]
  PIN e_o[298]
    DIRECTION OUTPUT ;
    USE SIGNAL ;
    PORT
      LAYER M5 ;
        RECT  81.936 0 81.96 0.192 ;
    END
  END e_o[298]
  PIN e_o[299]
    DIRECTION OUTPUT ;
    USE SIGNAL ;
    PORT
      LAYER M5 ;
        RECT  82.176 0 82.2 0.192 ;
    END
  END e_o[299]
  PIN e_o[29]
    DIRECTION OUTPUT ;
    USE SIGNAL ;
    PORT
      LAYER M5 ;
        RECT  13.584 0 13.608 0.192 ;
    END
  END e_o[29]
  PIN e_o[2]
    DIRECTION OUTPUT ;
    USE SIGNAL ;
    PORT
      LAYER M5 ;
        RECT  6.72 0 6.744 0.192 ;
    END
  END e_o[2]
  PIN e_o[300]
    DIRECTION OUTPUT ;
    USE SIGNAL ;
    PORT
      LAYER M5 ;
        RECT  82.464 0 82.488 0.192 ;
    END
  END e_o[300]
  PIN e_o[301]
    DIRECTION OUTPUT ;
    USE SIGNAL ;
    PORT
      LAYER M5 ;
        RECT  82.704 0 82.728 0.192 ;
    END
  END e_o[301]
  PIN e_o[302]
    DIRECTION OUTPUT ;
    USE SIGNAL ;
    PORT
      LAYER M5 ;
        RECT  82.944 0 82.968 0.192 ;
    END
  END e_o[302]
  PIN e_o[303]
    DIRECTION OUTPUT ;
    USE SIGNAL ;
    PORT
      LAYER M5 ;
        RECT  83.232 0 83.256 0.192 ;
    END
  END e_o[303]
  PIN e_o[304]
    DIRECTION OUTPUT ;
    USE SIGNAL ;
    PORT
      LAYER M5 ;
        RECT  83.472 0 83.496 0.192 ;
    END
  END e_o[304]
  PIN e_o[305]
    DIRECTION OUTPUT ;
    USE SIGNAL ;
    PORT
      LAYER M5 ;
        RECT  83.712 0 83.736 0.192 ;
    END
  END e_o[305]
  PIN e_o[306]
    DIRECTION OUTPUT ;
    USE SIGNAL ;
    PORT
      LAYER M5 ;
        RECT  83.952 0 83.976 0.192 ;
    END
  END e_o[306]
  PIN e_o[307]
    DIRECTION OUTPUT ;
    USE SIGNAL ;
    PORT
      LAYER M5 ;
        RECT  84.24 0 84.264 0.192 ;
    END
  END e_o[307]
  PIN e_o[308]
    DIRECTION OUTPUT ;
    USE SIGNAL ;
    PORT
      LAYER M5 ;
        RECT  84.48 0 84.504 0.192 ;
    END
  END e_o[308]
  PIN e_o[309]
    DIRECTION OUTPUT ;
    USE SIGNAL ;
    PORT
      LAYER M5 ;
        RECT  84.72 0 84.744 0.192 ;
    END
  END e_o[309]
  PIN e_o[30]
    DIRECTION OUTPUT ;
    USE SIGNAL ;
    PORT
      LAYER M5 ;
        RECT  13.824 0 13.848 0.192 ;
    END
  END e_o[30]
  PIN e_o[310]
    DIRECTION OUTPUT ;
    USE SIGNAL ;
    PORT
      LAYER M5 ;
        RECT  85.008 0 85.032 0.192 ;
    END
  END e_o[310]
  PIN e_o[311]
    DIRECTION OUTPUT ;
    USE SIGNAL ;
    PORT
      LAYER M5 ;
        RECT  85.248 0 85.272 0.192 ;
    END
  END e_o[311]
  PIN e_o[312]
    DIRECTION OUTPUT ;
    USE SIGNAL ;
    PORT
      LAYER M5 ;
        RECT  85.488 0 85.512 0.192 ;
    END
  END e_o[312]
  PIN e_o[313]
    DIRECTION OUTPUT ;
    USE SIGNAL ;
    PORT
      LAYER M5 ;
        RECT  85.776 0 85.8 0.192 ;
    END
  END e_o[313]
  PIN e_o[314]
    DIRECTION OUTPUT ;
    USE SIGNAL ;
    PORT
      LAYER M5 ;
        RECT  86.016 0 86.04 0.192 ;
    END
  END e_o[314]
  PIN e_o[315]
    DIRECTION OUTPUT ;
    USE SIGNAL ;
    PORT
      LAYER M5 ;
        RECT  86.256 0 86.28 0.192 ;
    END
  END e_o[315]
  PIN e_o[316]
    DIRECTION OUTPUT ;
    USE SIGNAL ;
    PORT
      LAYER M5 ;
        RECT  86.496 0 86.52 0.192 ;
    END
  END e_o[316]
  PIN e_o[317]
    DIRECTION OUTPUT ;
    USE SIGNAL ;
    PORT
      LAYER M5 ;
        RECT  86.784 0 86.808 0.192 ;
    END
  END e_o[317]
  PIN e_o[318]
    DIRECTION OUTPUT ;
    USE SIGNAL ;
    PORT
      LAYER M5 ;
        RECT  87.024 0 87.048 0.192 ;
    END
  END e_o[318]
  PIN e_o[319]
    DIRECTION OUTPUT ;
    USE SIGNAL ;
    PORT
      LAYER M5 ;
        RECT  87.264 0 87.288 0.192 ;
    END
  END e_o[319]
  PIN e_o[31]
    DIRECTION OUTPUT ;
    USE SIGNAL ;
    PORT
      LAYER M5 ;
        RECT  14.112 0 14.136 0.192 ;
    END
  END e_o[31]
  PIN e_o[320]
    DIRECTION OUTPUT ;
    USE SIGNAL ;
    PORT
      LAYER M5 ;
        RECT  87.552 0 87.576 0.192 ;
    END
  END e_o[320]
  PIN e_o[321]
    DIRECTION OUTPUT ;
    USE SIGNAL ;
    PORT
      LAYER M5 ;
        RECT  87.792 0 87.816 0.192 ;
    END
  END e_o[321]
  PIN e_o[322]
    DIRECTION OUTPUT ;
    USE SIGNAL ;
    PORT
      LAYER M5 ;
        RECT  88.032 0 88.056 0.192 ;
    END
  END e_o[322]
  PIN e_o[323]
    DIRECTION OUTPUT ;
    USE SIGNAL ;
    PORT
      LAYER M5 ;
        RECT  88.272 0 88.296 0.192 ;
    END
  END e_o[323]
  PIN e_o[324]
    DIRECTION OUTPUT ;
    USE SIGNAL ;
    PORT
      LAYER M5 ;
        RECT  88.56 0 88.584 0.192 ;
    END
  END e_o[324]
  PIN e_o[325]
    DIRECTION OUTPUT ;
    USE SIGNAL ;
    PORT
      LAYER M5 ;
        RECT  88.8 0 88.824 0.192 ;
    END
  END e_o[325]
  PIN e_o[326]
    DIRECTION OUTPUT ;
    USE SIGNAL ;
    PORT
      LAYER M5 ;
        RECT  89.04 0 89.064 0.192 ;
    END
  END e_o[326]
  PIN e_o[327]
    DIRECTION OUTPUT ;
    USE SIGNAL ;
    PORT
      LAYER M5 ;
        RECT  89.328 0 89.352 0.192 ;
    END
  END e_o[327]
  PIN e_o[328]
    DIRECTION OUTPUT ;
    USE SIGNAL ;
    PORT
      LAYER M5 ;
        RECT  89.568 0 89.592 0.192 ;
    END
  END e_o[328]
  PIN e_o[329]
    DIRECTION OUTPUT ;
    USE SIGNAL ;
    PORT
      LAYER M5 ;
        RECT  89.808 0 89.832 0.192 ;
    END
  END e_o[329]
  PIN e_o[32]
    DIRECTION OUTPUT ;
    USE SIGNAL ;
    PORT
      LAYER M5 ;
        RECT  14.352 0 14.376 0.192 ;
    END
  END e_o[32]
  PIN e_o[330]
    DIRECTION OUTPUT ;
    USE SIGNAL ;
    PORT
      LAYER M5 ;
        RECT  90.096 0 90.12 0.192 ;
    END
  END e_o[330]
  PIN e_o[331]
    DIRECTION OUTPUT ;
    USE SIGNAL ;
    PORT
      LAYER M5 ;
        RECT  90.336 0 90.36 0.192 ;
    END
  END e_o[331]
  PIN e_o[332]
    DIRECTION OUTPUT ;
    USE SIGNAL ;
    PORT
      LAYER M5 ;
        RECT  90.576 0 90.6 0.192 ;
    END
  END e_o[332]
  PIN e_o[333]
    DIRECTION OUTPUT ;
    USE SIGNAL ;
    PORT
      LAYER M5 ;
        RECT  90.816 0 90.84 0.192 ;
    END
  END e_o[333]
  PIN e_o[334]
    DIRECTION OUTPUT ;
    USE SIGNAL ;
    PORT
      LAYER M5 ;
        RECT  91.104 0 91.128 0.192 ;
    END
  END e_o[334]
  PIN e_o[335]
    DIRECTION OUTPUT ;
    USE SIGNAL ;
    PORT
      LAYER M5 ;
        RECT  91.344 0 91.368 0.192 ;
    END
  END e_o[335]
  PIN e_o[336]
    DIRECTION OUTPUT ;
    USE SIGNAL ;
    PORT
      LAYER M5 ;
        RECT  91.584 0 91.608 0.192 ;
    END
  END e_o[336]
  PIN e_o[337]
    DIRECTION OUTPUT ;
    USE SIGNAL ;
    PORT
      LAYER M5 ;
        RECT  91.872 0 91.896 0.192 ;
    END
  END e_o[337]
  PIN e_o[338]
    DIRECTION OUTPUT ;
    USE SIGNAL ;
    PORT
      LAYER M5 ;
        RECT  92.112 0 92.136 0.192 ;
    END
  END e_o[338]
  PIN e_o[339]
    DIRECTION OUTPUT ;
    USE SIGNAL ;
    PORT
      LAYER M5 ;
        RECT  92.352 0 92.376 0.192 ;
    END
  END e_o[339]
  PIN e_o[33]
    DIRECTION OUTPUT ;
    USE SIGNAL ;
    PORT
      LAYER M5 ;
        RECT  14.592 0 14.616 0.192 ;
    END
  END e_o[33]
  PIN e_o[340]
    DIRECTION OUTPUT ;
    USE SIGNAL ;
    PORT
      LAYER M5 ;
        RECT  92.592 0 92.616 0.192 ;
    END
  END e_o[340]
  PIN e_o[341]
    DIRECTION OUTPUT ;
    USE SIGNAL ;
    PORT
      LAYER M5 ;
        RECT  92.88 0 92.904 0.192 ;
    END
  END e_o[341]
  PIN e_o[342]
    DIRECTION OUTPUT ;
    USE SIGNAL ;
    PORT
      LAYER M5 ;
        RECT  93.12 0 93.144 0.192 ;
    END
  END e_o[342]
  PIN e_o[343]
    DIRECTION OUTPUT ;
    USE SIGNAL ;
    PORT
      LAYER M5 ;
        RECT  93.36 0 93.384 0.192 ;
    END
  END e_o[343]
  PIN e_o[344]
    DIRECTION OUTPUT ;
    USE SIGNAL ;
    PORT
      LAYER M5 ;
        RECT  93.648 0 93.672 0.192 ;
    END
  END e_o[344]
  PIN e_o[345]
    DIRECTION OUTPUT ;
    USE SIGNAL ;
    PORT
      LAYER M5 ;
        RECT  93.888 0 93.912 0.192 ;
    END
  END e_o[345]
  PIN e_o[346]
    DIRECTION OUTPUT ;
    USE SIGNAL ;
    PORT
      LAYER M5 ;
        RECT  94.128 0 94.152 0.192 ;
    END
  END e_o[346]
  PIN e_o[347]
    DIRECTION OUTPUT ;
    USE SIGNAL ;
    PORT
      LAYER M5 ;
        RECT  94.416 0 94.44 0.192 ;
    END
  END e_o[347]
  PIN e_o[348]
    DIRECTION OUTPUT ;
    USE SIGNAL ;
    PORT
      LAYER M5 ;
        RECT  94.656 0 94.68 0.192 ;
    END
  END e_o[348]
  PIN e_o[349]
    DIRECTION OUTPUT ;
    USE SIGNAL ;
    PORT
      LAYER M5 ;
        RECT  94.896 0 94.92 0.192 ;
    END
  END e_o[349]
  PIN e_o[34]
    DIRECTION OUTPUT ;
    USE SIGNAL ;
    PORT
      LAYER M5 ;
        RECT  14.832 0 14.856 0.192 ;
    END
  END e_o[34]
  PIN e_o[350]
    DIRECTION OUTPUT ;
    USE SIGNAL ;
    PORT
      LAYER M5 ;
        RECT  95.136 0 95.16 0.192 ;
    END
  END e_o[350]
  PIN e_o[351]
    DIRECTION OUTPUT ;
    USE SIGNAL ;
    PORT
      LAYER M5 ;
        RECT  95.424 0 95.448 0.192 ;
    END
  END e_o[351]
  PIN e_o[352]
    DIRECTION OUTPUT ;
    USE SIGNAL ;
    PORT
      LAYER M5 ;
        RECT  95.664 0 95.688 0.192 ;
    END
  END e_o[352]
  PIN e_o[353]
    DIRECTION OUTPUT ;
    USE SIGNAL ;
    PORT
      LAYER M5 ;
        RECT  95.904 0 95.928 0.192 ;
    END
  END e_o[353]
  PIN e_o[354]
    DIRECTION OUTPUT ;
    USE SIGNAL ;
    PORT
      LAYER M5 ;
        RECT  96.192 0 96.216 0.192 ;
    END
  END e_o[354]
  PIN e_o[355]
    DIRECTION OUTPUT ;
    USE SIGNAL ;
    PORT
      LAYER M5 ;
        RECT  96.432 0 96.456 0.192 ;
    END
  END e_o[355]
  PIN e_o[356]
    DIRECTION OUTPUT ;
    USE SIGNAL ;
    PORT
      LAYER M5 ;
        RECT  96.672 0 96.696 0.192 ;
    END
  END e_o[356]
  PIN e_o[357]
    DIRECTION OUTPUT ;
    USE SIGNAL ;
    PORT
      LAYER M5 ;
        RECT  96.912 0 96.936 0.192 ;
    END
  END e_o[357]
  PIN e_o[358]
    DIRECTION OUTPUT ;
    USE SIGNAL ;
    PORT
      LAYER M5 ;
        RECT  97.2 0 97.224 0.192 ;
    END
  END e_o[358]
  PIN e_o[359]
    DIRECTION OUTPUT ;
    USE SIGNAL ;
    PORT
      LAYER M5 ;
        RECT  97.44 0 97.464 0.192 ;
    END
  END e_o[359]
  PIN e_o[35]
    DIRECTION OUTPUT ;
    USE SIGNAL ;
    PORT
      LAYER M5 ;
        RECT  15.12 0 15.144 0.192 ;
    END
  END e_o[35]
  PIN e_o[360]
    DIRECTION OUTPUT ;
    USE SIGNAL ;
    PORT
      LAYER M5 ;
        RECT  97.68 0 97.704 0.192 ;
    END
  END e_o[360]
  PIN e_o[361]
    DIRECTION OUTPUT ;
    USE SIGNAL ;
    PORT
      LAYER M5 ;
        RECT  97.968 0 97.992 0.192 ;
    END
  END e_o[361]
  PIN e_o[362]
    DIRECTION OUTPUT ;
    USE SIGNAL ;
    PORT
      LAYER M5 ;
        RECT  98.208 0 98.232 0.192 ;
    END
  END e_o[362]
  PIN e_o[363]
    DIRECTION OUTPUT ;
    USE SIGNAL ;
    PORT
      LAYER M5 ;
        RECT  98.448 0 98.472 0.192 ;
    END
  END e_o[363]
  PIN e_o[364]
    DIRECTION OUTPUT ;
    USE SIGNAL ;
    PORT
      LAYER M5 ;
        RECT  98.736 0 98.76 0.192 ;
    END
  END e_o[364]
  PIN e_o[365]
    DIRECTION OUTPUT ;
    USE SIGNAL ;
    PORT
      LAYER M5 ;
        RECT  98.976 0 99 0.192 ;
    END
  END e_o[365]
  PIN e_o[366]
    DIRECTION OUTPUT ;
    USE SIGNAL ;
    PORT
      LAYER M5 ;
        RECT  99.216 0 99.24 0.192 ;
    END
  END e_o[366]
  PIN e_o[367]
    DIRECTION OUTPUT ;
    USE SIGNAL ;
    PORT
      LAYER M5 ;
        RECT  99.456 0 99.48 0.192 ;
    END
  END e_o[367]
  PIN e_o[368]
    DIRECTION OUTPUT ;
    USE SIGNAL ;
    PORT
      LAYER M5 ;
        RECT  99.744 0 99.768 0.192 ;
    END
  END e_o[368]
  PIN e_o[369]
    DIRECTION OUTPUT ;
    USE SIGNAL ;
    PORT
      LAYER M5 ;
        RECT  99.984 0 100.008 0.192 ;
    END
  END e_o[369]
  PIN e_o[36]
    DIRECTION OUTPUT ;
    USE SIGNAL ;
    PORT
      LAYER M5 ;
        RECT  15.36 0 15.384 0.192 ;
    END
  END e_o[36]
  PIN e_o[370]
    DIRECTION OUTPUT ;
    USE SIGNAL ;
    PORT
      LAYER M5 ;
        RECT  100.224 0 100.248 0.192 ;
    END
  END e_o[370]
  PIN e_o[371]
    DIRECTION OUTPUT ;
    USE SIGNAL ;
    PORT
      LAYER M5 ;
        RECT  100.512 0 100.536 0.192 ;
    END
  END e_o[371]
  PIN e_o[372]
    DIRECTION OUTPUT ;
    USE SIGNAL ;
    PORT
      LAYER M5 ;
        RECT  100.752 0 100.776 0.192 ;
    END
  END e_o[372]
  PIN e_o[373]
    DIRECTION OUTPUT ;
    USE SIGNAL ;
    PORT
      LAYER M5 ;
        RECT  100.992 0 101.016 0.192 ;
    END
  END e_o[373]
  PIN e_o[374]
    DIRECTION OUTPUT ;
    USE SIGNAL ;
    PORT
      LAYER M5 ;
        RECT  101.232 0 101.256 0.192 ;
    END
  END e_o[374]
  PIN e_o[375]
    DIRECTION OUTPUT ;
    USE SIGNAL ;
    PORT
      LAYER M5 ;
        RECT  101.52 0 101.544 0.192 ;
    END
  END e_o[375]
  PIN e_o[376]
    DIRECTION OUTPUT ;
    USE SIGNAL ;
    PORT
      LAYER M5 ;
        RECT  101.76 0 101.784 0.192 ;
    END
  END e_o[376]
  PIN e_o[377]
    DIRECTION OUTPUT ;
    USE SIGNAL ;
    PORT
      LAYER M5 ;
        RECT  102 0 102.024 0.192 ;
    END
  END e_o[377]
  PIN e_o[378]
    DIRECTION OUTPUT ;
    USE SIGNAL ;
    PORT
      LAYER M5 ;
        RECT  102.288 0 102.312 0.192 ;
    END
  END e_o[378]
  PIN e_o[379]
    DIRECTION OUTPUT ;
    USE SIGNAL ;
    PORT
      LAYER M5 ;
        RECT  102.528 0 102.552 0.192 ;
    END
  END e_o[379]
  PIN e_o[37]
    DIRECTION OUTPUT ;
    USE SIGNAL ;
    PORT
      LAYER M5 ;
        RECT  15.6 0 15.624 0.192 ;
    END
  END e_o[37]
  PIN e_o[380]
    DIRECTION OUTPUT ;
    USE SIGNAL ;
    PORT
      LAYER M5 ;
        RECT  102.768 0 102.792 0.192 ;
    END
  END e_o[380]
  PIN e_o[381]
    DIRECTION OUTPUT ;
    USE SIGNAL ;
    PORT
      LAYER M5 ;
        RECT  103.056 0 103.08 0.192 ;
    END
  END e_o[381]
  PIN e_o[382]
    DIRECTION OUTPUT ;
    USE SIGNAL ;
    PORT
      LAYER M5 ;
        RECT  103.296 0 103.32 0.192 ;
    END
  END e_o[382]
  PIN e_o[383]
    DIRECTION OUTPUT ;
    USE SIGNAL ;
    PORT
      LAYER M5 ;
        RECT  103.536 0 103.56 0.192 ;
    END
  END e_o[383]
  PIN e_o[384]
    DIRECTION OUTPUT ;
    USE SIGNAL ;
    PORT
      LAYER M5 ;
        RECT  103.776 0 103.8 0.192 ;
    END
  END e_o[384]
  PIN e_o[385]
    DIRECTION OUTPUT ;
    USE SIGNAL ;
    PORT
      LAYER M5 ;
        RECT  104.064 0 104.088 0.192 ;
    END
  END e_o[385]
  PIN e_o[386]
    DIRECTION OUTPUT ;
    USE SIGNAL ;
    PORT
      LAYER M5 ;
        RECT  104.304 0 104.328 0.192 ;
    END
  END e_o[386]
  PIN e_o[387]
    DIRECTION OUTPUT ;
    USE SIGNAL ;
    PORT
      LAYER M5 ;
        RECT  104.544 0 104.568 0.192 ;
    END
  END e_o[387]
  PIN e_o[388]
    DIRECTION OUTPUT ;
    USE SIGNAL ;
    PORT
      LAYER M5 ;
        RECT  104.832 0 104.856 0.192 ;
    END
  END e_o[388]
  PIN e_o[389]
    DIRECTION OUTPUT ;
    USE SIGNAL ;
    PORT
      LAYER M5 ;
        RECT  105.072 0 105.096 0.192 ;
    END
  END e_o[389]
  PIN e_o[38]
    DIRECTION OUTPUT ;
    USE SIGNAL ;
    PORT
      LAYER M5 ;
        RECT  15.888 0 15.912 0.192 ;
    END
  END e_o[38]
  PIN e_o[390]
    DIRECTION OUTPUT ;
    USE SIGNAL ;
    PORT
      LAYER M5 ;
        RECT  105.312 0 105.336 0.192 ;
    END
  END e_o[390]
  PIN e_o[391]
    DIRECTION OUTPUT ;
    USE SIGNAL ;
    PORT
      LAYER M5 ;
        RECT  105.552 0 105.576 0.192 ;
    END
  END e_o[391]
  PIN e_o[392]
    DIRECTION OUTPUT ;
    USE SIGNAL ;
    PORT
      LAYER M5 ;
        RECT  105.84 0 105.864 0.192 ;
    END
  END e_o[392]
  PIN e_o[393]
    DIRECTION OUTPUT ;
    USE SIGNAL ;
    PORT
      LAYER M5 ;
        RECT  106.08 0 106.104 0.192 ;
    END
  END e_o[393]
  PIN e_o[394]
    DIRECTION OUTPUT ;
    USE SIGNAL ;
    PORT
      LAYER M5 ;
        RECT  106.32 0 106.344 0.192 ;
    END
  END e_o[394]
  PIN e_o[395]
    DIRECTION OUTPUT ;
    USE SIGNAL ;
    PORT
      LAYER M5 ;
        RECT  106.608 0 106.632 0.192 ;
    END
  END e_o[395]
  PIN e_o[396]
    DIRECTION OUTPUT ;
    USE SIGNAL ;
    PORT
      LAYER M5 ;
        RECT  106.848 0 106.872 0.192 ;
    END
  END e_o[396]
  PIN e_o[397]
    DIRECTION OUTPUT ;
    USE SIGNAL ;
    PORT
      LAYER M5 ;
        RECT  107.088 0 107.112 0.192 ;
    END
  END e_o[397]
  PIN e_o[398]
    DIRECTION OUTPUT ;
    USE SIGNAL ;
    PORT
      LAYER M5 ;
        RECT  107.376 0 107.4 0.192 ;
    END
  END e_o[398]
  PIN e_o[399]
    DIRECTION OUTPUT ;
    USE SIGNAL ;
    PORT
      LAYER M5 ;
        RECT  107.616 0 107.64 0.192 ;
    END
  END e_o[399]
  PIN e_o[39]
    DIRECTION OUTPUT ;
    USE SIGNAL ;
    PORT
      LAYER M5 ;
        RECT  16.128 0 16.152 0.192 ;
    END
  END e_o[39]
  PIN e_o[3]
    DIRECTION OUTPUT ;
    USE SIGNAL ;
    PORT
      LAYER M5 ;
        RECT  6.96 0 6.984 0.192 ;
    END
  END e_o[3]
  PIN e_o[400]
    DIRECTION OUTPUT ;
    USE SIGNAL ;
    PORT
      LAYER M5 ;
        RECT  107.856 0 107.88 0.192 ;
    END
  END e_o[400]
  PIN e_o[401]
    DIRECTION OUTPUT ;
    USE SIGNAL ;
    PORT
      LAYER M5 ;
        RECT  108.096 0 108.12 0.192 ;
    END
  END e_o[401]
  PIN e_o[402]
    DIRECTION OUTPUT ;
    USE SIGNAL ;
    PORT
      LAYER M5 ;
        RECT  108.384 0 108.408 0.192 ;
    END
  END e_o[402]
  PIN e_o[403]
    DIRECTION OUTPUT ;
    USE SIGNAL ;
    PORT
      LAYER M5 ;
        RECT  108.624 0 108.648 0.192 ;
    END
  END e_o[403]
  PIN e_o[404]
    DIRECTION OUTPUT ;
    USE SIGNAL ;
    PORT
      LAYER M5 ;
        RECT  108.864 0 108.888 0.192 ;
    END
  END e_o[404]
  PIN e_o[405]
    DIRECTION OUTPUT ;
    USE SIGNAL ;
    PORT
      LAYER M5 ;
        RECT  109.152 0 109.176 0.192 ;
    END
  END e_o[405]
  PIN e_o[406]
    DIRECTION OUTPUT ;
    USE SIGNAL ;
    PORT
      LAYER M5 ;
        RECT  109.392 0 109.416 0.192 ;
    END
  END e_o[406]
  PIN e_o[407]
    DIRECTION OUTPUT ;
    USE SIGNAL ;
    PORT
      LAYER M5 ;
        RECT  109.632 0 109.656 0.192 ;
    END
  END e_o[407]
  PIN e_o[408]
    DIRECTION OUTPUT ;
    USE SIGNAL ;
    PORT
      LAYER M5 ;
        RECT  109.872 0 109.896 0.192 ;
    END
  END e_o[408]
  PIN e_o[409]
    DIRECTION OUTPUT ;
    USE SIGNAL ;
    PORT
      LAYER M5 ;
        RECT  110.16 0 110.184 0.192 ;
    END
  END e_o[409]
  PIN e_o[40]
    DIRECTION OUTPUT ;
    USE SIGNAL ;
    PORT
      LAYER M5 ;
        RECT  16.368 0 16.392 0.192 ;
    END
  END e_o[40]
  PIN e_o[410]
    DIRECTION OUTPUT ;
    USE SIGNAL ;
    PORT
      LAYER M5 ;
        RECT  110.4 0 110.424 0.192 ;
    END
  END e_o[410]
  PIN e_o[411]
    DIRECTION OUTPUT ;
    USE SIGNAL ;
    PORT
      LAYER M5 ;
        RECT  110.64 0 110.664 0.192 ;
    END
  END e_o[411]
  PIN e_o[412]
    DIRECTION OUTPUT ;
    USE SIGNAL ;
    PORT
      LAYER M5 ;
        RECT  110.928 0 110.952 0.192 ;
    END
  END e_o[412]
  PIN e_o[413]
    DIRECTION OUTPUT ;
    USE SIGNAL ;
    PORT
      LAYER M5 ;
        RECT  111.168 0 111.192 0.192 ;
    END
  END e_o[413]
  PIN e_o[414]
    DIRECTION OUTPUT ;
    USE SIGNAL ;
    PORT
      LAYER M5 ;
        RECT  111.408 0 111.432 0.192 ;
    END
  END e_o[414]
  PIN e_o[415]
    DIRECTION OUTPUT ;
    USE SIGNAL ;
    PORT
      LAYER M5 ;
        RECT  111.696 0 111.72 0.192 ;
    END
  END e_o[415]
  PIN e_o[416]
    DIRECTION OUTPUT ;
    USE SIGNAL ;
    PORT
      LAYER M5 ;
        RECT  111.936 0 111.96 0.192 ;
    END
  END e_o[416]
  PIN e_o[417]
    DIRECTION OUTPUT ;
    USE SIGNAL ;
    PORT
      LAYER M5 ;
        RECT  112.176 0 112.2 0.192 ;
    END
  END e_o[417]
  PIN e_o[418]
    DIRECTION OUTPUT ;
    USE SIGNAL ;
    PORT
      LAYER M5 ;
        RECT  112.416 0 112.44 0.192 ;
    END
  END e_o[418]
  PIN e_o[419]
    DIRECTION OUTPUT ;
    USE SIGNAL ;
    PORT
      LAYER M5 ;
        RECT  112.704 0 112.728 0.192 ;
    END
  END e_o[419]
  PIN e_o[41]
    DIRECTION OUTPUT ;
    USE SIGNAL ;
    PORT
      LAYER M5 ;
        RECT  16.656 0 16.68 0.192 ;
    END
  END e_o[41]
  PIN e_o[420]
    DIRECTION OUTPUT ;
    USE SIGNAL ;
    PORT
      LAYER M5 ;
        RECT  112.944 0 112.968 0.192 ;
    END
  END e_o[420]
  PIN e_o[421]
    DIRECTION OUTPUT ;
    USE SIGNAL ;
    PORT
      LAYER M5 ;
        RECT  113.184 0 113.208 0.192 ;
    END
  END e_o[421]
  PIN e_o[422]
    DIRECTION OUTPUT ;
    USE SIGNAL ;
    PORT
      LAYER M5 ;
        RECT  113.472 0 113.496 0.192 ;
    END
  END e_o[422]
  PIN e_o[423]
    DIRECTION OUTPUT ;
    USE SIGNAL ;
    PORT
      LAYER M5 ;
        RECT  113.712 0 113.736 0.192 ;
    END
  END e_o[423]
  PIN e_o[424]
    DIRECTION OUTPUT ;
    USE SIGNAL ;
    PORT
      LAYER M5 ;
        RECT  113.952 0 113.976 0.192 ;
    END
  END e_o[424]
  PIN e_o[425]
    DIRECTION OUTPUT ;
    USE SIGNAL ;
    PORT
      LAYER M5 ;
        RECT  114.192 0 114.216 0.192 ;
    END
  END e_o[425]
  PIN e_o[426]
    DIRECTION OUTPUT ;
    USE SIGNAL ;
    PORT
      LAYER M5 ;
        RECT  114.48 0 114.504 0.192 ;
    END
  END e_o[426]
  PIN e_o[427]
    DIRECTION OUTPUT ;
    USE SIGNAL ;
    PORT
      LAYER M5 ;
        RECT  114.72 0 114.744 0.192 ;
    END
  END e_o[427]
  PIN e_o[428]
    DIRECTION OUTPUT ;
    USE SIGNAL ;
    PORT
      LAYER M5 ;
        RECT  114.96 0 114.984 0.192 ;
    END
  END e_o[428]
  PIN e_o[429]
    DIRECTION OUTPUT ;
    USE SIGNAL ;
    PORT
      LAYER M5 ;
        RECT  115.248 0 115.272 0.192 ;
    END
  END e_o[429]
  PIN e_o[42]
    DIRECTION OUTPUT ;
    USE SIGNAL ;
    PORT
      LAYER M5 ;
        RECT  16.896 0 16.92 0.192 ;
    END
  END e_o[42]
  PIN e_o[430]
    DIRECTION OUTPUT ;
    USE SIGNAL ;
    PORT
      LAYER M5 ;
        RECT  115.488 0 115.512 0.192 ;
    END
  END e_o[430]
  PIN e_o[431]
    DIRECTION OUTPUT ;
    USE SIGNAL ;
    PORT
      LAYER M5 ;
        RECT  115.728 0 115.752 0.192 ;
    END
  END e_o[431]
  PIN e_o[432]
    DIRECTION OUTPUT ;
    USE SIGNAL ;
    PORT
      LAYER M5 ;
        RECT  116.016 0 116.04 0.192 ;
    END
  END e_o[432]
  PIN e_o[433]
    DIRECTION OUTPUT ;
    USE SIGNAL ;
    PORT
      LAYER M5 ;
        RECT  116.256 0 116.28 0.192 ;
    END
  END e_o[433]
  PIN e_o[434]
    DIRECTION OUTPUT ;
    USE SIGNAL ;
    PORT
      LAYER M5 ;
        RECT  116.496 0 116.52 0.192 ;
    END
  END e_o[434]
  PIN e_o[435]
    DIRECTION OUTPUT ;
    USE SIGNAL ;
    PORT
      LAYER M5 ;
        RECT  116.736 0 116.76 0.192 ;
    END
  END e_o[435]
  PIN e_o[436]
    DIRECTION OUTPUT ;
    USE SIGNAL ;
    PORT
      LAYER M5 ;
        RECT  117.024 0 117.048 0.192 ;
    END
  END e_o[436]
  PIN e_o[437]
    DIRECTION OUTPUT ;
    USE SIGNAL ;
    PORT
      LAYER M5 ;
        RECT  117.264 0 117.288 0.192 ;
    END
  END e_o[437]
  PIN e_o[438]
    DIRECTION OUTPUT ;
    USE SIGNAL ;
    PORT
      LAYER M5 ;
        RECT  117.504 0 117.528 0.192 ;
    END
  END e_o[438]
  PIN e_o[439]
    DIRECTION OUTPUT ;
    USE SIGNAL ;
    PORT
      LAYER M5 ;
        RECT  117.792 0 117.816 0.192 ;
    END
  END e_o[439]
  PIN e_o[43]
    DIRECTION OUTPUT ;
    USE SIGNAL ;
    PORT
      LAYER M5 ;
        RECT  17.136 0 17.16 0.192 ;
    END
  END e_o[43]
  PIN e_o[440]
    DIRECTION OUTPUT ;
    USE SIGNAL ;
    PORT
      LAYER M5 ;
        RECT  118.032 0 118.056 0.192 ;
    END
  END e_o[440]
  PIN e_o[441]
    DIRECTION OUTPUT ;
    USE SIGNAL ;
    PORT
      LAYER M5 ;
        RECT  118.272 0 118.296 0.192 ;
    END
  END e_o[441]
  PIN e_o[442]
    DIRECTION OUTPUT ;
    USE SIGNAL ;
    PORT
      LAYER M5 ;
        RECT  118.512 0 118.536 0.192 ;
    END
  END e_o[442]
  PIN e_o[443]
    DIRECTION OUTPUT ;
    USE SIGNAL ;
    PORT
      LAYER M5 ;
        RECT  118.8 0 118.824 0.192 ;
    END
  END e_o[443]
  PIN e_o[444]
    DIRECTION OUTPUT ;
    USE SIGNAL ;
    PORT
      LAYER M5 ;
        RECT  119.04 0 119.064 0.192 ;
    END
  END e_o[444]
  PIN e_o[445]
    DIRECTION OUTPUT ;
    USE SIGNAL ;
    PORT
      LAYER M5 ;
        RECT  119.28 0 119.304 0.192 ;
    END
  END e_o[445]
  PIN e_o[446]
    DIRECTION OUTPUT ;
    USE SIGNAL ;
    PORT
      LAYER M5 ;
        RECT  119.568 0 119.592 0.192 ;
    END
  END e_o[446]
  PIN e_o[447]
    DIRECTION OUTPUT ;
    USE SIGNAL ;
    PORT
      LAYER M5 ;
        RECT  119.808 0 119.832 0.192 ;
    END
  END e_o[447]
  PIN e_o[448]
    DIRECTION OUTPUT ;
    USE SIGNAL ;
    PORT
      LAYER M5 ;
        RECT  120.048 0 120.072 0.192 ;
    END
  END e_o[448]
  PIN e_o[449]
    DIRECTION OUTPUT ;
    USE SIGNAL ;
    PORT
      LAYER M5 ;
        RECT  120.336 0 120.36 0.192 ;
    END
  END e_o[449]
  PIN e_o[44]
    DIRECTION OUTPUT ;
    USE SIGNAL ;
    PORT
      LAYER M5 ;
        RECT  17.376 0 17.4 0.192 ;
    END
  END e_o[44]
  PIN e_o[450]
    DIRECTION OUTPUT ;
    USE SIGNAL ;
    PORT
      LAYER M5 ;
        RECT  120.576 0 120.6 0.192 ;
    END
  END e_o[450]
  PIN e_o[451]
    DIRECTION OUTPUT ;
    USE SIGNAL ;
    PORT
      LAYER M5 ;
        RECT  120.816 0 120.84 0.192 ;
    END
  END e_o[451]
  PIN e_o[452]
    DIRECTION OUTPUT ;
    USE SIGNAL ;
    PORT
      LAYER M5 ;
        RECT  121.056 0 121.08 0.192 ;
    END
  END e_o[452]
  PIN e_o[453]
    DIRECTION OUTPUT ;
    USE SIGNAL ;
    PORT
      LAYER M5 ;
        RECT  121.344 0 121.368 0.192 ;
    END
  END e_o[453]
  PIN e_o[454]
    DIRECTION OUTPUT ;
    USE SIGNAL ;
    PORT
      LAYER M5 ;
        RECT  121.584 0 121.608 0.192 ;
    END
  END e_o[454]
  PIN e_o[455]
    DIRECTION OUTPUT ;
    USE SIGNAL ;
    PORT
      LAYER M5 ;
        RECT  121.824 0 121.848 0.192 ;
    END
  END e_o[455]
  PIN e_o[456]
    DIRECTION OUTPUT ;
    USE SIGNAL ;
    PORT
      LAYER M5 ;
        RECT  122.112 0 122.136 0.192 ;
    END
  END e_o[456]
  PIN e_o[457]
    DIRECTION OUTPUT ;
    USE SIGNAL ;
    PORT
      LAYER M5 ;
        RECT  122.352 0 122.376 0.192 ;
    END
  END e_o[457]
  PIN e_o[458]
    DIRECTION OUTPUT ;
    USE SIGNAL ;
    PORT
      LAYER M5 ;
        RECT  122.592 0 122.616 0.192 ;
    END
  END e_o[458]
  PIN e_o[459]
    DIRECTION OUTPUT ;
    USE SIGNAL ;
    PORT
      LAYER M5 ;
        RECT  122.832 0 122.856 0.192 ;
    END
  END e_o[459]
  PIN e_o[45]
    DIRECTION OUTPUT ;
    USE SIGNAL ;
    PORT
      LAYER M5 ;
        RECT  17.664 0 17.688 0.192 ;
    END
  END e_o[45]
  PIN e_o[460]
    DIRECTION OUTPUT ;
    USE SIGNAL ;
    PORT
      LAYER M5 ;
        RECT  123.12 0 123.144 0.192 ;
    END
  END e_o[460]
  PIN e_o[461]
    DIRECTION OUTPUT ;
    USE SIGNAL ;
    PORT
      LAYER M5 ;
        RECT  123.36 0 123.384 0.192 ;
    END
  END e_o[461]
  PIN e_o[462]
    DIRECTION OUTPUT ;
    USE SIGNAL ;
    PORT
      LAYER M5 ;
        RECT  123.6 0 123.624 0.192 ;
    END
  END e_o[462]
  PIN e_o[463]
    DIRECTION OUTPUT ;
    USE SIGNAL ;
    PORT
      LAYER M5 ;
        RECT  123.888 0 123.912 0.192 ;
    END
  END e_o[463]
  PIN e_o[464]
    DIRECTION OUTPUT ;
    USE SIGNAL ;
    PORT
      LAYER M5 ;
        RECT  124.128 0 124.152 0.192 ;
    END
  END e_o[464]
  PIN e_o[465]
    DIRECTION OUTPUT ;
    USE SIGNAL ;
    PORT
      LAYER M5 ;
        RECT  124.368 0 124.392 0.192 ;
    END
  END e_o[465]
  PIN e_o[466]
    DIRECTION OUTPUT ;
    USE SIGNAL ;
    PORT
      LAYER M5 ;
        RECT  124.656 0 124.68 0.192 ;
    END
  END e_o[466]
  PIN e_o[467]
    DIRECTION OUTPUT ;
    USE SIGNAL ;
    PORT
      LAYER M5 ;
        RECT  124.896 0 124.92 0.192 ;
    END
  END e_o[467]
  PIN e_o[468]
    DIRECTION OUTPUT ;
    USE SIGNAL ;
    PORT
      LAYER M5 ;
        RECT  125.136 0 125.16 0.192 ;
    END
  END e_o[468]
  PIN e_o[469]
    DIRECTION OUTPUT ;
    USE SIGNAL ;
    PORT
      LAYER M5 ;
        RECT  125.376 0 125.4 0.192 ;
    END
  END e_o[469]
  PIN e_o[46]
    DIRECTION OUTPUT ;
    USE SIGNAL ;
    PORT
      LAYER M5 ;
        RECT  17.904 0 17.928 0.192 ;
    END
  END e_o[46]
  PIN e_o[470]
    DIRECTION OUTPUT ;
    USE SIGNAL ;
    PORT
      LAYER M5 ;
        RECT  125.664 0 125.688 0.192 ;
    END
  END e_o[470]
  PIN e_o[471]
    DIRECTION OUTPUT ;
    USE SIGNAL ;
    PORT
      LAYER M5 ;
        RECT  125.904 0 125.928 0.192 ;
    END
  END e_o[471]
  PIN e_o[472]
    DIRECTION OUTPUT ;
    USE SIGNAL ;
    PORT
      LAYER M5 ;
        RECT  126.144 0 126.168 0.192 ;
    END
  END e_o[472]
  PIN e_o[473]
    DIRECTION OUTPUT ;
    USE SIGNAL ;
    PORT
      LAYER M5 ;
        RECT  126.432 0 126.456 0.192 ;
    END
  END e_o[473]
  PIN e_o[474]
    DIRECTION OUTPUT ;
    USE SIGNAL ;
    PORT
      LAYER M5 ;
        RECT  126.672 0 126.696 0.192 ;
    END
  END e_o[474]
  PIN e_o[475]
    DIRECTION OUTPUT ;
    USE SIGNAL ;
    PORT
      LAYER M5 ;
        RECT  126.912 0 126.936 0.192 ;
    END
  END e_o[475]
  PIN e_o[476]
    DIRECTION OUTPUT ;
    USE SIGNAL ;
    PORT
      LAYER M5 ;
        RECT  127.152 0 127.176 0.192 ;
    END
  END e_o[476]
  PIN e_o[477]
    DIRECTION OUTPUT ;
    USE SIGNAL ;
    PORT
      LAYER M5 ;
        RECT  127.44 0 127.464 0.192 ;
    END
  END e_o[477]
  PIN e_o[478]
    DIRECTION OUTPUT ;
    USE SIGNAL ;
    PORT
      LAYER M5 ;
        RECT  127.68 0 127.704 0.192 ;
    END
  END e_o[478]
  PIN e_o[479]
    DIRECTION OUTPUT ;
    USE SIGNAL ;
    PORT
      LAYER M5 ;
        RECT  127.92 0 127.944 0.192 ;
    END
  END e_o[479]
  PIN e_o[47]
    DIRECTION OUTPUT ;
    USE SIGNAL ;
    PORT
      LAYER M5 ;
        RECT  18.144 0 18.168 0.192 ;
    END
  END e_o[47]
  PIN e_o[480]
    DIRECTION OUTPUT ;
    USE SIGNAL ;
    PORT
      LAYER M5 ;
        RECT  128.208 0 128.232 0.192 ;
    END
  END e_o[480]
  PIN e_o[481]
    DIRECTION OUTPUT ;
    USE SIGNAL ;
    PORT
      LAYER M5 ;
        RECT  128.448 0 128.472 0.192 ;
    END
  END e_o[481]
  PIN e_o[482]
    DIRECTION OUTPUT ;
    USE SIGNAL ;
    PORT
      LAYER M5 ;
        RECT  128.688 0 128.712 0.192 ;
    END
  END e_o[482]
  PIN e_o[483]
    DIRECTION OUTPUT ;
    USE SIGNAL ;
    PORT
      LAYER M5 ;
        RECT  128.976 0 129 0.192 ;
    END
  END e_o[483]
  PIN e_o[484]
    DIRECTION OUTPUT ;
    USE SIGNAL ;
    PORT
      LAYER M5 ;
        RECT  129.216 0 129.24 0.192 ;
    END
  END e_o[484]
  PIN e_o[485]
    DIRECTION OUTPUT ;
    USE SIGNAL ;
    PORT
      LAYER M5 ;
        RECT  129.456 0 129.48 0.192 ;
    END
  END e_o[485]
  PIN e_o[486]
    DIRECTION OUTPUT ;
    USE SIGNAL ;
    PORT
      LAYER M5 ;
        RECT  129.696 0 129.72 0.192 ;
    END
  END e_o[486]
  PIN e_o[487]
    DIRECTION OUTPUT ;
    USE SIGNAL ;
    PORT
      LAYER M5 ;
        RECT  129.984 0 130.008 0.192 ;
    END
  END e_o[487]
  PIN e_o[488]
    DIRECTION OUTPUT ;
    USE SIGNAL ;
    PORT
      LAYER M5 ;
        RECT  130.224 0 130.248 0.192 ;
    END
  END e_o[488]
  PIN e_o[489]
    DIRECTION OUTPUT ;
    USE SIGNAL ;
    PORT
      LAYER M5 ;
        RECT  130.464 0 130.488 0.192 ;
    END
  END e_o[489]
  PIN e_o[48]
    DIRECTION OUTPUT ;
    USE SIGNAL ;
    PORT
      LAYER M5 ;
        RECT  18.432 0 18.456 0.192 ;
    END
  END e_o[48]
  PIN e_o[490]
    DIRECTION OUTPUT ;
    USE SIGNAL ;
    PORT
      LAYER M5 ;
        RECT  130.752 0 130.776 0.192 ;
    END
  END e_o[490]
  PIN e_o[491]
    DIRECTION OUTPUT ;
    USE SIGNAL ;
    PORT
      LAYER M5 ;
        RECT  130.992 0 131.016 0.192 ;
    END
  END e_o[491]
  PIN e_o[492]
    DIRECTION OUTPUT ;
    USE SIGNAL ;
    PORT
      LAYER M5 ;
        RECT  131.232 0 131.256 0.192 ;
    END
  END e_o[492]
  PIN e_o[493]
    DIRECTION OUTPUT ;
    USE SIGNAL ;
    PORT
      LAYER M5 ;
        RECT  131.472 0 131.496 0.192 ;
    END
  END e_o[493]
  PIN e_o[494]
    DIRECTION OUTPUT ;
    USE SIGNAL ;
    PORT
      LAYER M5 ;
        RECT  131.76 0 131.784 0.192 ;
    END
  END e_o[494]
  PIN e_o[495]
    DIRECTION OUTPUT ;
    USE SIGNAL ;
    PORT
      LAYER M5 ;
        RECT  132 0 132.024 0.192 ;
    END
  END e_o[495]
  PIN e_o[496]
    DIRECTION OUTPUT ;
    USE SIGNAL ;
    PORT
      LAYER M5 ;
        RECT  132.24 0 132.264 0.192 ;
    END
  END e_o[496]
  PIN e_o[497]
    DIRECTION OUTPUT ;
    USE SIGNAL ;
    PORT
      LAYER M5 ;
        RECT  132.528 0 132.552 0.192 ;
    END
  END e_o[497]
  PIN e_o[498]
    DIRECTION OUTPUT ;
    USE SIGNAL ;
    PORT
      LAYER M5 ;
        RECT  132.768 0 132.792 0.192 ;
    END
  END e_o[498]
  PIN e_o[499]
    DIRECTION OUTPUT ;
    USE SIGNAL ;
    PORT
      LAYER M5 ;
        RECT  133.008 0 133.032 0.192 ;
    END
  END e_o[499]
  PIN e_o[49]
    DIRECTION OUTPUT ;
    USE SIGNAL ;
    PORT
      LAYER M5 ;
        RECT  18.672 0 18.696 0.192 ;
    END
  END e_o[49]
  PIN e_o[4]
    DIRECTION OUTPUT ;
    USE SIGNAL ;
    PORT
      LAYER M5 ;
        RECT  7.248 0 7.272 0.192 ;
    END
  END e_o[4]
  PIN e_o[500]
    DIRECTION OUTPUT ;
    USE SIGNAL ;
    PORT
      LAYER M5 ;
        RECT  133.296 0 133.32 0.192 ;
    END
  END e_o[500]
  PIN e_o[501]
    DIRECTION OUTPUT ;
    USE SIGNAL ;
    PORT
      LAYER M5 ;
        RECT  133.536 0 133.56 0.192 ;
    END
  END e_o[501]
  PIN e_o[502]
    DIRECTION OUTPUT ;
    USE SIGNAL ;
    PORT
      LAYER M5 ;
        RECT  133.776 0 133.8 0.192 ;
    END
  END e_o[502]
  PIN e_o[503]
    DIRECTION OUTPUT ;
    USE SIGNAL ;
    PORT
      LAYER M5 ;
        RECT  134.016 0 134.04 0.192 ;
    END
  END e_o[503]
  PIN e_o[504]
    DIRECTION OUTPUT ;
    USE SIGNAL ;
    PORT
      LAYER M5 ;
        RECT  134.304 0 134.328 0.192 ;
    END
  END e_o[504]
  PIN e_o[505]
    DIRECTION OUTPUT ;
    USE SIGNAL ;
    PORT
      LAYER M5 ;
        RECT  134.544 0 134.568 0.192 ;
    END
  END e_o[505]
  PIN e_o[506]
    DIRECTION OUTPUT ;
    USE SIGNAL ;
    PORT
      LAYER M5 ;
        RECT  134.784 0 134.808 0.192 ;
    END
  END e_o[506]
  PIN e_o[507]
    DIRECTION OUTPUT ;
    USE SIGNAL ;
    PORT
      LAYER M5 ;
        RECT  135.072 0 135.096 0.192 ;
    END
  END e_o[507]
  PIN e_o[508]
    DIRECTION OUTPUT ;
    USE SIGNAL ;
    PORT
      LAYER M5 ;
        RECT  135.312 0 135.336 0.192 ;
    END
  END e_o[508]
  PIN e_o[509]
    DIRECTION OUTPUT ;
    USE SIGNAL ;
    PORT
      LAYER M5 ;
        RECT  135.552 0 135.576 0.192 ;
    END
  END e_o[509]
  PIN e_o[50]
    DIRECTION OUTPUT ;
    USE SIGNAL ;
    PORT
      LAYER M5 ;
        RECT  18.912 0 18.936 0.192 ;
    END
  END e_o[50]
  PIN e_o[510]
    DIRECTION OUTPUT ;
    USE SIGNAL ;
    PORT
      LAYER M5 ;
        RECT  135.792 0 135.816 0.192 ;
    END
  END e_o[510]
  PIN e_o[511]
    DIRECTION OUTPUT ;
    USE SIGNAL ;
    PORT
      LAYER M5 ;
        RECT  136.08 0 136.104 0.192 ;
    END
  END e_o[511]
  PIN e_o[51]
    DIRECTION OUTPUT ;
    USE SIGNAL ;
    PORT
      LAYER M5 ;
        RECT  19.152 0 19.176 0.192 ;
    END
  END e_o[51]
  PIN e_o[52]
    DIRECTION OUTPUT ;
    USE SIGNAL ;
    PORT
      LAYER M5 ;
        RECT  19.44 0 19.464 0.192 ;
    END
  END e_o[52]
  PIN e_o[53]
    DIRECTION OUTPUT ;
    USE SIGNAL ;
    PORT
      LAYER M5 ;
        RECT  19.68 0 19.704 0.192 ;
    END
  END e_o[53]
  PIN e_o[54]
    DIRECTION OUTPUT ;
    USE SIGNAL ;
    PORT
      LAYER M5 ;
        RECT  19.92 0 19.944 0.192 ;
    END
  END e_o[54]
  PIN e_o[55]
    DIRECTION OUTPUT ;
    USE SIGNAL ;
    PORT
      LAYER M5 ;
        RECT  20.208 0 20.232 0.192 ;
    END
  END e_o[55]
  PIN e_o[56]
    DIRECTION OUTPUT ;
    USE SIGNAL ;
    PORT
      LAYER M5 ;
        RECT  20.448 0 20.472 0.192 ;
    END
  END e_o[56]
  PIN e_o[57]
    DIRECTION OUTPUT ;
    USE SIGNAL ;
    PORT
      LAYER M5 ;
        RECT  20.688 0 20.712 0.192 ;
    END
  END e_o[57]
  PIN e_o[58]
    DIRECTION OUTPUT ;
    USE SIGNAL ;
    PORT
      LAYER M5 ;
        RECT  20.976 0 21 0.192 ;
    END
  END e_o[58]
  PIN e_o[59]
    DIRECTION OUTPUT ;
    USE SIGNAL ;
    PORT
      LAYER M5 ;
        RECT  21.216 0 21.24 0.192 ;
    END
  END e_o[59]
  PIN e_o[5]
    DIRECTION OUTPUT ;
    USE SIGNAL ;
    PORT
      LAYER M5 ;
        RECT  7.488 0 7.512 0.192 ;
    END
  END e_o[5]
  PIN e_o[60]
    DIRECTION OUTPUT ;
    USE SIGNAL ;
    PORT
      LAYER M5 ;
        RECT  21.456 0 21.48 0.192 ;
    END
  END e_o[60]
  PIN e_o[61]
    DIRECTION OUTPUT ;
    USE SIGNAL ;
    PORT
      LAYER M5 ;
        RECT  21.696 0 21.72 0.192 ;
    END
  END e_o[61]
  PIN e_o[62]
    DIRECTION OUTPUT ;
    USE SIGNAL ;
    PORT
      LAYER M5 ;
        RECT  21.984 0 22.008 0.192 ;
    END
  END e_o[62]
  PIN e_o[63]
    DIRECTION OUTPUT ;
    USE SIGNAL ;
    PORT
      LAYER M5 ;
        RECT  22.224 0 22.248 0.192 ;
    END
  END e_o[63]
  PIN e_o[64]
    DIRECTION OUTPUT ;
    USE SIGNAL ;
    PORT
      LAYER M5 ;
        RECT  22.464 0 22.488 0.192 ;
    END
  END e_o[64]
  PIN e_o[65]
    DIRECTION OUTPUT ;
    USE SIGNAL ;
    PORT
      LAYER M5 ;
        RECT  22.752 0 22.776 0.192 ;
    END
  END e_o[65]
  PIN e_o[66]
    DIRECTION OUTPUT ;
    USE SIGNAL ;
    PORT
      LAYER M5 ;
        RECT  22.992 0 23.016 0.192 ;
    END
  END e_o[66]
  PIN e_o[67]
    DIRECTION OUTPUT ;
    USE SIGNAL ;
    PORT
      LAYER M5 ;
        RECT  23.232 0 23.256 0.192 ;
    END
  END e_o[67]
  PIN e_o[68]
    DIRECTION OUTPUT ;
    USE SIGNAL ;
    PORT
      LAYER M5 ;
        RECT  23.472 0 23.496 0.192 ;
    END
  END e_o[68]
  PIN e_o[69]
    DIRECTION OUTPUT ;
    USE SIGNAL ;
    PORT
      LAYER M5 ;
        RECT  23.76 0 23.784 0.192 ;
    END
  END e_o[69]
  PIN e_o[6]
    DIRECTION OUTPUT ;
    USE SIGNAL ;
    PORT
      LAYER M5 ;
        RECT  7.728 0 7.752 0.192 ;
    END
  END e_o[6]
  PIN e_o[70]
    DIRECTION OUTPUT ;
    USE SIGNAL ;
    PORT
      LAYER M5 ;
        RECT  24 0 24.024 0.192 ;
    END
  END e_o[70]
  PIN e_o[71]
    DIRECTION OUTPUT ;
    USE SIGNAL ;
    PORT
      LAYER M5 ;
        RECT  24.24 0 24.264 0.192 ;
    END
  END e_o[71]
  PIN e_o[72]
    DIRECTION OUTPUT ;
    USE SIGNAL ;
    PORT
      LAYER M5 ;
        RECT  24.528 0 24.552 0.192 ;
    END
  END e_o[72]
  PIN e_o[73]
    DIRECTION OUTPUT ;
    USE SIGNAL ;
    PORT
      LAYER M5 ;
        RECT  24.768 0 24.792 0.192 ;
    END
  END e_o[73]
  PIN e_o[74]
    DIRECTION OUTPUT ;
    USE SIGNAL ;
    PORT
      LAYER M5 ;
        RECT  25.008 0 25.032 0.192 ;
    END
  END e_o[74]
  PIN e_o[75]
    DIRECTION OUTPUT ;
    USE SIGNAL ;
    PORT
      LAYER M5 ;
        RECT  25.296 0 25.32 0.192 ;
    END
  END e_o[75]
  PIN e_o[76]
    DIRECTION OUTPUT ;
    USE SIGNAL ;
    PORT
      LAYER M5 ;
        RECT  25.536 0 25.56 0.192 ;
    END
  END e_o[76]
  PIN e_o[77]
    DIRECTION OUTPUT ;
    USE SIGNAL ;
    PORT
      LAYER M5 ;
        RECT  25.776 0 25.8 0.192 ;
    END
  END e_o[77]
  PIN e_o[78]
    DIRECTION OUTPUT ;
    USE SIGNAL ;
    PORT
      LAYER M5 ;
        RECT  26.016 0 26.04 0.192 ;
    END
  END e_o[78]
  PIN e_o[79]
    DIRECTION OUTPUT ;
    USE SIGNAL ;
    PORT
      LAYER M5 ;
        RECT  26.304 0 26.328 0.192 ;
    END
  END e_o[79]
  PIN e_o[7]
    DIRECTION OUTPUT ;
    USE SIGNAL ;
    PORT
      LAYER M5 ;
        RECT  8.016 0 8.04 0.192 ;
    END
  END e_o[7]
  PIN e_o[80]
    DIRECTION OUTPUT ;
    USE SIGNAL ;
    PORT
      LAYER M5 ;
        RECT  26.544 0 26.568 0.192 ;
    END
  END e_o[80]
  PIN e_o[81]
    DIRECTION OUTPUT ;
    USE SIGNAL ;
    PORT
      LAYER M5 ;
        RECT  26.784 0 26.808 0.192 ;
    END
  END e_o[81]
  PIN e_o[82]
    DIRECTION OUTPUT ;
    USE SIGNAL ;
    PORT
      LAYER M5 ;
        RECT  27.072 0 27.096 0.192 ;
    END
  END e_o[82]
  PIN e_o[83]
    DIRECTION OUTPUT ;
    USE SIGNAL ;
    PORT
      LAYER M5 ;
        RECT  27.312 0 27.336 0.192 ;
    END
  END e_o[83]
  PIN e_o[84]
    DIRECTION OUTPUT ;
    USE SIGNAL ;
    PORT
      LAYER M5 ;
        RECT  27.552 0 27.576 0.192 ;
    END
  END e_o[84]
  PIN e_o[85]
    DIRECTION OUTPUT ;
    USE SIGNAL ;
    PORT
      LAYER M5 ;
        RECT  27.792 0 27.816 0.192 ;
    END
  END e_o[85]
  PIN e_o[86]
    DIRECTION OUTPUT ;
    USE SIGNAL ;
    PORT
      LAYER M5 ;
        RECT  28.08 0 28.104 0.192 ;
    END
  END e_o[86]
  PIN e_o[87]
    DIRECTION OUTPUT ;
    USE SIGNAL ;
    PORT
      LAYER M5 ;
        RECT  28.32 0 28.344 0.192 ;
    END
  END e_o[87]
  PIN e_o[88]
    DIRECTION OUTPUT ;
    USE SIGNAL ;
    PORT
      LAYER M5 ;
        RECT  28.56 0 28.584 0.192 ;
    END
  END e_o[88]
  PIN e_o[89]
    DIRECTION OUTPUT ;
    USE SIGNAL ;
    PORT
      LAYER M5 ;
        RECT  28.848 0 28.872 0.192 ;
    END
  END e_o[89]
  PIN e_o[8]
    DIRECTION OUTPUT ;
    USE SIGNAL ;
    PORT
      LAYER M5 ;
        RECT  8.256 0 8.28 0.192 ;
    END
  END e_o[8]
  PIN e_o[90]
    DIRECTION OUTPUT ;
    USE SIGNAL ;
    PORT
      LAYER M5 ;
        RECT  29.088 0 29.112 0.192 ;
    END
  END e_o[90]
  PIN e_o[91]
    DIRECTION OUTPUT ;
    USE SIGNAL ;
    PORT
      LAYER M5 ;
        RECT  29.328 0 29.352 0.192 ;
    END
  END e_o[91]
  PIN e_o[92]
    DIRECTION OUTPUT ;
    USE SIGNAL ;
    PORT
      LAYER M5 ;
        RECT  29.616 0 29.64 0.192 ;
    END
  END e_o[92]
  PIN e_o[93]
    DIRECTION OUTPUT ;
    USE SIGNAL ;
    PORT
      LAYER M5 ;
        RECT  29.856 0 29.88 0.192 ;
    END
  END e_o[93]
  PIN e_o[94]
    DIRECTION OUTPUT ;
    USE SIGNAL ;
    PORT
      LAYER M5 ;
        RECT  30.096 0 30.12 0.192 ;
    END
  END e_o[94]
  PIN e_o[95]
    DIRECTION OUTPUT ;
    USE SIGNAL ;
    PORT
      LAYER M5 ;
        RECT  30.336 0 30.36 0.192 ;
    END
  END e_o[95]
  PIN e_o[96]
    DIRECTION OUTPUT ;
    USE SIGNAL ;
    PORT
      LAYER M5 ;
        RECT  30.624 0 30.648 0.192 ;
    END
  END e_o[96]
  PIN e_o[97]
    DIRECTION OUTPUT ;
    USE SIGNAL ;
    PORT
      LAYER M5 ;
        RECT  30.864 0 30.888 0.192 ;
    END
  END e_o[97]
  PIN e_o[98]
    DIRECTION OUTPUT ;
    USE SIGNAL ;
    PORT
      LAYER M5 ;
        RECT  31.104 0 31.128 0.192 ;
    END
  END e_o[98]
  PIN e_o[99]
    DIRECTION OUTPUT ;
    USE SIGNAL ;
    PORT
      LAYER M5 ;
        RECT  31.392 0 31.416 0.192 ;
    END
  END e_o[99]
  PIN e_o[9]
    DIRECTION OUTPUT ;
    USE SIGNAL ;
    PORT
      LAYER M5 ;
        RECT  8.496 0 8.52 0.192 ;
    END
  END e_o[9]
  PIN p_i[0]
    DIRECTION INPUT ;
    USE SIGNAL ;
    PORT
      LAYER M5 ;
        RECT  4.176 14.928 4.2 15.12 ;
    END
  END p_i[0]
  PIN p_i[1]
    DIRECTION INPUT ;
    USE SIGNAL ;
    PORT
      LAYER M5 ;
        RECT  4.416 14.928 4.44 15.12 ;
    END
  END p_i[1]
  PIN p_i[2]
    DIRECTION INPUT ;
    USE SIGNAL ;
    PORT
      LAYER M5 ;
        RECT  4.704 14.928 4.728 15.12 ;
    END
  END p_i[2]
  PIN p_i[3]
    DIRECTION INPUT ;
    USE SIGNAL ;
    PORT
      LAYER M5 ;
        RECT  4.944 14.928 4.968 15.12 ;
    END
  END p_i[3]
  PIN p_i[4]
    DIRECTION INPUT ;
    USE SIGNAL ;
    PORT
      LAYER M5 ;
        RECT  5.184 14.928 5.208 15.12 ;
    END
  END p_i[4]
  PIN p_i[5]
    DIRECTION INPUT ;
    USE SIGNAL ;
    PORT
      LAYER M5 ;
        RECT  5.472 14.928 5.496 15.12 ;
    END
  END p_i[5]
  PIN p_i[6]
    DIRECTION INPUT ;
    USE SIGNAL ;
    PORT
      LAYER M5 ;
        RECT  5.712 14.928 5.736 15.12 ;
    END
  END p_i[6]
  PIN p_i[7]
    DIRECTION INPUT ;
    USE SIGNAL ;
    PORT
      LAYER M5 ;
        RECT  5.952 14.928 5.976 15.12 ;
    END
  END p_i[7]
  PIN p_o[0]
    DIRECTION OUTPUT ;
    USE SIGNAL ;
    PORT
      LAYER M5 ;
        RECT  4.176 0 4.2 0.192 ;
    END
  END p_o[0]
  PIN p_o[1]
    DIRECTION OUTPUT ;
    USE SIGNAL ;
    PORT
      LAYER M5 ;
        RECT  4.416 0 4.44 0.192 ;
    END
  END p_o[1]
  PIN p_o[2]
    DIRECTION OUTPUT ;
    USE SIGNAL ;
    PORT
      LAYER M5 ;
        RECT  4.704 0 4.728 0.192 ;
    END
  END p_o[2]
  PIN p_o[3]
    DIRECTION OUTPUT ;
    USE SIGNAL ;
    PORT
      LAYER M5 ;
        RECT  4.944 0 4.968 0.192 ;
    END
  END p_o[3]
  PIN p_o[4]
    DIRECTION OUTPUT ;
    USE SIGNAL ;
    PORT
      LAYER M5 ;
        RECT  5.184 0 5.208 0.192 ;
    END
  END p_o[4]
  PIN p_o[5]
    DIRECTION OUTPUT ;
    USE SIGNAL ;
    PORT
      LAYER M5 ;
        RECT  5.472 0 5.496 0.192 ;
    END
  END p_o[5]
  PIN p_o[6]
    DIRECTION OUTPUT ;
    USE SIGNAL ;
    PORT
      LAYER M5 ;
        RECT  5.712 0 5.736 0.192 ;
    END
  END p_o[6]
  PIN p_o[7]
    DIRECTION OUTPUT ;
    USE SIGNAL ;
    PORT
      LAYER M5 ;
        RECT  5.952 0 5.976 0.192 ;
    END
  END p_o[7]
  PIN sk
    DIRECTION INPUT ;
    USE SIGNAL ;
    PORT
      LAYER M4 ;
        RECT  0 0.576 0.192 0.6 ;
    END
  END sk
  PIN srs
    DIRECTION INPUT ;
    USE SIGNAL ;
    PORT
      LAYER M4 ;
        RECT  0 1.248 0.192 1.272 ;
    END
  END srs
  PIN v_i[0]
    DIRECTION INPUT ;
    USE SIGNAL ;
    PORT
      LAYER M5 ;
        RECT  2.16 14.928 2.184 15.12 ;
    END
  END v_i[0]
  PIN v_i[1]
    DIRECTION INPUT ;
    USE SIGNAL ;
    PORT
      LAYER M5 ;
        RECT  2.4 14.928 2.424 15.12 ;
    END
  END v_i[1]
  PIN v_i[2]
    DIRECTION INPUT ;
    USE SIGNAL ;
    PORT
      LAYER M5 ;
        RECT  2.64 14.928 2.664 15.12 ;
    END
  END v_i[2]
  PIN v_i[3]
    DIRECTION INPUT ;
    USE SIGNAL ;
    PORT
      LAYER M5 ;
        RECT  2.928 14.928 2.952 15.12 ;
    END
  END v_i[3]
  PIN v_i[4]
    DIRECTION INPUT ;
    USE SIGNAL ;
    PORT
      LAYER M5 ;
        RECT  3.168 14.928 3.192 15.12 ;
    END
  END v_i[4]
  PIN v_i[5]
    DIRECTION INPUT ;
    USE SIGNAL ;
    PORT
      LAYER M5 ;
        RECT  3.408 14.928 3.432 15.12 ;
    END
  END v_i[5]
  PIN v_i[6]
    DIRECTION INPUT ;
    USE SIGNAL ;
    PORT
      LAYER M5 ;
        RECT  3.696 14.928 3.72 15.12 ;
    END
  END v_i[6]
  PIN v_i[7]
    DIRECTION INPUT ;
    USE SIGNAL ;
    PORT
      LAYER M5 ;
        RECT  3.936 14.928 3.96 15.12 ;
    END
  END v_i[7]
  PIN v_o[0]
    DIRECTION OUTPUT ;
    USE SIGNAL ;
    PORT
      LAYER M5 ;
        RECT  2.16 0 2.184 0.192 ;
    END
  END v_o[0]
  PIN v_o[1]
    DIRECTION OUTPUT ;
    USE SIGNAL ;
    PORT
      LAYER M5 ;
        RECT  2.4 0 2.424 0.192 ;
    END
  END v_o[1]
  PIN v_o[2]
    DIRECTION OUTPUT ;
    USE SIGNAL ;
    PORT
      LAYER M5 ;
        RECT  2.64 0 2.664 0.192 ;
    END
  END v_o[2]
  PIN v_o[3]
    DIRECTION OUTPUT ;
    USE SIGNAL ;
    PORT
      LAYER M5 ;
        RECT  2.928 0 2.952 0.192 ;
    END
  END v_o[3]
  PIN v_o[4]
    DIRECTION OUTPUT ;
    USE SIGNAL ;
    PORT
      LAYER M5 ;
        RECT  3.168 0 3.192 0.192 ;
    END
  END v_o[4]
  PIN v_o[5]
    DIRECTION OUTPUT ;
    USE SIGNAL ;
    PORT
      LAYER M5 ;
        RECT  3.408 0 3.432 0.192 ;
    END
  END v_o[5]
  PIN v_o[6]
    DIRECTION OUTPUT ;
    USE SIGNAL ;
    PORT
      LAYER M5 ;
        RECT  3.696 0 3.72 0.192 ;
    END
  END v_o[6]
  PIN v_o[7]
    DIRECTION OUTPUT ;
    USE SIGNAL ;
    PORT
      LAYER M5 ;
        RECT  3.936 0 3.96 0.192 ;
    END
  END v_o[7]
  PIN VDD
    DIRECTION INOUT ;
    USE POWER ;
    PORT
      LAYER M5 ;
        RECT  132.192 2.151 132.312 12.969 ;
        RECT  126.792 2.151 126.912 12.969 ;
        RECT  121.392 2.151 121.512 12.969 ;
        RECT  115.992 2.151 116.112 12.969 ;
        RECT  110.592 2.151 110.712 12.969 ;
        RECT  105.192 2.151 105.312 12.969 ;
        RECT  99.792 2.151 99.912 12.969 ;
        RECT  94.392 2.151 94.512 12.969 ;
        RECT  88.992 2.151 89.112 12.969 ;
        RECT  83.592 2.151 83.712 12.969 ;
        RECT  78.192 2.151 78.312 12.969 ;
        RECT  72.792 2.151 72.912 12.969 ;
        RECT  67.392 2.151 67.512 12.969 ;
        RECT  61.992 2.151 62.112 12.969 ;
        RECT  56.592 2.151 56.712 12.969 ;
        RECT  51.192 2.151 51.312 12.969 ;
        RECT  45.792 2.151 45.912 12.969 ;
        RECT  40.392 2.151 40.512 12.969 ;
        RECT  34.992 2.151 35.112 12.969 ;
        RECT  29.592 2.151 29.712 12.969 ;
        RECT  24.192 2.151 24.312 12.969 ;
        RECT  18.792 2.151 18.912 12.969 ;
        RECT  13.392 2.151 13.512 12.969 ;
        RECT  7.992 2.151 8.112 12.969 ;
        RECT  2.592 2.151 2.712 12.969 ;
    END
  END VDD
  PIN VSS
    DIRECTION INOUT ;
    USE GROUND ;
    PORT
      LAYER M5 ;
        RECT  132 2.137 132.12 12.983 ;
        RECT  126.6 2.137 126.72 12.983 ;
        RECT  121.2 2.137 121.32 12.983 ;
        RECT  115.8 2.137 115.92 12.983 ;
        RECT  110.4 2.137 110.52 12.983 ;
        RECT  105 2.137 105.12 12.983 ;
        RECT  99.6 2.137 99.72 12.983 ;
        RECT  94.2 2.137 94.32 12.983 ;
        RECT  88.8 2.137 88.92 12.983 ;
        RECT  83.4 2.137 83.52 12.983 ;
        RECT  78 2.137 78.12 12.983 ;
        RECT  72.6 2.137 72.72 12.983 ;
        RECT  67.2 2.137 67.32 12.983 ;
        RECT  61.8 2.137 61.92 12.983 ;
        RECT  56.4 2.137 56.52 12.983 ;
        RECT  51 2.137 51.12 12.983 ;
        RECT  45.6 2.137 45.72 12.983 ;
        RECT  40.2 2.137 40.32 12.983 ;
        RECT  34.8 2.137 34.92 12.983 ;
        RECT  29.4 2.137 29.52 12.983 ;
        RECT  24 2.137 24.12 12.983 ;
        RECT  18.6 2.137 18.72 12.983 ;
        RECT  13.2 2.137 13.32 12.983 ;
        RECT  7.8 2.137 7.92 12.983 ;
        RECT  2.4 2.137 2.52 12.983 ;
    END
  END VSS
  OBS
    LAYER RVTN ;
     RECT  2.16 2.16 136.08 2.295 ;
     RECT  2.16 2.565 136.08 2.835 ;
     RECT  2.16 3.105 136.08 3.375 ;
     RECT  2.16 3.645 136.08 3.915 ;
     RECT  2.16 4.185 136.08 4.455 ;
     RECT  2.16 4.725 136.08 4.995 ;
     RECT  2.16 5.265 136.08 5.535 ;
     RECT  2.16 5.805 136.08 6.075 ;
     RECT  2.16 6.345 136.08 6.615 ;
     RECT  2.16 6.885 136.08 7.155 ;
     RECT  2.16 7.425 136.08 7.695 ;
     RECT  2.16 7.965 136.08 8.235 ;
     RECT  2.16 8.505 136.08 8.775 ;
     RECT  2.16 9.045 136.08 9.315 ;
     RECT  2.16 9.585 136.08 9.855 ;
     RECT  2.16 10.125 136.08 10.395 ;
     RECT  2.16 10.665 136.08 10.935 ;
     RECT  2.16 11.205 136.08 11.475 ;
     RECT  2.16 11.745 136.08 12.015 ;
     RECT  2.16 12.285 136.08 12.555 ;
     RECT  2.16 12.825 136.08 12.96 ;
    LAYER RVTP ;
     RECT  2.16 2.295 136.08 2.565 ;
     RECT  2.16 2.835 136.08 3.105 ;
     RECT  2.16 3.375 136.08 3.645 ;
     RECT  2.16 3.915 136.08 4.185 ;
     RECT  2.16 4.455 136.08 4.725 ;
     RECT  2.16 4.995 136.08 5.265 ;
     RECT  2.16 5.535 136.08 5.805 ;
     RECT  2.16 6.075 136.08 6.345 ;
     RECT  2.16 6.615 136.08 6.885 ;
     RECT  2.16 7.155 136.08 7.425 ;
     RECT  2.16 7.695 136.08 7.965 ;
     RECT  2.16 8.235 136.08 8.505 ;
     RECT  2.16 8.775 136.08 9.045 ;
     RECT  2.16 9.315 136.08 9.585 ;
     RECT  2.16 9.855 136.08 10.125 ;
     RECT  2.16 10.395 136.08 10.665 ;
     RECT  2.16 10.935 136.08 11.205 ;
     RECT  2.16 11.475 136.08 11.745 ;
     RECT  2.16 12.015 136.08 12.285 ;
     RECT  2.16 12.555 136.08 12.825 ;
    LAYER M1 ;
     RECT  2.16 2.151 136.08 12.969 ;
    LAYER M2 ;
     RECT  2.16 2.151 10.039 12.969 ;
     RECT  10.039 2.106 10.535 12.969 ;
     RECT  10.535 2.151 29.623 12.969 ;
     RECT  29.623 2.106 30.515 12.969 ;
     RECT  30.515 2.151 34.699 12.969 ;
     RECT  34.699 2.106 35.123 12.969 ;
     RECT  35.123 2.151 37.003 12.969 ;
     RECT  37.003 2.106 37.427 12.969 ;
     RECT  37.427 2.151 53.527 12.969 ;
     RECT  53.527 2.106 53.843 12.969 ;
     RECT  53.843 2.151 64.903 12.969 ;
     RECT  64.903 2.106 65.255 12.969 ;
     RECT  65.255 2.151 90.607 12.969 ;
     RECT  90.607 2.106 91.103 12.969 ;
     RECT  91.103 2.151 125.671 12.969 ;
     RECT  125.671 2.106 127.283 12.969 ;
     RECT  127.283 2.151 129.235 12.969 ;
     RECT  129.235 2.106 129.839 12.969 ;
     RECT  129.839 2.151 133.807 12.969 ;
     RECT  133.807 2.106 134.195 12.969 ;
     RECT  134.195 2.151 136.08 12.969 ;
    LAYER M3 ;
     RECT  9.72 0.187 9.738 0.235 ;
     RECT  18.936 0.187 19.458 0.235 ;
     RECT  20.628 0.187 20.646 0.235 ;
     RECT  21.708 0.187 22.194 0.235 ;
     RECT  26.82 0.187 27.27 0.235 ;
     RECT  32.076 0.187 32.094 0.235 ;
     RECT  42.228 0.187 42.246 0.235 ;
     RECT  43.092 0.187 43.11 0.235 ;
     RECT  44.496 0.187 45.126 0.235 ;
     RECT  46.26 0.187 46.278 0.235 ;
     RECT  49.932 0.187 50.454 0.235 ;
     RECT  56.916 0.187 56.934 0.235 ;
     RECT  95.076 0.187 95.094 0.235 ;
     RECT  96.048 0.187 98.73 0.235 ;
     RECT  99.468 0.187 99.486 0.235 ;
     RECT  106.2 0.187 107.046 0.235 ;
     RECT  107.892 0.187 108.882 0.235 ;
     RECT  110.088 0.187 110.106 0.235 ;
     RECT  112.644 0.187 113.202 0.235 ;
     RECT  114.228 0.187 115.794 0.235 ;
     RECT  116.568 0.187 117.558 0.235 ;
     RECT  123.012 0.187 124.578 0.235 ;
     RECT  125.424 0.187 125.442 0.235 ;
     RECT  126.18 0.187 127.17 0.235 ;
     RECT  134.568 0.187 135.486 0.235 ;
     RECT  10.944 0.187 11.61 0.283 ;
     RECT  7.452 0.187 7.47 0.523 ;
     RECT  122.94 0.235 124.578 0.523 ;
     RECT  125.424 0.235 127.17 0.523 ;
     RECT  3.456 0.187 3.474 0.571 ;
     RECT  4.608 0.187 4.626 0.571 ;
     RECT  9.72 0.235 9.99 0.571 ;
     RECT  10.908 0.283 11.61 0.571 ;
     RECT  12.96 0.187 13.878 0.571 ;
     RECT  24.516 0.187 25.434 0.571 ;
     RECT  26.82 0.235 27.666 0.571 ;
     RECT  35.352 0.187 35.37 0.571 ;
     RECT  40.752 0.475 40.77 0.571 ;
     RECT  42.228 0.235 43.11 0.571 ;
     RECT  44.496 0.235 45.378 0.571 ;
     RECT  46.26 0.235 46.566 0.571 ;
     RECT  49.932 0.235 50.706 0.571 ;
     RECT  51.48 0.187 52.506 0.571 ;
     RECT  53.28 0.187 54.018 0.571 ;
     RECT  62.244 0.187 62.91 0.571 ;
     RECT  64.44 0.187 64.458 0.571 ;
     RECT  65.664 0.187 67.554 0.571 ;
     RECT  69.228 0.187 69.246 0.571 ;
     RECT  70.56 0.187 70.578 0.571 ;
     RECT  71.316 0.187 71.334 0.571 ;
     RECT  72.504 0.187 72.522 0.571 ;
     RECT  75.384 0.187 75.402 0.571 ;
     RECT  76.14 0.187 76.158 0.571 ;
     RECT  81.684 0.187 81.702 0.571 ;
     RECT  82.656 0.187 83.25 0.571 ;
     RECT  84.708 0.187 84.726 0.571 ;
     RECT  87.48 0.187 87.498 0.571 ;
     RECT  88.272 0.187 88.29 0.571 ;
     RECT  89.892 0.187 89.91 0.571 ;
     RECT  92.016 0.187 92.574 0.571 ;
     RECT  93.528 0.187 94.086 0.571 ;
     RECT  106.2 0.235 108.882 0.571 ;
     RECT  110.088 0.235 110.394 0.571 ;
     RECT  111.168 0.187 111.798 0.571 ;
     RECT  112.572 0.235 113.202 0.571 ;
     RECT  114.228 0.235 117.558 0.571 ;
     RECT  120.42 0.187 122.094 0.571 ;
     RECT  122.94 0.523 127.17 0.571 ;
     RECT  128.16 0.187 131.13 0.571 ;
     RECT  134.568 0.235 135.702 0.571 ;
     RECT  24.516 0.571 25.974 0.619 ;
     RECT  26.82 0.571 27.774 0.619 ;
     RECT  2.808 0.571 3.474 1.147 ;
     RECT  4.608 0.571 4.878 1.147 ;
     RECT  6.876 0.523 7.47 1.147 ;
     RECT  8.676 0.187 8.694 1.147 ;
     RECT  9.72 0.571 11.61 1.147 ;
     RECT  16.2 0.187 16.218 1.147 ;
     RECT  17.856 0.187 17.874 1.147 ;
     RECT  20.628 0.235 22.482 1.147 ;
     RECT  24.516 0.619 27.774 1.147 ;
     RECT  29.268 0.571 29.286 1.147 ;
     RECT  30.924 0.187 30.942 1.147 ;
     RECT  32.004 0.235 32.094 1.147 ;
     RECT  35.352 0.571 35.766 1.147 ;
     RECT  37.836 0.187 37.854 1.147 ;
     RECT  38.664 0.571 38.682 1.147 ;
     RECT  42.228 0.571 46.566 1.147 ;
     RECT  47.412 0.187 48.114 1.147 ;
     RECT  49.068 0.187 49.086 1.147 ;
     RECT  49.932 0.571 54.018 1.147 ;
     RECT  55.404 0.187 56.178 1.147 ;
     RECT  56.916 0.235 57.042 1.147 ;
     RECT  57.816 0.187 58.878 1.147 ;
     RECT  59.976 0.187 60.498 1.147 ;
     RECT  62.244 0.571 63.666 1.147 ;
     RECT  64.44 0.571 64.818 1.147 ;
     RECT  65.664 0.571 69.246 1.147 ;
     RECT  70.56 0.571 71.334 1.147 ;
     RECT  76.14 0.571 76.266 1.147 ;
     RECT  77.004 0.187 77.022 1.147 ;
     RECT  78.66 0.187 78.678 1.147 ;
     RECT  79.74 0.571 80.298 1.147 ;
     RECT  81.252 0.571 81.702 1.147 ;
     RECT  82.656 0.571 83.754 1.147 ;
     RECT  84.708 0.571 86.526 1.147 ;
     RECT  88.272 0.571 92.574 1.147 ;
     RECT  93.456 0.571 94.086 1.147 ;
     RECT  2.808 1.147 5.994 1.723 ;
     RECT  6.732 1.147 8.694 1.723 ;
     RECT  9.432 1.147 11.61 1.723 ;
     RECT  12.348 0.571 13.914 1.723 ;
     RECT  15.12 0.187 15.138 1.723 ;
     RECT  16.164 1.147 17.874 1.723 ;
     RECT  18.936 0.235 19.818 1.723 ;
     RECT  20.628 1.147 22.734 1.723 ;
     RECT  24.444 1.147 29.286 1.723 ;
     RECT  30.924 1.147 32.094 1.723 ;
     RECT  32.868 1.147 36.342 1.723 ;
     RECT  37.368 1.147 38.682 1.723 ;
     RECT  40.716 0.571 41.31 1.723 ;
     RECT  42.156 1.147 48.114 1.723 ;
     RECT  49.068 1.147 54.018 1.723 ;
     RECT  55.08 1.147 57.042 1.723 ;
     RECT  57.816 1.147 60.498 1.723 ;
     RECT  61.272 1.147 64.818 1.723 ;
     RECT  65.664 1.147 69.462 1.723 ;
     RECT  70.56 1.147 71.442 1.723 ;
     RECT  72.288 0.571 73.71 1.723 ;
     RECT  75.096 0.571 75.402 1.723 ;
     RECT  76.14 1.147 77.022 1.723 ;
     RECT  77.976 1.147 78.678 1.723 ;
     RECT  79.74 1.147 81.702 1.723 ;
     RECT  82.656 1.147 86.526 1.723 ;
     RECT  87.408 0.571 87.498 1.723 ;
     RECT  88.272 1.147 94.086 1.723 ;
     RECT  95.076 0.235 100.026 1.723 ;
     RECT  100.764 0.187 105.462 1.723 ;
     RECT  106.2 0.571 109.134 1.723 ;
     RECT  110.088 0.571 111.798 1.723 ;
     RECT  112.572 0.571 117.558 1.723 ;
     RECT  118.476 0.187 119.322 1.723 ;
     RECT  120.42 0.571 131.13 1.723 ;
     RECT  131.976 0.187 133.038 1.723 ;
     RECT  134.136 0.571 135.702 1.723 ;
     RECT  2.196 1.723 5.994 1.771 ;
     RECT  6.732 1.723 14.382 1.771 ;
     RECT  15.12 1.723 23.706 1.771 ;
     RECT  24.444 1.723 135.882 1.771 ;
     RECT  2.196 1.771 14.382 2.155 ;
     RECT  15.12 1.771 135.882 2.155 ;
     RECT  2.196 2.155 135.882 2.767 ;
     RECT  2.196 2.767 135.918 2.875 ;
     RECT  2.196 2.875 135.954 3.029 ;
     RECT  2.304 3.029 135.954 3.299 ;
     RECT  2.304 3.299 135.918 3.335 ;
     RECT  2.376 3.335 135.918 4.181 ;
     RECT  2.376 4.181 135.882 4.939 ;
     RECT  2.34 4.939 135.882 4.987 ;
     RECT  2.268 4.987 135.882 5.027 ;
     RECT  2.34 5.027 135.882 5.459 ;
     RECT  2.34 5.459 135.774 5.801 ;
     RECT  2.34 5.801 116.91 6.107 ;
     RECT  114.012 6.107 116.91 6.655 ;
     RECT  117.684 5.801 135.774 6.655 ;
     RECT  2.34 6.107 113.274 6.809 ;
     RECT  2.34 6.809 65.106 6.845 ;
     RECT  114.012 6.655 135.81 6.853 ;
     RECT  65.844 6.809 113.274 7.231 ;
     RECT  114.012 6.853 135.846 7.231 ;
     RECT  65.844 7.231 135.882 7.349 ;
     RECT  2.34 6.845 65.07 7.385 ;
     RECT  5.148 7.385 65.07 7.627 ;
     RECT  65.844 7.349 135.846 7.627 ;
     RECT  2.34 7.385 4.266 8.131 ;
     RECT  5.148 7.627 135.846 8.131 ;
     RECT  2.34 8.131 135.846 10.093 ;
     RECT  2.34 10.093 135.882 10.253 ;
     RECT  48.636 10.253 135.882 10.493 ;
     RECT  2.34 10.253 47.79 10.589 ;
     RECT  48.636 10.493 108.522 10.589 ;
     RECT  109.692 10.493 135.882 10.589 ;
     RECT  2.34 10.589 27.306 10.597 ;
     RECT  2.304 10.597 27.306 10.625 ;
     RECT  60.84 10.589 108.522 10.625 ;
     RECT  29.196 10.589 47.79 10.781 ;
     RECT  60.84 10.625 103.086 10.829 ;
     RECT  103.86 10.625 108.522 10.829 ;
     RECT  48.636 10.589 60.102 10.859 ;
     RECT  109.692 10.589 135.846 10.859 ;
     RECT  82.548 10.829 102.726 10.877 ;
     RECT  119.592 10.859 135.846 10.967 ;
     RECT  119.592 10.967 124.974 11.021 ;
     RECT  2.304 10.625 10.566 11.129 ;
     RECT  55.62 10.859 60.102 11.129 ;
     RECT  125.928 10.967 135.846 11.129 ;
     RECT  112.392 10.859 118.746 11.165 ;
     RECT  119.628 11.021 124.974 11.237 ;
     RECT  112.392 11.165 117.702 11.309 ;
     RECT  28.116 10.589 28.386 11.515 ;
     RECT  29.196 10.781 33.066 11.515 ;
     RECT  55.656 11.129 60.102 11.515 ;
     RECT  60.84 10.829 70.938 11.515 ;
     RECT  97.524 10.877 102.726 11.669 ;
     RECT  112.392 11.309 117.594 11.669 ;
     RECT  82.548 10.877 96.498 11.785 ;
     RECT  97.524 11.669 102.618 11.785 ;
     RECT  28.116 11.515 33.066 11.821 ;
     RECT  33.84 10.781 47.79 11.821 ;
     RECT  48.744 10.859 54.81 11.821 ;
     RECT  55.656 11.515 70.938 11.849 ;
     RECT  71.784 10.829 81.774 11.849 ;
     RECT  107.28 10.829 108.522 11.983 ;
     RECT  2.304 11.129 8.694 11.995 ;
     RECT  9.432 11.129 10.566 11.995 ;
     RECT  11.304 10.625 27.306 11.995 ;
     RECT  28.116 11.821 54.81 11.995 ;
     RECT  71.892 11.849 81.774 11.995 ;
     RECT  82.548 11.785 102.618 11.995 ;
     RECT  103.86 10.829 106.434 11.995 ;
     RECT  107.28 11.983 108.594 11.995 ;
     RECT  112.392 11.669 117.45 11.995 ;
     RECT  118.476 11.165 118.746 11.995 ;
     RECT  2.304 11.995 27.306 12.047 ;
     RECT  103.608 11.995 108.594 12.325 ;
     RECT  112.356 11.995 117.45 12.325 ;
     RECT  118.368 11.995 118.746 12.325 ;
     RECT  125.928 11.129 135.738 12.325 ;
     RECT  15.768 12.047 27.306 12.361 ;
     RECT  28.08 11.995 54.81 12.361 ;
     RECT  70.236 11.849 70.938 12.361 ;
     RECT  119.772 11.237 124.974 12.361 ;
     RECT  70.236 12.361 71.118 12.479 ;
     RECT  112.284 12.325 117.45 12.487 ;
     RECT  118.224 12.325 118.746 12.517 ;
     RECT  15.768 12.361 54.81 12.523 ;
     RECT  103.608 12.325 108.702 12.523 ;
     RECT  109.728 10.859 111.402 12.523 ;
     RECT  112.248 12.487 117.45 12.523 ;
     RECT  118.224 12.517 118.998 12.523 ;
     RECT  15.768 12.523 54.846 12.557 ;
     RECT  55.656 11.849 69.282 12.557 ;
     RECT  125.892 12.325 135.738 12.557 ;
     RECT  103.356 12.523 117.45 12.571 ;
     RECT  118.188 12.523 118.998 12.571 ;
     RECT  119.772 12.361 125.01 12.571 ;
     RECT  125.892 12.557 129.51 12.571 ;
     RECT  130.32 12.557 135.738 12.571 ;
     RECT  15.768 12.557 23.094 12.605 ;
     RECT  71.892 11.995 102.618 12.721 ;
     RECT  103.356 12.571 125.01 12.721 ;
     RECT  2.304 12.047 15.03 12.749 ;
     RECT  15.768 12.605 22.41 12.749 ;
     RECT  23.904 12.557 24.498 12.749 ;
     RECT  25.236 12.557 26.658 12.749 ;
     RECT  29.34 12.557 42.786 12.749 ;
     RECT  43.92 12.557 54.846 12.749 ;
     RECT  55.656 12.557 60.21 12.749 ;
     RECT  63.648 12.557 64.314 12.749 ;
     RECT  65.088 12.557 67.554 12.749 ;
     RECT  68.4 12.557 69.282 12.749 ;
     RECT  70.236 12.479 71.046 12.749 ;
     RECT  71.892 12.721 125.01 12.749 ;
     RECT  125.82 12.571 129.51 12.749 ;
     RECT  130.32 12.571 135.81 12.749 ;
     RECT  2.304 12.749 11.322 12.757 ;
     RECT  2.268 12.757 11.322 12.797 ;
     RECT  38.448 12.749 40.878 12.821 ;
     RECT  72.216 12.749 123.642 12.821 ;
     RECT  29.34 12.749 37.638 12.857 ;
     RECT  72.216 12.821 105.498 12.857 ;
     RECT  12.06 12.749 15.03 12.865 ;
     RECT  15.768 12.749 19.098 12.865 ;
     RECT  55.656 12.749 60.102 12.865 ;
     RECT  68.508 12.749 69.282 12.865 ;
     RECT  124.56 12.749 125.01 12.865 ;
     RECT  125.82 12.749 129.474 12.865 ;
     RECT  65.088 12.749 67.446 12.929 ;
     RECT  77.148 12.857 101.466 12.929 ;
     RECT  2.34 12.797 11.322 12.941 ;
     RECT  12.06 12.865 19.098 12.941 ;
     RECT  19.944 12.749 22.41 12.941 ;
     RECT  25.308 12.749 26.658 12.941 ;
     RECT  27.72 12.557 28.494 12.941 ;
     RECT  29.34 12.857 36.45 12.941 ;
     RECT  37.188 12.857 37.638 12.941 ;
     RECT  38.484 12.821 40.878 12.941 ;
     RECT  41.616 12.749 42.786 12.941 ;
     RECT  43.92 12.749 46.386 12.941 ;
     RECT  47.124 12.749 53.946 12.941 ;
     RECT  54.9 12.865 60.102 12.941 ;
     RECT  61.092 12.557 62.622 12.941 ;
     RECT  65.088 12.929 65.106 12.941 ;
     RECT  66.06 12.929 67.446 12.941 ;
     RECT  68.508 12.865 69.642 12.941 ;
     RECT  70.56 12.749 71.046 12.941 ;
     RECT  72.216 12.857 76.41 12.941 ;
     RECT  77.148 12.929 94.554 12.941 ;
     RECT  95.544 12.929 101.466 12.941 ;
     RECT  102.348 12.857 105.498 12.941 ;
     RECT  106.236 12.821 123.642 12.941 ;
     RECT  124.56 12.865 129.474 12.941 ;
     RECT  130.32 12.749 135.702 12.941 ;
     RECT  12.564 12.941 13.374 12.977 ;
     RECT  29.34 12.941 29.505 12.977 ;
     RECT  34.815 12.941 34.974 12.977 ;
     RECT  40.215 12.941 40.878 12.977 ;
     RECT  67.215 12.941 67.446 12.977 ;
     RECT  78.015 12.941 78.174 12.977 ;
     RECT  103.644 12.941 105.354 12.977 ;
     RECT  115.776 12.941 115.905 12.977 ;
     RECT  126.615 12.941 127.53 12.977 ;
     RECT  131.256 12.941 132.105 12.977 ;
     RECT  20.268 12.941 20.286 12.989 ;
     RECT  2.34 12.941 2.646 13.085 ;
     RECT  7.632 12.941 8.154 13.085 ;
     RECT  18.576 12.941 18.954 13.085 ;
     RECT  40.428 12.977 40.878 13.085 ;
     RECT  45 12.941 46.386 13.085 ;
     RECT  47.124 12.941 47.61 13.085 ;
     RECT  48.636 12.941 48.654 13.085 ;
     RECT  50.904 12.941 53.55 13.085 ;
     RECT  67.428 12.977 67.446 13.085 ;
     RECT  72.216 12.941 73.386 13.085 ;
     RECT  83.124 12.941 83.682 13.085 ;
     RECT  88.776 12.941 89.082 13.085 ;
     RECT  94.176 12.941 94.374 13.085 ;
     RECT  105.156 12.977 105.354 13.085 ;
     RECT  115.776 12.977 115.794 13.085 ;
     RECT  121.14 12.941 123.642 13.085 ;
     RECT  126.756 12.977 127.53 13.085 ;
     RECT  2.34 13.085 2.358 13.133 ;
     RECT  13.356 12.977 13.374 13.133 ;
     RECT  18.576 13.085 18.594 13.133 ;
     RECT  23.976 12.749 24.498 13.133 ;
     RECT  34.956 12.977 34.974 13.133 ;
     RECT  45 13.085 45.594 13.133 ;
     RECT  61.74 12.941 61.974 13.133 ;
     RECT  78.156 12.977 78.174 13.133 ;
     RECT  83.124 13.085 83.394 13.133 ;
     RECT  88.776 13.085 88.794 13.133 ;
     RECT  98.568 12.941 99.774 13.133 ;
     RECT  105.156 13.085 105.174 13.133 ;
     RECT  121.356 13.085 123.642 13.133 ;
     RECT  126.756 13.085 126.774 13.133 ;
     RECT  131.256 12.977 131.994 13.133 ;
     RECT  21.996 12.941 22.014 13.709 ;
     RECT  25.632 12.941 26.658 13.709 ;
     RECT  30.708 12.941 30.762 13.709 ;
     RECT  47.592 13.085 47.61 13.709 ;
     RECT  50.076 12.941 50.094 13.709 ;
     RECT  56.376 12.941 57.042 13.709 ;
     RECT  61.74 13.133 61.758 13.709 ;
     RECT  71.028 12.941 71.046 13.709 ;
     RECT  98.568 13.133 99.126 13.709 ;
     RECT  103.644 12.977 104.346 13.709 ;
     RECT  108.684 12.941 108.702 13.709 ;
     RECT  109.98 12.941 110.574 13.709 ;
     RECT  112.824 12.941 112.842 13.709 ;
     RECT  114.552 12.941 114.57 13.709 ;
     RECT  119.772 12.941 120.15 13.709 ;
     RECT  121.896 13.133 123.642 13.709 ;
     RECT  127.512 13.085 127.53 13.709 ;
     RECT  133.884 12.941 133.902 13.709 ;
     RECT  3.384 12.941 3.402 14.285 ;
     RECT  8.136 13.085 8.154 14.285 ;
     RECT  12.564 12.977 12.582 14.285 ;
     RECT  14.292 12.941 14.814 14.285 ;
     RECT  15.948 12.941 15.966 14.285 ;
     RECT  17.532 12.941 17.55 14.285 ;
     RECT  21.24 12.941 21.258 14.285 ;
     RECT  24.48 13.133 24.498 14.285 ;
     RECT  25.632 13.709 25.65 14.285 ;
     RECT  26.64 13.709 26.658 14.285 ;
     RECT  28.476 12.941 28.494 14.285 ;
     RECT  29.34 12.977 29.358 14.285 ;
     RECT  30.708 13.709 30.726 14.285 ;
     RECT  32.112 12.941 32.13 14.285 ;
     RECT  38.988 12.941 39.438 14.285 ;
     RECT  40.86 13.085 40.878 14.285 ;
     RECT  42.156 12.941 42.786 14.285 ;
     RECT  45 13.133 45.018 14.285 ;
     RECT  51.768 13.085 53.55 14.285 ;
     RECT  57.024 13.709 57.042 14.285 ;
     RECT  59.22 12.941 59.598 14.285 ;
     RECT  63.792 12.749 64.314 14.285 ;
     RECT  66.06 12.941 66.078 14.285 ;
     RECT  68.832 12.941 69.03 14.285 ;
     RECT  72.216 13.085 72.234 14.285 ;
     RECT  73.368 13.085 73.386 14.285 ;
     RECT  80.316 12.941 80.334 14.285 ;
     RECT  83.124 13.133 83.142 14.285 ;
     RECT  96.912 12.941 96.93 14.285 ;
     RECT  99.108 13.709 99.126 14.285 ;
     RECT  101.448 12.941 101.466 14.285 ;
     RECT  102.6 12.941 102.618 14.285 ;
     RECT  104.328 13.709 104.346 14.285 ;
     RECT  117.432 12.941 117.45 14.285 ;
     RECT  119.772 13.709 119.79 14.285 ;
     RECT  123.12 13.709 123.642 14.285 ;
     RECT  124.56 12.941 124.578 14.285 ;
     RECT  131.256 13.133 131.274 14.285 ;
     RECT  68.832 14.285 68.85 14.333 ;
     RECT  11.592 14.875 11.61 15.005 ;
     RECT  25.056 14.875 25.074 15.005 ;
     RECT  28.872 14.875 28.89 15.005 ;
     RECT  36.684 14.875 36.702 15.005 ;
     RECT  39.996 14.875 40.014 15.005 ;
     RECT  46.944 14.875 48.15 15.005 ;
     RECT  61.308 14.875 61.326 15.005 ;
     RECT  64.872 14.875 64.89 15.005 ;
     RECT  69.732 14.875 69.75 15.005 ;
     RECT  74.268 14.875 74.286 15.005 ;
     RECT  76.572 14.875 76.59 15.005 ;
     RECT  77.364 14.875 77.382 15.005 ;
     RECT  113.148 14.875 113.166 15.005 ;
    LAYER M4 ;
     RECT  0.156 0.576 0.275 1.272 ;
     RECT  0.275 1.248 0.371 1.272 ;
     RECT  0.325 2.928 2.329 2.952 ;
     RECT  2.257 4.992 2.329 5.016 ;
     RECT  2.149 12.768 2.329 12.792 ;
     RECT  2.141 1.728 2.408 1.752 ;
     RECT  2.329 2.832 2.408 2.952 ;
     RECT  2.329 4.944 2.408 5.016 ;
     RECT  0.229 6.384 2.408 6.408 ;
     RECT  2.329 12.768 2.408 13.128 ;
     RECT  2.408 1.728 2.435 13.128 ;
     RECT  2.435 1.728 2.675 13.08 ;
     RECT  2.675 1.728 2.704 12.936 ;
     RECT  2.389 0.576 3.157 0.6 ;
     RECT  3.356 14.256 3.443 14.28 ;
     RECT  2.704 6.384 3.529 6.84 ;
     RECT  3.157 0.192 3.685 0.6 ;
     RECT  2.704 1.728 3.685 1.8 ;
     RECT  2.704 7.872 3.805 7.896 ;
     RECT  3.685 0.192 3.845 1.8 ;
     RECT  2.704 4.176 3.989 5.016 ;
     RECT  2.704 12.528 4.012 12.936 ;
     RECT  3.989 4.176 4.021 4.968 ;
     RECT  3.805 7.872 4.277 8.568 ;
     RECT  2.704 2.832 4.357 2.856 ;
     RECT  4.357 2.832 4.403 3.144 ;
     RECT  2.704 10.224 4.501 10.248 ;
     RECT  4.501 9.696 4.557 10.248 ;
     RECT  3.845 0.192 4.637 1.752 ;
     RECT  4.021 4.128 4.709 4.968 ;
     RECT  4.637 0.576 4.889 1.752 ;
     RECT  3.529 6.384 4.993 6.648 ;
     RECT  4.012 12.912 5.173 12.936 ;
     RECT  4.889 1.152 5.461 1.752 ;
     RECT  4.403 3.12 5.461 3.144 ;
     RECT  5.461 1.152 5.753 3.144 ;
     RECT  4.277 8.496 5.785 8.52 ;
     RECT  5.173 12.336 5.785 12.936 ;
     RECT  4.557 9.696 5.897 9.72 ;
     RECT  5.785 12.288 5.987 12.936 ;
     RECT  5.753 3.12 6.092 3.144 ;
     RECT  4.709 4.128 6.092 4.152 ;
     RECT  4.993 6.24 6.133 6.648 ;
     RECT  6.065 10.8 6.149 10.824 ;
     RECT  6.092 3.12 6.179 4.152 ;
     RECT  6.179 4.128 6.217 4.152 ;
     RECT  5.753 1.152 6.221 1.8 ;
     RECT  5.785 7.92 6.565 8.52 ;
     RECT  6.565 7.824 6.653 8.712 ;
     RECT  6.221 1.152 6.709 1.752 ;
     RECT  6.709 0.528 6.869 1.752 ;
     RECT  6.869 0.528 7.237 1.176 ;
     RECT  5.987 12.528 7.369 12.936 ;
     RECT  7.237 0.192 7.481 1.176 ;
     RECT  7.369 11.952 7.621 12.936 ;
     RECT  7.117 10.224 7.693 10.248 ;
     RECT  7.621 11.952 7.693 13.08 ;
     RECT  7.693 10.224 7.763 13.08 ;
     RECT  6.179 3.12 7.808 3.144 ;
     RECT  6.217 4.128 7.808 4.584 ;
     RECT  6.133 6 7.808 6.648 ;
     RECT  6.653 7.824 7.808 8.52 ;
     RECT  7.763 10.224 7.808 12.972 ;
     RECT  7.808 2.148 7.912 12.972 ;
     RECT  7.481 1.152 8.005 1.176 ;
     RECT  7.912 2.148 8.005 12.936 ;
     RECT  8.005 1.152 8.104 12.936 ;
     RECT  8.005 14.256 8.165 14.28 ;
     RECT  8.104 1.152 8.485 1.8 ;
     RECT  8.104 9.072 9.029 11.016 ;
     RECT  8.485 0.192 9.137 1.8 ;
     RECT  8.104 7.968 9.212 7.992 ;
     RECT  9.137 0.192 9.461 1.752 ;
     RECT  8.104 3.168 9.677 4.968 ;
     RECT  9.677 3.168 9.829 4.152 ;
     RECT  9.829 3.024 9.875 4.152 ;
     RECT  9.029 9.936 10.001 10.824 ;
     RECT  8.104 6 10.033 6.648 ;
     RECT  9.461 1.728 10.073 1.752 ;
     RECT  9.212 7.968 10.22 8.376 ;
     RECT  10.22 7.968 10.307 8.712 ;
     RECT  10.307 8.208 10.829 8.328 ;
     RECT  8.104 12 10.865 12.936 ;
     RECT  10.001 10.272 11.041 10.824 ;
     RECT  10.829 8.208 11.365 8.232 ;
     RECT  11.365 7.92 11.405 8.232 ;
     RECT  9.875 4.128 11.545 4.152 ;
     RECT  11.557 14.88 11.581 14.904 ;
     RECT  11.545 4.128 11.585 4.536 ;
     RECT  11.581 14.88 11.665 15 ;
     RECT  11.557 1.728 11.797 1.752 ;
     RECT  11.585 4.512 11.797 4.536 ;
     RECT  10.033 6 11.797 6.84 ;
     RECT  11.797 1.728 11.945 1.8 ;
     RECT  11.041 10.176 12.181 10.824 ;
     RECT  10.865 12.528 12.469 12.936 ;
     RECT  12.181 10.176 12.517 10.872 ;
     RECT  11.945 1.728 12.557 1.752 ;
     RECT  12.524 14.256 12.611 14.28 ;
     RECT  9.461 0.192 12.805 0.6 ;
     RECT  12.805 0.192 13.025 1.176 ;
     RECT  9.875 3.024 13.208 3.048 ;
     RECT  11.797 4.512 13.208 6.84 ;
     RECT  11.405 7.92 13.208 7.944 ;
     RECT  12.517 9.792 13.208 10.872 ;
     RECT  12.469 12.048 13.208 12.936 ;
     RECT  13.208 2.148 13.333 12.972 ;
     RECT  13.333 2.148 13.42 13.128 ;
     RECT  13.42 2.148 13.504 12.936 ;
     RECT  13.504 2.148 13.573 3.048 ;
     RECT  13.504 12.528 13.619 12.936 ;
     RECT  13.025 0.192 13.925 0.6 ;
     RECT  13.504 4.128 14.003 6.84 ;
     RECT  13.504 7.92 14.051 10.872 ;
     RECT  13.573 1.728 14.141 3.048 ;
     RECT  14.051 10.8 14.147 10.872 ;
     RECT  14.051 7.92 14.435 9.816 ;
     RECT  13.619 12.528 14.581 12.648 ;
     RECT  14.003 6 14.821 6.84 ;
     RECT  14.435 7.92 14.821 8.328 ;
     RECT  14.141 1.728 14.861 2.184 ;
     RECT  14.147 10.8 15.145 10.824 ;
     RECT  14.003 4.128 15.217 4.728 ;
     RECT  14.821 6 15.217 8.328 ;
     RECT  14.435 9.792 15.317 9.816 ;
     RECT  15.145 10.8 15.317 10.872 ;
     RECT  14.581 12.528 15.349 12.936 ;
     RECT  15.217 4.128 15.395 8.328 ;
     RECT  15.395 6 15.397 8.328 ;
     RECT  15.349 12.048 15.877 12.936 ;
     RECT  15.877 11.952 15.964 12.936 ;
     RECT  15.317 9.792 15.971 10.872 ;
     RECT  15.971 9.792 15.977 10.776 ;
     RECT  15.397 6 16.085 8.664 ;
     RECT  13.925 0.192 16.109 0.216 ;
     RECT  14.861 1.728 16.109 1.752 ;
     RECT  14.281 14.256 16.163 14.28 ;
     RECT  16.109 0.192 16.229 1.752 ;
     RECT  15.395 4.272 16.508 4.728 ;
     RECT  16.085 6 16.508 7.368 ;
     RECT  15.964 12.336 16.733 12.936 ;
     RECT  16.229 1.152 16.885 1.752 ;
     RECT  16.733 12.528 17.021 12.936 ;
     RECT  16.885 1.152 17.129 2.184 ;
     RECT  17.129 1.152 17.345 1.752 ;
     RECT  16.508 4.272 17.345 7.368 ;
     RECT  15.977 10.272 17.593 10.776 ;
     RECT  17.593 10.272 17.597 10.92 ;
     RECT  17.521 14.256 17.699 14.28 ;
     RECT  17.597 10.8 17.749 10.92 ;
     RECT  17.653 0.192 17.885 0.216 ;
     RECT  17.345 1.728 18.1 1.752 ;
     RECT  17.345 6 18.277 7.368 ;
     RECT  17.021 12.912 18.313 12.936 ;
     RECT  18.1 1.728 18.565 1.8 ;
     RECT  18.313 12.528 18.565 12.936 ;
     RECT  18.565 1.728 18.608 2.04 ;
     RECT  17.345 4.272 18.608 4.44 ;
     RECT  18.277 6 18.608 7.416 ;
     RECT  16.085 8.544 18.608 8.664 ;
     RECT  17.749 10.8 18.608 10.968 ;
     RECT  18.565 12.528 18.608 13.128 ;
     RECT  18.608 1.728 18.707 13.128 ;
     RECT  18.707 1.728 18.904 13.08 ;
     RECT  18.904 12.528 18.988 13.08 ;
     RECT  18.904 4.416 19.181 7.416 ;
     RECT  18.881 0.192 19.429 0.216 ;
     RECT  19.429 0.192 19.469 0.264 ;
     RECT  18.904 8.544 19.667 10.872 ;
     RECT  19.667 9.744 19.715 10.872 ;
     RECT  18.904 1.728 19.868 1.752 ;
     RECT  19.868 1.728 19.955 2.28 ;
     RECT  18.988 12.528 20.242 12.936 ;
     RECT  19.469 0.24 20.437 0.264 ;
     RECT  20.242 12.528 20.483 12.984 ;
     RECT  19.667 8.544 20.621 8.568 ;
     RECT  19.715 9.744 20.945 10.392 ;
     RECT  20.869 2.832 20.953 2.856 ;
     RECT  21.205 14.256 21.292 14.28 ;
     RECT  19.955 1.728 21.449 1.752 ;
     RECT  20.437 0.192 21.685 0.264 ;
     RECT  20.483 12.528 21.985 12.936 ;
     RECT  19.181 4.896 22.165 4.92 ;
     RECT  19.181 6 22.165 7.416 ;
     RECT  21.685 0.192 22.205 0.6 ;
     RECT  21.985 12.528 22.259 13.704 ;
     RECT  21.049 8.496 22.273 8.52 ;
     RECT  22.205 0.24 22.453 0.6 ;
     RECT  22.453 0.24 22.493 1.176 ;
     RECT  22.259 12.528 22.499 12.936 ;
     RECT  22.493 1.152 22.733 1.176 ;
     RECT  22.733 1.152 22.745 1.752 ;
     RECT  22.273 8.496 22.849 9.048 ;
     RECT  22.165 4.896 22.885 7.416 ;
     RECT  22.849 8.496 22.889 9.096 ;
     RECT  22.745 1.728 23.201 1.752 ;
     RECT  22.885 4.656 23.276 7.416 ;
     RECT  23.276 3.936 23.353 7.416 ;
     RECT  20.945 10.368 23.413 10.392 ;
     RECT  23.353 3.936 23.713 7.464 ;
     RECT  22.889 9.024 23.713 9.096 ;
     RECT  23.413 10.224 23.713 10.824 ;
     RECT  22.499 12.528 23.948 12.6 ;
     RECT  23.201 1.728 23.989 1.8 ;
     RECT  23.989 1.152 24.008 1.8 ;
     RECT  23.713 3.936 24.008 7.944 ;
     RECT  23.713 9.024 24.008 10.824 ;
     RECT  23.948 12.528 24.008 13.128 ;
     RECT  24.008 1.152 24.035 13.128 ;
     RECT  24.035 1.152 24.229 13.08 ;
     RECT  24.229 0.192 24.275 13.08 ;
     RECT  24.275 0.192 24.304 12.702 ;
     RECT  24.304 6.192 24.445 7.944 ;
     RECT  24.304 0.192 24.473 1.752 ;
     RECT  24.304 4.128 24.509 5.208 ;
     RECT  24.469 14.256 24.563 14.28 ;
     RECT  24.473 1.2 24.797 1.752 ;
     RECT  24.304 12.528 24.803 12.552 ;
     RECT  24.445 6.288 24.94 7.944 ;
     RECT  24.997 14.88 25.045 14.904 ;
     RECT  24.304 9.12 25.091 10.776 ;
     RECT  25.045 14.88 25.129 15 ;
     RECT  25.091 9.12 25.381 10.392 ;
     RECT  25.381 8.976 25.427 10.392 ;
     RECT  24.473 0.192 25.445 0.216 ;
     RECT  24.94 6.384 25.475 7.944 ;
     RECT  25.475 6.624 25.981 7.944 ;
     RECT  25.427 8.976 25.981 9 ;
     RECT  25.765 0.576 25.984 0.6 ;
     RECT  25.285 12.912 26.197 12.936 ;
     RECT  25.621 14.256 26.197 14.28 ;
     RECT  25.984 0.576 26.201 0.648 ;
     RECT  26.197 12.912 26.339 14.28 ;
     RECT  26.201 0.576 26.533 0.6 ;
     RECT  26.339 12.912 26.579 12.936 ;
     RECT  24.797 1.728 26.741 1.752 ;
     RECT  24.509 4.128 26.773 4.152 ;
     RECT  24.509 5.184 26.773 5.208 ;
     RECT  26.773 4.128 26.813 5.208 ;
     RECT  26.339 14.256 26.819 14.28 ;
     RECT  25.427 10.368 26.828 10.392 ;
     RECT  26.828 10.368 26.869 10.488 ;
     RECT  26.869 10.368 27.107 10.872 ;
     RECT  26.533 0.192 27.281 0.6 ;
     RECT  25.981 6.624 27.388 9 ;
     RECT  26.813 4.272 27.457 5.208 ;
     RECT  27.388 6.624 27.457 7.368 ;
     RECT  27.107 10.368 27.637 10.488 ;
     RECT  27.281 0.24 27.677 0.6 ;
     RECT  27.061 12.528 27.709 12.552 ;
     RECT  27.637 10.224 27.779 10.488 ;
     RECT  27.677 0.576 27.785 0.6 ;
     RECT  27.779 10.224 27.788 10.248 ;
     RECT  27.709 12.528 27.829 12.936 ;
     RECT  27.388 8.448 27.997 9 ;
     RECT  27.788 10.176 27.997 10.248 ;
     RECT  27.781 1.728 28.069 1.752 ;
     RECT  27.829 12 28.109 12.936 ;
     RECT  27.457 4.272 28.309 7.368 ;
     RECT  28.309 3.312 28.396 7.368 ;
     RECT  28.465 14.256 28.837 14.28 ;
     RECT  28.837 14.256 28.861 14.904 ;
     RECT  28.069 1.152 28.865 1.752 ;
     RECT  28.861 14.256 28.945 15 ;
     RECT  27.997 8.448 29.269 10.248 ;
     RECT  28.109 12.528 29.269 12.936 ;
     RECT  29.077 0.576 29.297 0.6 ;
     RECT  28.945 14.256 29.404 14.28 ;
     RECT  28.865 1.728 29.408 1.752 ;
     RECT  28.396 3.648 29.408 7.368 ;
     RECT  29.269 8.448 29.408 10.632 ;
     RECT  29.269 12.528 29.408 13.08 ;
     RECT  29.408 1.728 29.651 13.08 ;
     RECT  29.651 1.728 29.704 12.936 ;
     RECT  29.704 4.272 29.891 4.536 ;
     RECT  29.704 5.664 30.131 10.872 ;
     RECT  30.131 5.664 30.371 10.776 ;
     RECT  29.704 12.912 30.733 12.936 ;
     RECT  30.697 14.256 30.733 14.28 ;
     RECT  29.704 1.728 30.809 2.184 ;
     RECT  30.733 12.912 30.899 14.28 ;
     RECT  30.371 5.664 31.349 10.248 ;
     RECT  30.613 0.192 31.381 0.216 ;
     RECT  30.809 1.728 31.381 1.752 ;
     RECT  30.899 12.912 31.381 12.936 ;
     RECT  31.349 6.528 31.429 10.248 ;
     RECT  29.891 4.416 32.069 4.536 ;
     RECT  31.381 0.192 32.105 1.752 ;
     RECT  30.899 14.256 32.147 14.28 ;
     RECT  32.105 1.152 32.389 1.752 ;
     RECT  32.389 1.152 32.501 1.848 ;
     RECT  31.429 10.128 32.869 10.248 ;
     RECT  32.869 9.984 33.289 10.248 ;
     RECT  33.289 9.936 33.404 10.248 ;
     RECT  31.429 6.528 33.437 8.904 ;
     RECT  33.404 9.936 33.491 10.776 ;
     RECT  31.381 12 33.725 12.936 ;
     RECT  33.437 6.528 33.793 7.464 ;
     RECT  33.793 6 34.076 7.464 ;
     RECT  32.069 4.416 34.117 4.44 ;
     RECT  34.076 5.424 34.117 7.464 ;
     RECT  32.501 1.152 34.124 1.752 ;
     RECT  33.491 9.936 34.508 9.96 ;
     RECT  34.508 9.936 34.549 10.776 ;
     RECT  34.124 1.152 34.697 2.28 ;
     RECT  34.697 1.728 34.808 2.28 ;
     RECT  34.117 4.416 34.808 7.464 ;
     RECT  33.437 8.448 34.808 8.904 ;
     RECT  34.549 9.936 34.808 10.872 ;
     RECT  33.725 12.528 34.808 12.936 ;
     RECT  34.808 1.728 34.933 12.972 ;
     RECT  34.933 1.728 35.02 13.128 ;
     RECT  35.02 1.728 35.104 12.936 ;
     RECT  35.104 12.528 35.219 12.936 ;
     RECT  34.933 0.192 35.381 0.6 ;
     RECT  35.104 6.096 35.381 7.464 ;
     RECT  35.104 8.496 35.452 10.872 ;
     RECT  35.381 0.576 35.777 0.6 ;
     RECT  35.104 1.728 35.941 1.752 ;
     RECT  35.104 4.08 36.313 4.68 ;
     RECT  35.941 1.152 36.413 1.752 ;
     RECT  36.313 4.08 36.565 5.112 ;
     RECT  36.565 3.408 36.611 5.112 ;
     RECT  36.611 4.656 36.641 5.112 ;
     RECT  36.629 14.976 36.668 15 ;
     RECT  35.381 6.096 36.677 7.416 ;
     RECT  36.668 14.88 36.713 15 ;
     RECT  35.452 8.496 36.745 8.52 ;
     RECT  35.452 9.648 36.745 10.872 ;
     RECT  36.713 14.88 36.755 14.904 ;
     RECT  36.745 8.496 36.805 10.872 ;
     RECT  36.805 7.92 36.893 10.872 ;
     RECT  36.893 8.688 36.995 10.872 ;
     RECT  36.413 1.152 37.037 1.848 ;
     RECT  35.219 12.912 37.069 12.936 ;
     RECT  37.037 1.152 37.477 1.224 ;
     RECT  37.477 0.192 37.865 1.224 ;
     RECT  36.677 6.096 38.009 6.936 ;
     RECT  36.641 4.656 38.117 4.68 ;
     RECT  37.069 12.528 38.245 12.936 ;
     RECT  38.245 12.336 38.333 12.936 ;
     RECT  36.995 8.688 38.389 10.056 ;
     RECT  37.865 0.576 38.477 1.224 ;
     RECT  38.477 0.576 38.693 0.6 ;
     RECT  38.684 2.256 38.771 2.28 ;
     RECT  36.611 3.408 38.773 3.432 ;
     RECT  38.773 3.408 38.819 3.864 ;
     RECT  38.009 6.24 39.059 6.936 ;
     RECT  38.389 7.92 39.097 10.056 ;
     RECT  39.059 6.624 39.229 6.936 ;
     RECT  38.965 14.256 39.539 14.28 ;
     RECT  38.819 3.84 39.661 3.864 ;
     RECT  38.581 5.088 39.661 5.112 ;
     RECT  39.097 8.448 39.941 10.056 ;
     RECT  39.941 14.88 40.025 15 ;
     RECT  40.025 14.88 40.067 14.904 ;
     RECT  39.229 6.624 40.069 7.224 ;
     RECT  39.941 8.448 40.069 10.824 ;
     RECT  38.333 12.528 40.069 12.936 ;
     RECT  38.965 1.728 40.208 1.8 ;
     RECT  39.661 3.84 40.208 5.256 ;
     RECT  40.069 6.624 40.208 10.824 ;
     RECT  40.069 12.528 40.208 13.128 ;
     RECT  40.208 1.728 40.307 13.128 ;
     RECT  40.307 1.728 40.504 13.08 ;
     RECT  40.504 12.528 40.547 13.08 ;
     RECT  40.501 0.576 40.7 0.6 ;
     RECT  40.7 0.48 40.787 0.6 ;
     RECT  40.849 14.256 41.075 14.28 ;
     RECT  40.504 1.728 41.573 1.752 ;
     RECT  40.787 0.576 41.797 0.6 ;
     RECT  40.547 12.528 41.843 12.936 ;
     RECT  40.504 6.24 41.965 8.472 ;
     RECT  40.504 9.648 41.965 10.152 ;
     RECT  41.965 6.24 42.001 10.152 ;
     RECT  40.504 3.84 42.005 5.256 ;
     RECT  41.797 0.576 42.037 1.176 ;
     RECT  42.037 0.192 42.185 1.176 ;
     RECT  41.843 12.912 42.611 12.936 ;
     RECT  42.145 14.256 42.851 14.28 ;
     RECT  42.001 6.24 43.081 10.344 ;
     RECT  43.045 2.16 43.253 2.184 ;
     RECT  43.253 1.728 43.445 2.184 ;
     RECT  42.185 0.192 43.573 0.36 ;
     RECT  43.081 6.24 43.717 10.632 ;
     RECT  42.005 3.84 43.733 5.208 ;
     RECT  43.573 0.192 43.805 0.6 ;
     RECT  43.717 6.24 43.859 10.872 ;
     RECT  42.937 12.528 43.909 12.552 ;
     RECT  43.859 6.24 44.693 10.632 ;
     RECT  43.805 0.192 44.821 0.216 ;
     RECT  44.989 14.256 45.107 14.28 ;
     RECT  44.693 6.192 45.205 10.632 ;
     RECT  43.909 12.528 45.277 12.936 ;
     RECT  45.277 12.528 45.301 13.08 ;
     RECT  45.301 12 45.548 13.08 ;
     RECT  43.445 1.728 45.569 1.752 ;
     RECT  44.821 0.192 45.589 0.264 ;
     RECT  43.733 3.84 45.608 4.152 ;
     RECT  43.733 5.184 45.608 5.208 ;
     RECT  45.205 6.192 45.608 10.872 ;
     RECT  45.548 12 45.608 13.128 ;
     RECT  45.608 2.148 45.635 13.128 ;
     RECT  45.635 2.148 45.904 13.08 ;
     RECT  45.904 10.176 46.019 10.632 ;
     RECT  45.904 8.496 46.217 9 ;
     RECT  45.589 0.192 46.289 0.6 ;
     RECT  46.289 0.24 46.357 0.6 ;
     RECT  46.357 0.24 46.597 1.176 ;
     RECT  45.904 12.528 46.643 13.08 ;
     RECT  46.597 0.24 46.721 1.752 ;
     RECT  46.019 10.608 46.897 10.632 ;
     RECT  46.885 14.88 46.933 14.904 ;
     RECT  45.904 6.384 47.009 7.368 ;
     RECT  45.904 3.84 47.041 5.208 ;
     RECT  46.721 1.728 47.125 1.752 ;
     RECT  47.125 1.728 47.261 1.8 ;
     RECT  47.041 3.84 47.293 5.256 ;
     RECT  46.217 8.496 47.293 8.52 ;
     RECT  47.293 3.408 47.365 5.256 ;
     RECT  47.009 6.384 47.365 7.08 ;
     RECT  47.365 3.408 47.449 7.08 ;
     RECT  46.643 12.912 47.581 13.08 ;
     RECT  46.897 10.608 47.629 10.824 ;
     RECT  47.581 12.912 47.939 13.704 ;
     RECT  47.629 10.608 48.085 10.632 ;
     RECT  46.933 14.88 48.161 15 ;
     RECT  48.161 14.88 48.179 14.904 ;
     RECT  47.449 6.384 48.229 7.08 ;
     RECT  47.261 1.728 48.373 1.752 ;
     RECT  47.293 8.496 48.445 9.144 ;
     RECT  47.449 3.408 48.467 5.256 ;
     RECT  48.445 8.448 48.476 9.144 ;
     RECT  48.085 10.224 48.476 10.632 ;
     RECT  48.476 8.448 48.563 10.632 ;
     RECT  47.939 12.912 48.709 13.08 ;
     RECT  48.709 12.912 48.86 12.936 ;
     RECT  48.86 12.336 48.949 12.936 ;
     RECT  48.563 10.224 48.995 10.632 ;
     RECT  48.949 12 49.061 12.936 ;
     RECT  47.357 0.192 49.141 0.216 ;
     RECT  48.373 1.728 49.141 1.848 ;
     RECT  48.467 3.936 49.189 5.256 ;
     RECT  48.229 6.384 49.189 7.368 ;
     RECT  49.189 3.936 49.235 7.368 ;
     RECT  49.235 3.936 49.249 4.68 ;
     RECT  48.995 10.608 49.265 10.632 ;
     RECT  49.265 10.608 49.285 10.824 ;
     RECT  49.141 0.192 49.381 1.848 ;
     RECT  49.235 6 49.381 7.368 ;
     RECT  49.381 0.192 49.421 2.184 ;
     RECT  49.285 10.608 49.427 10.92 ;
     RECT  49.421 1.728 49.709 2.184 ;
     RECT  48.563 8.448 49.853 9.144 ;
     RECT  49.853 8.544 49.921 9.144 ;
     RECT  49.921 8.544 49.961 9.624 ;
     RECT  49.061 12.912 50.065 12.936 ;
     RECT  49.709 1.728 50.141 1.8 ;
     RECT  50.065 12.912 50.195 13.704 ;
     RECT  49.961 9.6 50.348 9.624 ;
     RECT  49.427 10.608 50.348 10.632 ;
     RECT  50.195 12.912 50.389 13.08 ;
     RECT  49.421 0.192 50.437 0.216 ;
     RECT  50.348 9.6 50.444 10.632 ;
     RECT  50.389 12 50.444 13.08 ;
     RECT  49.381 6 50.605 7.416 ;
     RECT  50.437 0.192 50.917 0.264 ;
     RECT  50.141 1.776 51.008 1.8 ;
     RECT  49.249 4.128 51.008 4.68 ;
     RECT  50.605 5.808 51.008 7.416 ;
     RECT  49.961 8.544 51.008 8.568 ;
     RECT  50.444 9.6 51.008 13.08 ;
     RECT  51.008 1.776 51.173 13.08 ;
     RECT  50.917 0.192 51.185 0.6 ;
     RECT  51.173 1.728 51.257 13.08 ;
     RECT  51.257 2.418 51.292 13.08 ;
     RECT  51.292 2.418 51.304 12.936 ;
     RECT  51.185 0.192 52.693 0.264 ;
     RECT  51.304 8.544 52.7 8.568 ;
     RECT  51.304 9.648 52.7 10.344 ;
     RECT  51.304 12.528 52.739 12.936 ;
     RECT  52.7 8.544 52.787 10.344 ;
     RECT  51.304 4.128 52.873 4.68 ;
     RECT  51.304 5.808 52.873 7.416 ;
     RECT  52.693 0.192 52.949 0.6 ;
     RECT  52.873 4.128 53.077 7.416 ;
     RECT  53.077 3.36 53.125 7.416 ;
     RECT  53.125 2.832 53.164 7.416 ;
     RECT  53.164 4.272 53.201 7.416 ;
     RECT  52.787 9.648 53.269 10.344 ;
     RECT  53.269 9.648 53.507 10.92 ;
     RECT  52.949 0.192 53.525 0.264 ;
     RECT  51.757 14.256 53.747 14.28 ;
     RECT  53.201 4.272 53.993 7.08 ;
     RECT  53.525 0.192 54.029 0.216 ;
     RECT  52.739 12.912 54.169 12.936 ;
     RECT  52.453 1.728 54.349 1.752 ;
     RECT  53.164 2.832 54.349 2.856 ;
     RECT  54.349 1.728 54.389 2.856 ;
     RECT  53.993 5.136 54.461 7.08 ;
     RECT  53.507 9.648 54.515 10.872 ;
     RECT  52.787 8.544 54.524 8.664 ;
     RECT  54.515 9.648 54.641 10.344 ;
     RECT  54.461 5.184 54.745 7.08 ;
     RECT  54.524 8.16 54.745 8.664 ;
     RECT  54.745 5.184 54.961 8.664 ;
     RECT  54.641 9.648 54.961 10.296 ;
     RECT  54.389 1.728 54.997 2.568 ;
     RECT  54.997 1.152 55.109 2.568 ;
     RECT  54.961 5.184 55.187 10.296 ;
     RECT  55.187 5.184 55.717 9.288 ;
     RECT  55.109 1.728 55.829 2.568 ;
     RECT  55.187 10.272 55.969 10.296 ;
     RECT  54.169 12.528 56.365 12.936 ;
     RECT  55.829 2.148 56.408 2.568 ;
     RECT  55.717 5.088 56.408 9.288 ;
     RECT  55.969 10.272 56.408 10.728 ;
     RECT  56.365 12.528 56.408 13.704 ;
     RECT  55.237 0.192 56.533 0.216 ;
     RECT  56.408 2.148 56.579 13.704 ;
     RECT  56.579 2.148 56.704 13.08 ;
     RECT  56.533 0.192 56.765 1.176 ;
     RECT  56.704 6 56.819 10.872 ;
     RECT  56.704 12.528 56.819 13.08 ;
     RECT  56.704 2.148 57.013 2.568 ;
     RECT  56.765 0.192 57.053 0.264 ;
     RECT  56.972 14.256 57.059 14.28 ;
     RECT  57.013 1.728 57.233 2.568 ;
     RECT  57.233 1.728 57.593 2.184 ;
     RECT  56.819 12.528 57.827 12.936 ;
     RECT  57.593 1.728 57.881 1.752 ;
     RECT  56.819 6 57.913 9.096 ;
     RECT  56.819 10.224 57.913 10.872 ;
     RECT  57.913 6 58.105 10.872 ;
     RECT  57.053 0.192 58.309 0.216 ;
     RECT  58.105 6 58.385 10.248 ;
     RECT  56.704 4.128 58.705 4.968 ;
     RECT  58.385 6 58.705 6.84 ;
     RECT  57.827 12.912 58.885 12.936 ;
     RECT  58.385 7.824 58.997 10.248 ;
     RECT  58.997 9.024 59.033 10.248 ;
     RECT  58.309 0.192 59.057 1.176 ;
     RECT  58.885 12.528 59.123 12.936 ;
     RECT  59.057 0.192 59.573 1.752 ;
     RECT  59.209 14.256 59.644 14.28 ;
     RECT  58.705 4.128 59.797 6.84 ;
     RECT  58.997 7.824 59.797 7.848 ;
     RECT  59.033 10.224 59.797 10.248 ;
     RECT  59.797 4.128 59.843 7.848 ;
     RECT  59.123 12.912 60.109 12.936 ;
     RECT  60.325 2.832 60.419 2.856 ;
     RECT  59.797 10.224 60.428 10.584 ;
     RECT  60.428 10.176 60.469 10.584 ;
     RECT  59.573 0.192 60.509 0.216 ;
     RECT  59.843 4.128 60.509 7.224 ;
     RECT  60.469 10.176 60.611 10.872 ;
     RECT  59.033 9.024 60.973 9.096 ;
     RECT  60.611 10.176 60.973 10.824 ;
     RECT  59.573 1.728 61.093 1.752 ;
     RECT  61.253 14.976 61.292 15 ;
     RECT  61.292 14.88 61.337 15 ;
     RECT  61.337 14.88 61.379 14.904 ;
     RECT  60.109 12.528 61.729 12.936 ;
     RECT  61.093 1.152 61.808 1.752 ;
     RECT  60.509 4.128 61.808 4.152 ;
     RECT  60.509 5.232 61.808 7.224 ;
     RECT  60.973 9.024 61.808 10.824 ;
     RECT  61.729 12.528 61.808 13.704 ;
     RECT  61.808 1.152 61.861 13.704 ;
     RECT  61.861 0.192 61.985 13.704 ;
     RECT  61.985 1.728 62.104 13.704 ;
     RECT  62.104 12.528 62.387 13.704 ;
     RECT  62.387 12.528 62.675 12.936 ;
     RECT  61.985 0.192 62.921 0.6 ;
     RECT  62.104 5.232 63.068 7.368 ;
     RECT  62.104 9.024 63.068 10.248 ;
     RECT  63.068 5.232 63.155 10.248 ;
     RECT  62.104 4.128 63.493 4.152 ;
     RECT  63.155 5.232 63.493 7.368 ;
     RECT  63.155 8.496 63.493 10.248 ;
     RECT  63.493 4.128 63.533 7.368 ;
     RECT  63.493 8.496 63.541 10.872 ;
     RECT  63.541 8.496 63.613 11.16 ;
     RECT  62.921 0.576 63.877 0.6 ;
     RECT  62.104 1.728 63.877 1.752 ;
     RECT  63.613 10.848 63.893 11.16 ;
     RECT  63.877 0.576 64.217 1.752 ;
     RECT  63.893 10.848 64.297 10.92 ;
     RECT  63.533 4.416 64.309 7.368 ;
     RECT  64.217 0.576 64.385 0.6 ;
     RECT  64.309 4.416 64.433 7.464 ;
     RECT  63.781 14.256 64.451 14.28 ;
     RECT  64.297 10.848 64.825 10.872 ;
     RECT  64.385 0.192 64.829 0.6 ;
     RECT  64.433 4.416 64.835 6.84 ;
     RECT  64.817 14.88 64.901 15 ;
     RECT  64.825 10.8 64.909 10.872 ;
     RECT  64.901 14.88 64.931 14.904 ;
     RECT  63.613 8.496 64.933 9.288 ;
     RECT  62.675 12.528 65.077 12.552 ;
     RECT  65.077 12.528 65.219 12.936 ;
     RECT  64.933 7.92 65.549 9.288 ;
     RECT  65.549 7.92 65.873 9.144 ;
     RECT  64.909 10.848 66.121 10.872 ;
     RECT  64.829 0.192 66.181 0.216 ;
     RECT  64.217 1.728 66.181 1.752 ;
     RECT  66.049 14.256 66.227 14.28 ;
     RECT  64.835 4.416 66.373 4.44 ;
     RECT  64.835 5.472 66.373 6.84 ;
     RECT  66.181 0.192 66.485 1.752 ;
     RECT  65.219 12.528 66.553 12.552 ;
     RECT  66.373 4.416 66.764 6.84 ;
     RECT  66.121 10.848 66.764 11.16 ;
     RECT  65.873 7.92 66.949 9.048 ;
     RECT  66.553 12.528 67.093 12.936 ;
     RECT  66.485 1.728 67.208 1.752 ;
     RECT  66.764 3.936 67.208 6.84 ;
     RECT  66.949 7.92 67.208 9.096 ;
     RECT  66.764 10.176 67.208 11.16 ;
     RECT  67.093 12.336 67.208 13.128 ;
     RECT  67.208 1.728 67.235 13.128 ;
     RECT  67.235 1.728 67.475 13.08 ;
     RECT  67.475 1.728 67.504 12.702 ;
     RECT  66.485 0.192 67.565 0.6 ;
     RECT  67.504 4.416 68.033 12.552 ;
     RECT  68.033 9.024 68.069 12.552 ;
     RECT  68.069 9.936 68.099 12.552 ;
     RECT  68.099 9.936 68.14 10.248 ;
     RECT  68.14 10.224 68.365 10.248 ;
     RECT  68.033 4.416 68.435 7.992 ;
     RECT  68.099 12 68.485 12.552 ;
     RECT  68.435 4.416 68.537 5.352 ;
     RECT  68.485 12 68.572 12.936 ;
     RECT  68.537 4.416 68.645 5.16 ;
     RECT  68.572 12 68.717 12.552 ;
     RECT  67.565 0.576 68.725 0.6 ;
     RECT  68.717 12.528 68.771 12.552 ;
     RECT  68.435 6.528 68.897 7.992 ;
     RECT  68.821 14.304 68.965 14.328 ;
     RECT  68.965 14.256 69.052 14.328 ;
     RECT  68.725 0.192 69.205 0.6 ;
     RECT  67.504 1.728 69.205 1.752 ;
     RECT  69.052 14.304 69.251 14.328 ;
     RECT  69.205 0.192 69.445 1.752 ;
     RECT  69.445 0.192 69.473 2.664 ;
     RECT  69.493 10.752 69.505 10.776 ;
     RECT  69.473 1.728 69.532 2.664 ;
     RECT  69.505 9.792 69.58 10.776 ;
     RECT  69.677 14.88 69.761 15 ;
     RECT  69.761 14.88 69.779 14.904 ;
     RECT  69.98 8.688 70.021 8.712 ;
     RECT  70.021 8.208 70.067 8.712 ;
     RECT  69.685 10.8 70.309 10.824 ;
     RECT  69.613 12.912 70.369 12.936 ;
     RECT  69.532 1.728 70.445 1.752 ;
     RECT  69.473 0.192 70.501 0.216 ;
     RECT  70.369 12.528 70.547 12.936 ;
     RECT  69.58 9.792 70.585 9.816 ;
     RECT  70.585 9.648 70.625 9.816 ;
     RECT  70.501 0.192 70.741 0.6 ;
     RECT  68.645 5.136 70.765 5.16 ;
     RECT  70.765 5.136 70.877 5.208 ;
     RECT  70.547 12.912 71.017 12.936 ;
     RECT  71.017 12.912 71.027 13.704 ;
     RECT  70.741 0.192 71.269 0.648 ;
     RECT  71.027 13.68 71.315 13.704 ;
     RECT  68.897 6.528 71.317 7.08 ;
     RECT  70.067 8.208 71.317 8.232 ;
     RECT  71.305 10.8 71.317 10.824 ;
     RECT  71.269 0.192 71.453 1.176 ;
     RECT  71.509 1.728 71.741 1.752 ;
     RECT  70.625 9.648 71.953 9.672 ;
     RECT  71.317 10.8 71.953 10.92 ;
     RECT  71.317 6.528 72.133 8.232 ;
     RECT  71.953 9.648 72.133 10.92 ;
     RECT  70.877 5.184 72.469 5.208 ;
     RECT  72.133 6.528 72.469 10.92 ;
     RECT  71.453 0.192 72.533 0.6 ;
     RECT  71.749 2.148 72.608 2.184 ;
     RECT  69.145 4.128 72.608 4.152 ;
     RECT  72.469 5.184 72.608 10.92 ;
     RECT  71.953 12.528 72.608 12.552 ;
     RECT  72.608 2.148 72.805 12.972 ;
     RECT  72.805 1.728 72.892 13.08 ;
     RECT  72.892 1.728 72.904 12.936 ;
     RECT  72.904 8.736 73.081 10.632 ;
     RECT  72.904 12 73.181 12.936 ;
     RECT  73.081 8.736 73.217 9.096 ;
     RECT  72.205 14.256 73.571 14.28 ;
     RECT  72.533 0.576 73.721 0.6 ;
     RECT  72.904 4.128 73.964 4.152 ;
     RECT  73.964 3.936 74.005 4.152 ;
     RECT  72.904 5.184 74.005 6.936 ;
     RECT  73.081 10.608 74.005 10.632 ;
     RECT  74.005 3.936 74.045 6.936 ;
     RECT  74.045 3.936 74.051 5.208 ;
     RECT  74.005 10.608 74.113 10.824 ;
     RECT  73.217 8.736 74.257 8.76 ;
     RECT  74.257 8.208 74.297 8.76 ;
     RECT  74.213 14.88 74.297 15 ;
     RECT  74.113 9.792 74.332 10.824 ;
     RECT  74.297 14.88 74.339 14.904 ;
     RECT  72.904 1.728 74.573 1.752 ;
     RECT  74.573 1.728 74.657 1.8 ;
     RECT  74.297 8.208 74.657 8.232 ;
     RECT  74.332 10.8 74.736 10.824 ;
     RECT  74.045 6.288 75.049 6.936 ;
     RECT  74.821 0.576 75.061 0.6 ;
     RECT  75.049 6.288 75.692 7.416 ;
     RECT  75.692 6.24 75.779 7.416 ;
     RECT  73.181 12.912 75.829 12.936 ;
     RECT  74.332 9.792 76.076 9.816 ;
     RECT  75.829 12.528 76.117 12.936 ;
     RECT  75.061 0.192 76.357 0.6 ;
     RECT  74.657 1.728 76.357 1.752 ;
     RECT  76.117 12 76.421 12.936 ;
     RECT  76.076 9.792 76.508 10.2 ;
     RECT  76.517 14.976 76.556 15 ;
     RECT  76.357 0.192 76.601 1.752 ;
     RECT  76.508 9.792 76.813 10.776 ;
     RECT  76.813 9.792 76.897 10.824 ;
     RECT  74.051 4.368 76.961 5.208 ;
     RECT  76.601 0.192 77.033 0.216 ;
     RECT  75.779 6.816 77.036 7.416 ;
     RECT  75.481 8.496 77.036 8.52 ;
     RECT  76.961 4.464 77.173 5.208 ;
     RECT  77.036 6.816 77.209 8.52 ;
     RECT  76.897 9.792 77.209 10.776 ;
     RECT  76.601 1.728 77.365 1.752 ;
     RECT  76.556 14.88 77.393 15 ;
     RECT  77.393 14.88 77.411 14.904 ;
     RECT  77.173 4.464 77.42 5.736 ;
     RECT  77.209 6.816 77.42 10.776 ;
     RECT  77.365 1.728 77.537 1.848 ;
     RECT  76.421 12.24 77.845 12.936 ;
     RECT  77.845 2.148 78.008 2.28 ;
     RECT  77.569 3.408 78.008 3.432 ;
     RECT  77.42 4.464 78.008 10.776 ;
     RECT  77.845 12 78.008 12.936 ;
     RECT  78.008 2.148 78.133 12.972 ;
     RECT  78.133 2.148 78.22 13.128 ;
     RECT  78.22 2.148 78.304 12.936 ;
     RECT  77.605 1.152 78.365 1.176 ;
     RECT  78.304 2.148 78.365 5.112 ;
     RECT  78.304 10.176 78.419 10.968 ;
     RECT  78.304 12 78.437 12.936 ;
     RECT  78.373 0.192 78.689 0.216 ;
     RECT  78.365 2.148 78.901 2.856 ;
     RECT  78.365 3.84 78.941 4.008 ;
     RECT  78.901 1.728 79.337 2.856 ;
     RECT  78.304 6.816 79.373 9 ;
     RECT  78.419 10.464 79.58 10.968 ;
     RECT  79.337 2.832 79.661 2.856 ;
     RECT  79.58 10.464 79.667 11.016 ;
     RECT  78.437 12.528 79.669 12.936 ;
     RECT  79.667 10.464 79.715 10.488 ;
     RECT  79.669 12 79.985 12.936 ;
     RECT  79.621 0.576 80.389 0.6 ;
     RECT  79.337 1.728 80.389 1.752 ;
     RECT  80.305 14.256 80.435 14.28 ;
     RECT  79.373 8.496 80.917 9 ;
     RECT  80.377 10.272 80.917 10.296 ;
     RECT  80.917 8.496 81.101 10.296 ;
     RECT  79.373 6.816 81.205 7.128 ;
     RECT  81.101 8.976 81.356 10.296 ;
     RECT  80.389 0.576 81.389 1.752 ;
     RECT  79.985 12.912 81.397 12.936 ;
     RECT  81.397 12.048 81.445 12.936 ;
     RECT  81.205 6.24 81.497 7.128 ;
     RECT  81.445 11.952 81.532 12.936 ;
     RECT  78.941 3.984 81.821 4.008 ;
     RECT  78.365 5.088 81.889 5.112 ;
     RECT  81.356 8.976 81.889 10.776 ;
     RECT  81.532 12 82.253 12.936 ;
     RECT  81.889 5.088 82.321 5.16 ;
     RECT  82.321 4.416 82.789 5.16 ;
     RECT  81.889 8.976 82.897 10.824 ;
     RECT  82.789 4.416 82.933 5.208 ;
     RECT  81.497 6.24 82.933 6.84 ;
     RECT  81.445 0.192 83.221 0.216 ;
     RECT  81.389 1.728 83.221 1.752 ;
     RECT  83.221 0.192 83.261 1.752 ;
     RECT  83.113 14.256 83.267 14.28 ;
     RECT  82.253 12.528 83.365 12.936 ;
     RECT  83.261 0.576 83.408 1.752 ;
     RECT  82.933 4.416 83.408 6.84 ;
     RECT  82.897 8.448 83.408 10.824 ;
     RECT  83.365 12.528 83.408 13.128 ;
     RECT  83.408 0.576 83.507 13.128 ;
     RECT  83.507 0.576 83.704 13.08 ;
     RECT  83.704 12.528 83.747 13.08 ;
     RECT  83.704 10.176 83.837 10.824 ;
     RECT  83.704 0.576 84.161 1.752 ;
     RECT  84.161 0.576 84.469 0.6 ;
     RECT  83.747 12.528 84.668 12.936 ;
     RECT  84.469 0.192 84.737 0.6 ;
     RECT  84.668 12.336 84.755 12.936 ;
     RECT  83.837 10.176 84.917 10.248 ;
     RECT  83.704 4.416 85.043 5.784 ;
     RECT  83.704 6.816 85.421 9 ;
     RECT  85.421 6.816 85.925 7.944 ;
     RECT  84.917 10.176 85.925 10.2 ;
     RECT  84.755 12.528 86.005 12.936 ;
     RECT  85.043 4.416 86.065 5.208 ;
     RECT  85.993 10.224 86.077 10.248 ;
     RECT  86.005 12 86.321 12.936 ;
     RECT  85.421 8.976 86.605 9 ;
     RECT  86.317 10.272 86.749 10.296 ;
     RECT  86.749 10.272 86.833 10.824 ;
     RECT  86.605 8.448 86.857 9 ;
     RECT  86.065 4.128 86.965 5.208 ;
     RECT  85.925 6.816 86.965 7.416 ;
     RECT  86.965 4.128 87.011 7.416 ;
     RECT  84.737 0.576 87.013 0.6 ;
     RECT  87.013 0.192 87.437 0.6 ;
     RECT  86.833 10.272 87.731 10.776 ;
     RECT  86.857 8.448 87.827 9.144 ;
     RECT  86.321 12.336 87.973 12.936 ;
     RECT  87.731 10.272 88.076 10.296 ;
     RECT  87.437 0.192 88.301 0.216 ;
     RECT  84.161 1.728 88.337 1.752 ;
     RECT  87.011 6.096 88.693 7.416 ;
     RECT  87.827 8.448 88.693 9 ;
     RECT  87.973 11.952 88.748 12.936 ;
     RECT  88.076 10.176 88.765 10.296 ;
     RECT  88.729 2.016 88.808 2.04 ;
     RECT  87.011 4.128 88.808 4.968 ;
     RECT  88.693 6.096 88.808 9 ;
     RECT  88.765 10.08 88.808 10.296 ;
     RECT  88.748 11.952 88.808 13.128 ;
     RECT  88.808 2.016 88.835 13.128 ;
     RECT  88.835 2.016 89.104 13.08 ;
     RECT  89.104 12 89.116 13.08 ;
     RECT  89.104 2.832 89.425 7.992 ;
     RECT  88.549 0.576 89.557 0.6 ;
     RECT  89.557 0.192 89.921 0.6 ;
     RECT  89.425 2.832 89.957 2.856 ;
     RECT  89.425 4.128 90.281 7.992 ;
     RECT  90.281 4.368 90.38 7.992 ;
     RECT  89.104 8.976 90.38 9.096 ;
     RECT  90.38 4.368 90.467 9.096 ;
     RECT  89.104 10.08 90.529 10.776 ;
     RECT  89.317 1.728 90.532 1.752 ;
     RECT  90.529 10.08 90.613 10.824 ;
     RECT  90.532 1.728 90.641 1.8 ;
     RECT  90.613 10.08 90.937 10.248 ;
     RECT  90.467 4.368 91.037 7.992 ;
     RECT  90.467 8.976 91.217 9.096 ;
     RECT  89.921 0.576 91.613 0.6 ;
     RECT  90.641 1.728 91.649 1.752 ;
     RECT  89.116 12 92.06 12.936 ;
     RECT  92.06 11.952 92.147 12.936 ;
     RECT  91.037 7.968 92.221 7.992 ;
     RECT  91.217 8.976 92.221 9 ;
     RECT  90.937 10.08 92.257 10.104 ;
     RECT  92.221 7.968 92.261 9 ;
     RECT  92.257 10.08 92.341 10.824 ;
     RECT  91.861 0.192 92.581 0.552 ;
     RECT  92.147 12 92.585 12.936 ;
     RECT  92.261 8.112 92.725 9 ;
     RECT  92.341 10.08 92.725 10.104 ;
     RECT  92.725 8.112 92.765 10.104 ;
     RECT  92.581 0.192 92.801 1.176 ;
     RECT  93.26 3.36 93.301 3.384 ;
     RECT  91.037 4.368 93.301 6.84 ;
     RECT  92.765 8.112 93.301 9.72 ;
     RECT  92.801 0.192 93.485 0.6 ;
     RECT  92.585 12.912 93.589 12.936 ;
     RECT  93.301 3.36 94.021 6.84 ;
     RECT  93.301 7.968 94.021 9.72 ;
     RECT  93.553 10.8 94.069 10.824 ;
     RECT  93.589 12 94.117 12.936 ;
     RECT  92.869 1.728 94.208 1.752 ;
     RECT  94.021 3.36 94.208 9.72 ;
     RECT  94.069 10.8 94.208 11.016 ;
     RECT  94.117 12 94.208 13.08 ;
     RECT  94.208 1.728 94.451 13.08 ;
     RECT  94.451 1.728 94.504 12.936 ;
     RECT  94.504 4.128 94.643 9.336 ;
     RECT  94.504 10.752 94.825 10.824 ;
     RECT  93.485 0.192 95.104 0.216 ;
     RECT  94.504 1.728 95.141 2.184 ;
     RECT  94.643 7.92 95.177 9.336 ;
     RECT  94.825 10.752 95.363 10.776 ;
     RECT  95.104 0.192 95.893 0.264 ;
     RECT  95.141 2.16 95.933 2.184 ;
     RECT  94.504 12 96.14 12.936 ;
     RECT  95.893 0.192 96.185 1.176 ;
     RECT  96.14 11.952 96.227 12.936 ;
     RECT  94.643 4.128 96.277 6.84 ;
     RECT  95.177 7.92 96.277 9 ;
     RECT  96.277 4.128 96.565 9 ;
     RECT  95.713 10.272 96.565 10.296 ;
     RECT  96.565 4.128 96.685 10.296 ;
     RECT  96.685 4.128 96.901 10.824 ;
     RECT  96.661 1.728 96.905 1.752 ;
     RECT  96.86 14.256 96.947 14.28 ;
     RECT  96.901 4.128 97.157 10.872 ;
     RECT  96.227 12 97.265 12.936 ;
     RECT  96.185 0.192 97.669 0.264 ;
     RECT  97.157 4.128 97.805 10.248 ;
     RECT  97.669 0.192 98.417 0.6 ;
     RECT  97.265 12.528 98.483 12.936 ;
     RECT  97.805 10.224 98.701 10.248 ;
     RECT  98.557 13.68 98.771 13.704 ;
     RECT  97.805 4.128 98.809 8.712 ;
     RECT  99.097 14.256 99.251 14.28 ;
     RECT  98.701 10.224 99.397 10.632 ;
     RECT  98.483 12.528 99.397 12.552 ;
     RECT  98.417 0.192 99.497 0.312 ;
     RECT  98.809 4.128 99.608 9 ;
     RECT  99.397 10.176 99.608 10.632 ;
     RECT  99.397 12.24 99.608 12.552 ;
     RECT  99.608 2.148 99.733 12.972 ;
     RECT  99.733 1.728 99.82 13.128 ;
     RECT  99.82 1.728 99.904 12.936 ;
     RECT  99.497 0.24 99.965 0.312 ;
     RECT  99.904 8.976 100.117 10.824 ;
     RECT  99.904 1.728 100.181 1.8 ;
     RECT  100.181 1.728 100.325 1.752 ;
     RECT  99.904 7.92 100.361 7.944 ;
     RECT  99.965 0.24 100.501 0.264 ;
     RECT  100.117 8.976 100.541 10.776 ;
     RECT  99.904 5.184 100.595 6.792 ;
     RECT  100.595 5.28 100.636 6.792 ;
     RECT  99.904 12 101.267 12.936 ;
     RECT  101.437 14.256 101.555 14.28 ;
     RECT  99.904 4.176 101.605 4.2 ;
     RECT  100.636 5.28 101.605 5.736 ;
     RECT  100.636 6.768 101.605 6.792 ;
     RECT  100.541 9.648 101.621 10.776 ;
     RECT  101.621 10.272 101.761 10.776 ;
     RECT  101.717 1.728 101.801 1.752 ;
     RECT  101.267 12 101.869 12.552 ;
     RECT  101.761 10.272 101.987 10.824 ;
     RECT  101.869 11.952 102.035 12.552 ;
     RECT  102.035 12.048 102.053 12.552 ;
     RECT  100.933 8.496 102.125 8.52 ;
     RECT  101.605 4.176 102.233 6.792 ;
     RECT  102.053 12.528 102.277 12.552 ;
     RECT  102.233 5.472 102.449 6.792 ;
     RECT  102.589 14.256 102.803 14.28 ;
     RECT  102.233 4.176 102.917 4.2 ;
     RECT  101.987 10.272 103.057 10.296 ;
     RECT  102.949 8.304 103.129 8.328 ;
     RECT  103.057 10.272 103.141 10.824 ;
     RECT  103.141 10.272 103.388 10.296 ;
     RECT  102.277 12.528 103.429 12.936 ;
     RECT  102.449 5.712 103.525 6.792 ;
     RECT  103.129 7.872 103.525 8.328 ;
     RECT  103.525 5.712 103.571 8.328 ;
     RECT  103.429 12 103.633 12.936 ;
     RECT  103.388 10.176 103.637 10.296 ;
     RECT  103.637 10.176 103.669 10.248 ;
     RECT  100.501 0.192 103.765 0.264 ;
     RECT  103.633 12 103.811 13.704 ;
     RECT  103.765 0.192 104.141 0.6 ;
     RECT  103.571 8.112 104.245 8.328 ;
     RECT  104.293 14.256 104.38 14.28 ;
     RECT  104.245 8.112 104.773 8.52 ;
     RECT  103.669 9.744 104.773 10.248 ;
     RECT  104.773 8.112 104.785 10.248 ;
     RECT  103.705 3.888 105.001 3.912 ;
     RECT  103.285 1.728 105.008 1.752 ;
     RECT  105.001 3.888 105.008 4.44 ;
     RECT  103.571 5.712 105.008 7.08 ;
     RECT  104.785 8.112 105.008 10.824 ;
     RECT  103.811 12 105.008 12.936 ;
     RECT  105.008 1.728 105.061 12.972 ;
     RECT  104.141 0.192 105.185 0.264 ;
     RECT  105.061 1.728 105.185 13.128 ;
     RECT  105.185 1.728 105.304 13.08 ;
     RECT  105.304 12.336 105.388 13.08 ;
     RECT  105.304 5.712 105.875 10.872 ;
     RECT  105.875 5.712 106.121 9.96 ;
     RECT  106.121 6.768 106.265 9.96 ;
     RECT  105.388 12.336 106.405 12.936 ;
     RECT  106.405 11.376 106.595 12.936 ;
     RECT  105.185 0.192 107.056 0.216 ;
     RECT  106.595 12 107.201 12.936 ;
     RECT  105.304 3.888 107.219 4.44 ;
     RECT  106.121 5.712 107.341 5.736 ;
     RECT  106.265 6.768 107.453 9.816 ;
     RECT  106.945 10.8 107.785 10.824 ;
     RECT  107.341 5.664 107.813 5.736 ;
     RECT  105.304 1.728 108.137 1.752 ;
     RECT  107.219 3.888 108.565 4.008 ;
     RECT  107.201 12.528 108.673 12.936 ;
     RECT  107.056 0.192 108.853 0.264 ;
     RECT  107.813 5.712 108.853 5.736 ;
     RECT  107.453 6.768 108.853 6.84 ;
     RECT  108.853 0.192 108.893 0.6 ;
     RECT  108.673 12.528 108.899 13.704 ;
     RECT  107.453 8.4 109.004 9.816 ;
     RECT  109.004 2.832 109.045 2.856 ;
     RECT  108.565 3.888 109.045 4.44 ;
     RECT  109.045 2.832 109.091 4.44 ;
     RECT  108.893 0.576 109.145 0.6 ;
     RECT  109.004 8.4 109.237 10.488 ;
     RECT  108.899 12.528 109.325 12.936 ;
     RECT  109.141 1.728 109.381 1.752 ;
     RECT  109.237 8.4 109.427 10.872 ;
     RECT  108.853 5.712 109.789 6.84 ;
     RECT  109.427 8.4 109.789 10.392 ;
     RECT  109.325 12.912 109.969 12.936 ;
     RECT  109.861 0.192 110.116 0.216 ;
     RECT  109.381 1.728 110.408 2.184 ;
     RECT  109.091 3.408 110.408 3.432 ;
     RECT  109.091 4.416 110.408 4.44 ;
     RECT  109.789 5.712 110.408 10.392 ;
     RECT  109.969 12.912 110.408 13.704 ;
     RECT  110.408 1.728 110.585 13.704 ;
     RECT  110.116 0.192 110.629 0.264 ;
     RECT  110.585 2.418 110.675 13.704 ;
     RECT  110.675 2.418 110.704 12.936 ;
     RECT  110.704 4.416 110.867 7.464 ;
     RECT  110.629 0.192 110.981 0.6 ;
     RECT  110.867 4.416 111.155 6.456 ;
     RECT  111.155 4.416 111.305 4.584 ;
     RECT  110.981 0.192 111.413 0.264 ;
     RECT  110.704 3.408 111.521 3.432 ;
     RECT  110.704 8.448 111.733 10.824 ;
     RECT  111.685 2.16 111.845 2.184 ;
     RECT  111.733 8.448 111.971 10.872 ;
     RECT  110.704 12.336 112.069 12.936 ;
     RECT  111.925 1.728 112.169 1.752 ;
     RECT  112.069 12 112.385 12.936 ;
     RECT  111.413 0.192 112.405 0.216 ;
     RECT  112.385 12.528 112.451 12.936 ;
     RECT  110.867 7.44 112.453 7.464 ;
     RECT  111.971 8.448 112.453 10.392 ;
     RECT  112.453 7.44 112.601 10.392 ;
     RECT  111.305 4.56 112.669 4.584 ;
     RECT  111.155 5.712 112.669 6.456 ;
     RECT  112.669 4.56 112.709 6.456 ;
     RECT  112.451 12.912 112.813 12.936 ;
     RECT  112.813 12.912 112.979 13.704 ;
     RECT  112.601 9.552 113.101 10.392 ;
     RECT  113.093 14.976 113.132 15 ;
     RECT  113.132 14.88 113.177 15 ;
     RECT  112.709 4.944 113.209 6.456 ;
     RECT  112.601 7.44 113.209 8.472 ;
     RECT  113.177 14.88 113.219 14.904 ;
     RECT  112.405 0.192 113.461 0.264 ;
     RECT  113.173 2.16 113.465 2.184 ;
     RECT  113.209 4.944 113.573 8.472 ;
     RECT  113.573 8.448 113.825 8.472 ;
     RECT  112.979 12.912 113.893 12.936 ;
     RECT  113.893 12.336 113.941 12.936 ;
     RECT  113.701 1.728 113.969 1.848 ;
     RECT  113.969 1.824 114.005 1.848 ;
     RECT  113.101 9.552 114.065 10.824 ;
     RECT  114.065 9.552 114.149 10.872 ;
     RECT  113.941 12 114.541 12.936 ;
     RECT  114.149 9.552 114.563 10.824 ;
     RECT  113.573 4.944 114.661 7.368 ;
     RECT  114.661 4.944 114.748 7.848 ;
     RECT  114.541 12 114.755 13.704 ;
     RECT  113.461 0.192 114.941 0.6 ;
     RECT  114.755 12 115.717 12.936 ;
     RECT  114.748 4.944 115.808 7.368 ;
     RECT  115.261 8.448 115.808 8.472 ;
     RECT  114.563 9.552 115.808 10.728 ;
     RECT  115.717 12 115.808 13.08 ;
     RECT  115.808 2.148 116.005 13.08 ;
     RECT  116.005 1.728 116.104 13.08 ;
     RECT  116.104 6.816 116.243 10.728 ;
     RECT  116.104 12 116.243 13.08 ;
     RECT  116.243 6.816 116.273 10.392 ;
     RECT  114.941 0.192 116.485 0.264 ;
     RECT  116.273 6.816 116.579 8.376 ;
     RECT  116.485 0.192 116.669 0.6 ;
     RECT  116.579 7.056 117.011 8.376 ;
     RECT  116.104 4.944 117.245 5.736 ;
     RECT  117.011 7.056 117.461 7.368 ;
     RECT  117.421 14.256 117.539 14.28 ;
     RECT  116.273 9.36 117.644 10.392 ;
     RECT  116.243 12 117.644 12.936 ;
     RECT  117.644 9.36 117.731 12.936 ;
     RECT  116.104 1.728 117.781 1.752 ;
     RECT  117.781 1.728 118.001 1.848 ;
     RECT  117.731 9.36 118.163 10.776 ;
     RECT  117.731 12 118.397 12.936 ;
     RECT  118.001 1.728 118.433 1.752 ;
     RECT  116.669 0.192 118.501 0.216 ;
     RECT  117.461 7.056 118.501 7.08 ;
     RECT  117.601 3.696 118.681 3.72 ;
     RECT  118.681 3.408 118.721 3.72 ;
     RECT  117.245 5.712 118.789 5.736 ;
     RECT  118.501 6.768 118.789 7.08 ;
     RECT  118.501 0.192 118.865 0.264 ;
     RECT  118.789 5.712 119.221 7.08 ;
     RECT  119.029 2.16 119.261 2.184 ;
     RECT  118.397 12.528 119.315 12.936 ;
     RECT  118.163 9.36 119.405 10.584 ;
     RECT  119.405 9.6 119.557 10.584 ;
     RECT  118.721 3.408 119.788 3.432 ;
     RECT  119.221 5.088 119.797 7.08 ;
     RECT  117.011 8.352 119.797 8.376 ;
     RECT  119.756 14.256 119.843 14.28 ;
     RECT  119.797 5.088 119.884 8.376 ;
     RECT  119.884 5.088 119.909 7.08 ;
     RECT  119.909 5.088 120.013 6.024 ;
     RECT  119.315 12.912 120.121 12.936 ;
     RECT  120.044 3.312 120.131 3.336 ;
     RECT  119.909 7.056 120.197 7.08 ;
     RECT  119.537 1.728 120.233 1.752 ;
     RECT  118.865 0.192 120.325 0.216 ;
     RECT  120.121 12.912 120.371 13.704 ;
     RECT  119.557 9.6 120.421 11.016 ;
     RECT  120.013 4.944 121.165 6.024 ;
     RECT  120.949 7.2 121.165 7.224 ;
     RECT  120.565 2.16 121.208 2.184 ;
     RECT  121.165 4.944 121.208 7.224 ;
     RECT  119.884 8.352 121.208 8.376 ;
     RECT  120.421 9.504 121.208 11.016 ;
     RECT  120.371 12.912 121.208 13.08 ;
     RECT  121.208 2.148 121.312 13.08 ;
     RECT  121.312 2.418 121.333 13.08 ;
     RECT  121.333 2.418 121.504 13.128 ;
     RECT  120.325 0.192 121.573 0.312 ;
     RECT  121.504 12.528 121.619 13.128 ;
     RECT  121.504 4.944 121.673 7.464 ;
     RECT  121.673 6 122.329 7.464 ;
     RECT  121.619 12.528 122.387 12.552 ;
     RECT  121.573 0.192 122.429 0.6 ;
     RECT  121.504 8.448 122.429 8.52 ;
     RECT  121.885 13.68 122.581 13.704 ;
     RECT  122.581 12.912 122.867 13.704 ;
     RECT  121.673 4.944 123.109 4.968 ;
     RECT  122.329 6 123.109 7.224 ;
     RECT  121.504 9.504 123.145 10.344 ;
     RECT  122.867 12.912 123.436 12.936 ;
     RECT  122.429 0.192 123.829 0.264 ;
     RECT  123.109 4.944 124.013 7.224 ;
     RECT  124.013 7.2 124.225 7.224 ;
     RECT  122.429 8.448 124.261 8.472 ;
     RECT  123.145 9.504 124.261 10.632 ;
     RECT  124.225 7.2 124.265 7.464 ;
     RECT  124.261 8.448 124.265 10.632 ;
     RECT  124.549 11.28 124.691 11.304 ;
     RECT  124.265 8.448 124.877 10.248 ;
     RECT  123.829 0.192 124.931 0.552 ;
     RECT  123.068 14.256 124.931 14.28 ;
     RECT  123.505 12.528 125.125 12.552 ;
     RECT  124.013 4.944 125.173 6.024 ;
     RECT  125.173 3.696 125.219 6.024 ;
     RECT  125.219 3.696 125.26 4.536 ;
     RECT  125.26 3.696 125.453 3.72 ;
     RECT  122.309 1.728 125.705 1.752 ;
     RECT  124.931 0.192 126.092 0.264 ;
     RECT  126.092 0.192 126.179 0.552 ;
     RECT  124.265 7.44 126.385 7.464 ;
     RECT  124.877 8.448 126.385 9.816 ;
     RECT  125.629 10.8 126.449 10.824 ;
     RECT  125.219 5.616 126.565 6.024 ;
     RECT  126.385 7.44 126.565 9.816 ;
     RECT  126.449 10.8 126.565 11.4 ;
     RECT  126.493 3.936 126.608 3.96 ;
     RECT  126.565 5.616 126.608 11.4 ;
     RECT  125.125 12.528 126.608 12.936 ;
     RECT  126.608 2.148 126.661 12.972 ;
     RECT  126.661 2.148 126.881 13.128 ;
     RECT  126.881 1.728 126.904 13.128 ;
     RECT  126.904 3.936 127.043 6.84 ;
     RECT  127.043 4.128 127.253 6.84 ;
     RECT  127.253 4.128 127.289 6.024 ;
     RECT  126.904 7.872 127.397 10.776 ;
     RECT  126.904 12 127.501 13.128 ;
     RECT  126.179 0.192 127.669 0.216 ;
     RECT  127.501 12 127.715 13.704 ;
     RECT  127.715 12 127.829 12.936 ;
     RECT  127.669 0.192 127.901 0.6 ;
     RECT  127.397 10.704 128.149 10.776 ;
     RECT  128.149 10.704 128.236 11.016 ;
     RECT  127.901 0.192 128.297 0.264 ;
     RECT  128.257 6.864 128.369 6.888 ;
     RECT  127.397 7.872 128.477 9.576 ;
     RECT  127.289 4.128 128.945 5.736 ;
     RECT  126.904 1.728 129.269 1.752 ;
     RECT  128.236 10.704 129.877 10.728 ;
     RECT  128.477 7.92 129.949 9.576 ;
     RECT  129.877 10.704 129.949 10.824 ;
     RECT  128.297 0.192 129.973 0.216 ;
     RECT  129.949 7.92 129.989 10.824 ;
     RECT  129.973 0.192 130.385 0.6 ;
     RECT  130.385 0.192 130.421 0.264 ;
     RECT  128.945 4.128 130.556 4.152 ;
     RECT  128.945 5.472 130.556 5.496 ;
     RECT  130.556 4.128 130.643 5.496 ;
     RECT  130.957 6.816 130.981 6.84 ;
     RECT  129.989 7.92 130.981 10.344 ;
     RECT  130.981 6.816 131.027 10.344 ;
     RECT  131.027 8.832 131.077 10.344 ;
     RECT  130.643 4.128 131.132 4.152 ;
     RECT  130.643 5.472 131.137 5.496 ;
     RECT  131.027 6.816 131.137 7.464 ;
     RECT  131.077 8.832 131.281 10.872 ;
     RECT  131.221 14.256 131.308 14.28 ;
     RECT  131.221 1.728 131.453 1.752 ;
     RECT  131.281 8.832 131.749 11.304 ;
     RECT  127.829 12.528 131.749 12.936 ;
     RECT  131.749 8.832 131.948 12.936 ;
     RECT  131.453 1.728 132.008 1.8 ;
     RECT  131.132 3.168 132.008 4.152 ;
     RECT  131.137 5.472 132.008 7.464 ;
     RECT  131.948 8.832 132.008 13.128 ;
     RECT  132.008 1.728 132.035 13.128 ;
     RECT  130.421 0.192 132.229 0.216 ;
     RECT  132.035 1.728 132.304 13.08 ;
     RECT  132.304 12.528 132.419 13.08 ;
     RECT  132.229 0.192 132.437 0.6 ;
     RECT  132.437 0.192 133.049 0.216 ;
     RECT  132.304 9.648 133.292 10.344 ;
     RECT  132.304 4.128 133.297 4.152 ;
     RECT  132.304 5.472 133.337 7.368 ;
     RECT  132.419 12.528 133.373 12.936 ;
     RECT  133.292 9.648 133.379 11.304 ;
     RECT  133.297 4.128 133.58 4.392 ;
     RECT  133.58 3.84 133.667 4.392 ;
     RECT  132.304 1.728 133.757 1.752 ;
     RECT  133.337 6.768 133.805 7.368 ;
     RECT  133.757 1.728 133.841 1.8 ;
     RECT  133.873 13.68 134.051 13.704 ;
     RECT  134.005 0.576 134.165 0.6 ;
     RECT  133.373 12.528 134.389 12.6 ;
     RECT  134.389 12.528 134.472 12.648 ;
     RECT  133.337 5.472 134.525 5.496 ;
     RECT  133.379 9.648 134.597 10.872 ;
     RECT  134.597 9.648 134.669 10.248 ;
     RECT  133.841 1.728 134.741 1.752 ;
     RECT  133.805 6.768 134.741 6.792 ;
     RECT  134.472 12.528 134.917 12.936 ;
     RECT  133.621 2.832 134.993 2.856 ;
     RECT  134.669 10.224 135.001 10.248 ;
     RECT  134.293 0.192 135.269 0.216 ;
     RECT  134.917 12 135.389 12.936 ;
     RECT  135.269 0.192 135.497 0.264 ;
     RECT  135.452 11.28 135.539 11.304 ;
     RECT  135.389 12.336 135.587 12.936 ;
     RECT  135.497 0.24 135.713 0.264 ;
     RECT  135.587 12.528 135.827 12.936 ;
     RECT  135.781 1.728 135.893 1.752 ;
     RECT  135.925 2.88 136.115 2.904 ;
     RECT  135.827 12.528 136.115 12.552 ;
    LAYER M5 ;
     RECT  2.16 0.144 136.104 0.227 ;
     RECT  2.16 0.227 130.248 0.275 ;
     RECT  131.232 0.227 136.104 0.275 ;
     RECT  99.216 0.275 100.248 0.323 ;
     RECT  116.016 0.275 122.376 0.323 ;
     RECT  19.68 0.275 44.376 0.371 ;
     RECT  52.464 0.275 96.696 0.563 ;
     RECT  123.36 0.275 130.008 0.563 ;
     RECT  2.16 0.275 18.696 0.611 ;
     RECT  19.68 0.371 41.832 0.611 ;
     RECT  45.36 0.275 51.24 0.611 ;
     RECT  52.464 0.563 91.608 0.611 ;
     RECT  97.68 0.275 98.232 0.611 ;
     RECT  103.296 0.275 104.328 0.611 ;
     RECT  108.864 0.275 110.664 0.611 ;
     RECT  113.184 0.275 114.744 0.611 ;
     RECT  116.016 0.323 120.6 0.611 ;
     RECT  121.584 0.323 122.376 0.611 ;
     RECT  126.912 0.563 130.008 0.611 ;
     RECT  63.12 0.611 71.784 0.659 ;
     RECT  2.16 0.611 10.056 1.187 ;
     RECT  22.464 0.611 26.328 1.187 ;
     RECT  27.792 0.611 40.296 1.187 ;
     RECT  41.28 0.611 41.832 1.187 ;
     RECT  53.472 0.611 62.136 1.187 ;
     RECT  71.28 0.659 71.784 1.187 ;
     RECT  72.816 0.611 91.608 1.187 ;
     RECT  92.592 0.563 96.696 1.187 ;
     RECT  37.968 1.187 40.296 1.235 ;
     RECT  0.24 0.565 0.264 1.237 ;
     RECT  27.792 1.187 31.128 1.283 ;
     RECT  2.16 1.187 3.96 1.763 ;
     RECT  4.944 1.187 6.216 1.763 ;
     RECT  10.032 1.187 10.056 1.763 ;
     RECT  11.568 0.611 18.696 1.763 ;
     RECT  19.68 0.611 21.24 1.763 ;
     RECT  22.752 1.187 26.328 1.763 ;
     RECT  27.792 1.283 27.816 1.763 ;
     RECT  28.848 1.283 31.128 1.763 ;
     RECT  32.112 1.187 36.984 1.763 ;
     RECT  41.28 1.187 41.544 1.763 ;
     RECT  43.056 0.371 44.376 1.763 ;
     RECT  45.36 0.611 45.384 1.763 ;
     RECT  46.368 0.611 51.24 1.763 ;
     RECT  52.464 0.611 52.488 1.763 ;
     RECT  53.472 1.187 54.792 1.763 ;
     RECT  55.776 1.187 57.816 1.763 ;
     RECT  59.088 1.187 62.136 1.763 ;
     RECT  63.12 0.659 70.296 1.763 ;
     RECT  71.52 1.187 71.784 1.763 ;
     RECT  72.816 1.187 80.712 1.763 ;
     RECT  81.696 1.187 91.608 1.763 ;
     RECT  92.88 1.187 95.448 1.763 ;
     RECT  96.672 1.187 96.696 1.763 ;
     RECT  99.744 0.323 100.248 1.763 ;
     RECT  101.76 0.275 101.784 1.763 ;
     RECT  103.296 0.611 103.32 1.763 ;
     RECT  104.304 0.611 104.328 1.763 ;
     RECT  105.312 0.275 106.632 1.763 ;
     RECT  107.856 0.275 107.88 1.763 ;
     RECT  109.152 0.611 110.424 1.763 ;
     RECT  111.696 0.275 111.96 1.763 ;
     RECT  117.024 0.611 120.6 1.763 ;
     RECT  122.352 0.611 122.376 1.763 ;
     RECT  123.36 0.563 124.68 1.763 ;
     RECT  125.664 0.563 125.688 1.763 ;
     RECT  126.912 0.611 127.176 1.763 ;
     RECT  128.208 0.611 129.24 1.763 ;
     RECT  131.232 0.275 134.568 1.763 ;
     RECT  135.792 0.275 136.104 1.763 ;
     RECT  2.4 1.763 3.432 1.811 ;
     RECT  5.472 1.763 5.736 1.811 ;
     RECT  7.8 1.187 9.048 1.811 ;
     RECT  11.808 1.763 11.832 1.811 ;
     RECT  18.144 1.763 18.696 1.811 ;
     RECT  23.232 1.763 24.312 1.811 ;
     RECT  38.736 1.235 40.296 1.811 ;
     RECT  47.136 1.763 47.16 1.811 ;
     RECT  50.688 1.763 51.24 1.811 ;
     RECT  54.48 1.763 54.792 1.811 ;
     RECT  74.592 1.763 74.616 1.811 ;
     RECT  90.576 1.763 90.6 1.811 ;
     RECT  99.744 1.763 100.008 1.811 ;
     RECT  131.472 1.763 132.312 1.811 ;
     RECT  133.776 1.763 133.8 1.811 ;
     RECT  32.4 1.763 32.424 1.859 ;
     RECT  36.432 1.763 36.984 1.859 ;
     RECT  48.384 1.763 48.408 1.859 ;
     RECT  77.376 1.763 79.176 1.859 ;
     RECT  113.184 0.611 113.976 1.859 ;
     RECT  117.792 1.763 117.816 1.859 ;
     RECT  18.6 1.811 18.696 2.137 ;
     RECT  40.2 1.811 40.296 2.137 ;
     RECT  71.76 1.763 71.784 2.137 ;
     RECT  72.816 1.763 72.912 2.137 ;
     RECT  99.744 1.811 99.912 2.137 ;
     RECT  110.4 1.763 110.424 2.137 ;
     RECT  116.016 0.611 116.04 2.137 ;
     RECT  120.576 1.763 120.6 2.137 ;
     RECT  51 1.811 51.24 2.151 ;
     RECT  110.4 2.137 110.52 2.151 ;
     RECT  115.8 2.137 116.04 2.151 ;
     RECT  120.576 2.137 121.32 2.151 ;
     RECT  5.472 1.811 5.496 2.195 ;
     RECT  13.2 1.763 14.616 2.195 ;
     RECT  16.896 1.763 16.92 2.195 ;
     RECT  29.4 1.763 30.36 2.195 ;
     RECT  43.056 1.763 43.08 2.195 ;
     RECT  49.392 1.763 49.416 2.195 ;
     RECT  54.48 1.811 54.504 2.195 ;
     RECT  56.4 1.763 57.336 2.195 ;
     RECT  71.76 2.137 72.912 2.195 ;
     RECT  77.856 1.859 79.176 2.195 ;
     RECT  94.2 1.763 95.448 2.195 ;
     RECT  109.392 1.763 109.416 2.195 ;
     RECT  111.696 1.763 111.72 2.195 ;
     RECT  113.184 1.859 113.208 2.195 ;
     RECT  119.04 1.763 119.064 2.195 ;
     RECT  120.576 2.151 121.512 2.195 ;
     RECT  19.92 1.763 19.944 2.291 ;
     RECT  34.176 1.763 35.112 2.291 ;
     RECT  38.736 1.811 38.76 2.291 ;
     RECT  77.856 2.195 78.648 2.291 ;
     RECT  88.8 1.763 89.112 2.821 ;
     RECT  136.08 1.763 136.104 2.915 ;
     RECT  0.24 1.237 0.36 2.963 ;
     RECT  4.368 2.821 4.392 3.155 ;
     RECT  7.8 1.811 8.112 3.157 ;
     RECT  132 1.811 132.312 3.157 ;
     RECT  94.2 2.195 94.512 3.349 ;
     RECT  120.096 3.301 120.12 3.397 ;
     RECT  88.8 2.821 89.4 3.443 ;
     RECT  28.32 3.301 28.344 3.637 ;
     RECT  29.4 2.195 29.712 3.637 ;
     RECT  48.432 3.397 48.456 3.685 ;
     RECT  9.84 3.013 9.864 3.827 ;
     RECT  78 2.291 78.312 3.829 ;
     RECT  38.784 3.397 38.808 3.875 ;
     RECT  109.056 2.821 109.08 3.923 ;
     RECT  24 1.811 24.312 3.925 ;
     RECT  47.904 3.685 48.456 3.925 ;
     RECT  67.2 1.763 67.512 3.925 ;
     RECT  126.6 2.137 126.912 3.925 ;
     RECT  78 3.829 78.648 4.019 ;
     RECT  36.576 3.397 36.6 4.115 ;
     RECT  45.6 2.137 45.912 4.117 ;
     RECT  131.184 3.157 132.312 4.117 ;
     RECT  56.4 2.195 56.808 4.163 ;
     RECT  60.384 2.821 60.408 4.163 ;
     RECT  69.456 1.763 69.48 4.163 ;
     RECT  126.6 3.925 127.032 4.163 ;
     RECT  130.608 4.117 132.312 4.163 ;
     RECT  7.8 3.157 8.232 4.259 ;
     RECT  28.32 3.637 29.712 4.261 ;
     RECT  53.088 3.349 53.112 4.307 ;
     RECT  74.016 3.925 74.04 4.403 ;
     RECT  93.312 3.349 94.512 4.403 ;
     RECT  133.632 2.821 133.656 4.403 ;
     RECT  66.816 3.925 67.512 4.451 ;
     RECT  107.184 3.973 107.208 4.451 ;
     RECT  47.904 3.925 49.224 4.547 ;
     RECT  34.8 2.291 35.112 4.645 ;
     RECT  23.328 3.925 24.312 4.691 ;
     RECT  130.608 4.163 130.632 4.691 ;
     RECT  20.88 2.821 20.904 4.931 ;
     RECT  83.4 1.763 83.712 4.933 ;
     RECT  125.184 3.685 125.208 4.979 ;
     RECT  58.848 5.029 58.872 5.077 ;
     RECT  119.712 3.397 120.12 5.077 ;
     RECT  15.36 4.117 15.384 5.171 ;
     RECT  45.6 4.117 46.248 5.171 ;
     RECT  48.768 4.547 49.224 5.171 ;
     RECT  24 4.691 24.312 5.173 ;
     RECT  28.32 4.261 29.88 5.173 ;
     RECT  40.2 2.137 40.512 5.173 ;
     RECT  99.6 2.137 99.912 5.173 ;
     RECT  61.8 1.763 62.112 5.221 ;
     RECT  64.8 4.789 64.824 5.317 ;
     RECT  110.4 2.151 110.712 5.317 ;
     RECT  115.8 2.151 116.112 5.317 ;
     RECT  18.6 2.137 18.912 5.365 ;
     RECT  16.56 4.693 16.584 5.459 ;
     RECT  28.176 5.173 29.88 5.459 ;
     RECT  13.2 2.195 13.992 5.461 ;
     RECT  72.6 2.195 72.912 5.557 ;
     RECT  123.696 5.029 123.72 5.651 ;
     RECT  121.2 2.195 121.512 5.653 ;
     RECT  78 4.019 78.312 5.701 ;
     RECT  119.664 5.077 120.12 5.701 ;
     RECT  121.2 5.653 121.656 5.701 ;
     RECT  58.848 5.077 58.968 5.747 ;
     RECT  61.8 5.221 62.76 5.747 ;
     RECT  83.28 4.933 83.712 5.747 ;
     RECT  51 2.151 51.312 5.797 ;
     RECT  91.488 5.365 91.512 5.893 ;
     RECT  12.336 5.461 13.992 5.987 ;
     RECT  6.144 3.397 6.168 6.035 ;
     RECT  18.6 5.365 19.128 6.035 ;
     RECT  28.176 5.459 28.2 6.035 ;
     RECT  49.2 5.171 49.224 6.035 ;
     RECT  58.944 5.747 58.968 6.035 ;
     RECT  101.616 5.029 101.64 6.035 ;
     RECT  119.664 5.701 121.656 6.035 ;
     RECT  34.128 4.645 35.112 6.085 ;
     RECT  96.24 5.365 96.264 6.085 ;
     RECT  45.6 5.171 45.912 6.181 ;
     RECT  91.488 5.893 92.472 6.181 ;
     RECT  56.4 4.163 56.712 6.229 ;
     RECT  67.2 4.451 67.512 6.229 ;
     RECT  86.976 4.261 87 6.275 ;
     RECT  29.4 5.459 29.88 6.277 ;
     RECT  121.2 6.035 121.656 6.277 ;
     RECT  22.176 5.317 22.2 6.323 ;
     RECT  24 5.173 24.888 6.323 ;
     RECT  63.84 5.317 64.824 6.323 ;
     RECT  77.472 5.701 78.312 6.323 ;
     RECT  12.72 5.987 13.992 6.373 ;
     RECT  0.24 2.963 0.264 6.419 ;
     RECT  110.4 5.317 111.144 6.467 ;
     RECT  119.664 6.035 119.688 6.515 ;
     RECT  63.84 6.323 64.344 6.563 ;
     RECT  72.48 5.557 72.912 6.563 ;
     RECT  99.6 5.173 100.584 6.563 ;
     RECT  10.848 6.373 10.872 6.659 ;
     RECT  12.72 6.373 14.376 6.659 ;
     RECT  25.44 6.373 25.464 6.659 ;
     RECT  24 6.323 24.408 6.661 ;
     RECT  44.736 6.181 45.912 6.661 ;
     RECT  56.16 6.229 56.712 6.661 ;
     RECT  90.624 6.181 92.472 6.707 ;
     RECT  96.24 6.085 96.456 6.707 ;
     RECT  98.592 5.701 98.616 6.709 ;
     RECT  2.4 1.811 2.712 6.805 ;
     RECT  114.96 5.317 116.112 6.805 ;
     RECT  29.4 6.277 30.12 6.851 ;
     RECT  50.688 5.797 51.312 6.947 ;
     RECT  61.8 5.747 62.568 7.043 ;
     RECT  54.144 5.989 54.168 7.045 ;
     RECT  114.96 6.805 116.568 7.045 ;
     RECT  47.376 5.653 47.4 7.091 ;
     RECT  55.824 6.661 56.712 7.091 ;
     RECT  67.2 6.229 68.424 7.091 ;
     RECT  75.744 6.229 75.768 7.091 ;
     RECT  114.96 7.045 117 7.141 ;
     RECT  40.2 5.173 41.016 7.189 ;
     RECT  96.288 6.707 96.456 7.189 ;
     RECT  97.632 6.709 98.616 7.189 ;
     RECT  40.2 7.189 41.112 7.331 ;
     RECT  16.944 6.805 16.968 7.379 ;
     RECT  33.984 6.085 35.112 7.379 ;
     RECT  114.672 7.141 117 7.379 ;
     RECT  94.2 4.403 94.512 7.381 ;
     RECT  105 2.137 105.312 7.381 ;
     RECT  71.328 7.045 71.352 7.427 ;
     RECT  85.008 5.077 85.032 7.427 ;
     RECT  32.88 7.333 32.904 7.429 ;
     RECT  23.376 6.661 24.408 7.475 ;
     RECT  64.32 6.563 64.344 7.475 ;
     RECT  121.2 6.277 122.28 7.475 ;
     RECT  27.312 6.805 27.336 7.619 ;
     RECT  96.288 7.189 98.616 7.619 ;
     RECT  78 6.323 78.312 7.765 ;
     RECT  44.64 6.661 45.912 7.859 ;
     RECT  59.808 6.181 59.832 7.859 ;
     RECT  114.672 7.379 114.696 7.859 ;
     RECT  115.8 7.379 117 7.859 ;
     RECT  2.4 6.805 3.48 7.907 ;
     RECT  56.16 7.091 56.712 7.907 ;
     RECT  24 7.475 24.408 7.909 ;
     RECT  29.4 6.851 29.712 7.909 ;
     RECT  39.024 6.229 39.048 7.909 ;
     RECT  40.2 7.331 40.512 7.909 ;
     RECT  77.328 7.765 78.312 7.909 ;
     RECT  12.72 6.659 13.512 7.955 ;
     RECT  94.2 7.381 94.632 7.955 ;
     RECT  99.6 6.563 100.344 7.955 ;
     RECT  130.992 6.805 131.016 7.955 ;
     RECT  77.088 7.909 78.312 7.957 ;
     RECT  38.4 7.909 39.048 8.003 ;
     RECT  90.624 6.707 90.648 8.003 ;
     RECT  103.536 6.229 103.56 8.147 ;
     RECT  54.144 7.045 54.6 8.195 ;
     RECT  63.12 7.333 63.144 8.195 ;
     RECT  126.6 4.163 126.912 8.293 ;
     RECT  119.808 7.381 119.832 8.387 ;
     RECT  42.096 7.429 42.12 8.435 ;
     RECT  110.4 6.467 110.856 8.437 ;
     RECT  36.816 7.909 36.84 8.531 ;
     RECT  77.088 7.957 78.888 8.531 ;
     RECT  18.6 6.035 18.912 8.533 ;
     RECT  97.2 7.619 97.656 8.629 ;
     RECT  32.4 7.429 32.904 8.675 ;
     RECT  96.912 8.629 97.656 8.675 ;
     RECT  111.888 7.429 111.912 8.675 ;
     RECT  6.576 6.181 6.6 8.723 ;
     RECT  10.272 7.957 10.296 8.723 ;
     RECT  38.4 8.003 38.424 8.723 ;
     RECT  70.032 8.197 70.056 8.723 ;
     RECT  24 7.909 25.08 8.965 ;
     RECT  45.6 7.859 45.912 8.965 ;
     RECT  40.08 7.909 40.512 9.011 ;
     RECT  105 7.381 106.104 9.011 ;
     RECT  7.8 4.259 8.112 9.061 ;
     RECT  9.264 5.989 9.288 9.061 ;
     RECT  13.2 7.955 13.512 9.061 ;
     RECT  34.8 7.379 35.112 9.061 ;
     RECT  56.4 7.907 56.712 9.061 ;
     RECT  90.432 8.437 90.456 9.107 ;
     RECT  65.568 7.909 65.592 9.155 ;
     RECT  87.792 8.437 87.816 9.155 ;
     RECT  24 8.965 25.416 9.203 ;
     RECT  110.304 8.437 110.856 9.299 ;
     RECT  105 9.011 105.312 9.349 ;
     RECT  132 4.163 132.312 9.397 ;
     RECT  25.392 9.203 25.416 9.491 ;
     RECT  121.2 7.475 121.512 9.493 ;
     RECT  18.6 8.533 19.656 9.539 ;
     RECT  126.6 8.293 127.368 9.587 ;
     RECT  96.912 8.675 97.032 9.637 ;
     RECT  52.752 9.061 52.776 9.683 ;
     RECT  118.608 8.341 118.632 9.731 ;
     RECT  55.152 9.253 55.176 9.779 ;
     RECT  13.2 9.061 14.424 9.781 ;
     RECT  29.4 7.909 29.976 9.781 ;
     RECT  12.864 9.781 14.424 9.827 ;
     RECT  110.4 9.299 110.856 9.827 ;
     RECT  67.2 7.091 67.512 9.925 ;
     RECT  72.6 6.563 72.912 9.925 ;
     RECT  32.88 8.675 32.904 10.019 ;
     RECT  31.392 9.637 31.416 10.117 ;
     RECT  45.216 8.965 45.912 10.165 ;
     RECT  54.144 8.195 54.168 10.165 ;
     RECT  59.808 9.061 59.832 10.165 ;
     RECT  67.2 9.925 68.088 10.165 ;
     RECT  77.088 8.531 78.312 10.165 ;
     RECT  88.8 3.443 89.112 10.165 ;
     RECT  99.6 7.955 99.912 10.165 ;
     RECT  24 9.203 24.408 10.213 ;
     RECT  29.4 9.781 30.264 10.213 ;
     RECT  43.728 10.165 43.752 10.213 ;
     RECT  48.528 9.925 48.552 10.213 ;
     RECT  56.4 9.061 56.808 10.213 ;
     RECT  58.032 9.781 58.056 10.213 ;
     RECT  64.224 9.253 64.248 10.213 ;
     RECT  66.816 10.165 68.088 10.213 ;
     RECT  88.128 10.165 89.976 10.213 ;
     RECT  96.576 9.637 97.032 10.213 ;
     RECT  99.408 10.165 99.912 10.213 ;
     RECT  103.44 10.165 103.464 10.213 ;
     RECT  104.784 9.349 105.312 10.213 ;
     RECT  109.392 9.637 109.416 10.213 ;
     RECT  115.8 7.859 116.112 10.213 ;
     RECT  117.936 10.165 117.96 10.213 ;
     RECT  4.512 9.685 4.536 10.259 ;
     RECT  15.36 10.213 15.384 10.261 ;
     RECT  7.8 9.061 9.288 10.307 ;
     RECT  80.928 9.781 80.952 10.307 ;
     RECT  96.576 10.213 97.08 10.307 ;
     RECT  27.84 10.165 27.864 10.453 ;
     RECT  34.8 9.061 35.4 10.453 ;
     RECT  40.2 9.011 40.512 10.453 ;
     RECT  51 6.947 51.312 10.453 ;
     RECT  63.552 10.213 64.248 10.453 ;
     RECT  74.64 9.781 74.664 10.453 ;
     RECT  76.128 10.165 78.408 10.453 ;
     RECT  109.248 10.213 109.416 10.453 ;
     RECT  112.08 10.165 112.104 10.453 ;
     RECT  114.096 10.357 114.12 10.453 ;
     RECT  115.8 10.213 117.96 10.453 ;
     RECT  59.808 10.165 60.504 10.595 ;
     RECT  43.728 10.213 44.088 10.643 ;
     RECT  12.864 9.827 14.04 10.741 ;
     RECT  15.36 10.261 15.96 10.741 ;
     RECT  23.424 10.213 24.408 10.741 ;
     RECT  28.896 10.213 30.264 10.741 ;
     RECT  34.8 10.453 36.744 10.741 ;
     RECT  88.128 10.213 90.888 10.741 ;
     RECT  94.2 7.955 94.512 10.741 ;
     RECT  99.408 10.213 100.296 10.741 ;
     RECT  103.44 10.213 105.312 10.741 ;
     RECT  114.096 10.453 117.96 10.741 ;
     RECT  119.088 10.165 119.112 10.741 ;
     RECT  126.6 9.587 127.032 10.741 ;
     RECT  9.984 10.453 10.248 10.789 ;
     RECT  12.192 10.741 14.04 10.789 ;
     RECT  15.36 10.741 16.872 10.789 ;
     RECT  18.6 9.539 19.56 10.789 ;
     RECT  40.08 10.453 40.512 10.789 ;
     RECT  45.216 10.165 46.008 10.789 ;
     RECT  48.096 10.213 48.984 10.789 ;
     RECT  54.144 10.165 54.36 10.789 ;
     RECT  60.48 10.595 60.504 10.789 ;
     RECT  61.8 7.043 62.112 10.789 ;
     RECT  63.504 10.453 64.248 10.789 ;
     RECT  69.504 10.741 69.528 10.789 ;
     RECT  72.6 9.925 73.032 10.789 ;
     RECT  81.408 10.741 81.768 10.789 ;
     RECT  83.4 5.747 83.712 10.789 ;
     RECT  86.016 10.213 86.04 10.789 ;
     RECT  87.696 10.741 90.888 10.789 ;
     RECT  94.2 10.741 95.352 10.789 ;
     RECT  99.408 10.741 101.112 10.789 ;
     RECT  103.44 10.741 105.72 10.789 ;
     RECT  110.4 9.827 110.712 10.789 ;
     RECT  111.744 10.453 112.104 10.789 ;
     RECT  113.952 10.741 119.112 10.789 ;
     RECT  126.6 10.741 127.464 10.789 ;
     RECT  133.632 10.213 133.656 10.789 ;
     RECT  134.928 10.213 134.952 10.789 ;
     RECT  23.424 10.741 25.08 10.835 ;
     RECT  74.256 10.453 74.664 10.835 ;
     RECT  11.616 10.789 19.56 10.837 ;
     RECT  34.56 10.741 36.744 10.837 ;
     RECT  53.28 10.789 54.36 10.837 ;
     RECT  103.104 10.789 105.72 10.837 ;
     RECT  11.616 10.837 19.704 10.883 ;
     RECT  26.88 10.453 27.864 10.883 ;
     RECT  34.56 10.837 36.984 10.883 ;
     RECT  43.728 10.643 43.848 10.883 ;
     RECT  45.216 10.789 49.32 10.883 ;
     RECT  53.28 10.837 54.504 10.883 ;
     RECT  56.4 10.213 58.056 10.883 ;
     RECT  60.48 10.789 62.112 10.883 ;
     RECT  63.504 10.789 64.872 10.883 ;
     RECT  66.816 10.213 68.328 10.883 ;
     RECT  120.432 9.493 121.512 10.883 ;
     RECT  131.088 9.397 132.312 10.883 ;
     RECT  45.312 10.883 49.32 10.885 ;
     RECT  53.28 10.883 53.496 10.931 ;
     RECT  63.552 10.883 64.872 10.931 ;
     RECT  71.328 10.789 73.032 10.931 ;
     RECT  16.848 10.883 19.704 10.979 ;
     RECT  113.136 10.789 119.112 10.981 ;
     RECT  125.664 10.789 127.464 10.981 ;
     RECT  63.552 10.931 63.672 11.171 ;
     RECT  133.632 10.789 134.952 11.269 ;
     RECT  103.104 10.837 105.864 11.365 ;
     RECT  106.992 10.789 107.736 11.365 ;
     RECT  7.8 10.307 8.856 11.941 ;
     RECT  11.616 10.883 15.624 11.941 ;
     RECT  16.848 10.979 16.872 11.941 ;
     RECT  92.304 10.789 92.328 11.941 ;
     RECT  93.6 10.789 95.352 11.941 ;
     RECT  96.816 10.307 97.08 11.941 ;
     RECT  99.408 10.789 101.976 11.941 ;
     RECT  6.096 10.789 6.12 12.277 ;
     RECT  5.952 12.277 6.12 12.325 ;
     RECT  7.488 11.941 8.856 12.325 ;
     RECT  9.984 10.789 10.632 12.325 ;
     RECT  71.52 10.931 73.032 12.325 ;
     RECT  76.128 10.453 79.704 12.325 ;
     RECT  133.344 11.269 135.528 12.325 ;
     RECT  2.4 7.907 2.712 12.517 ;
     RECT  5.184 12.325 6.12 12.517 ;
     RECT  17.904 10.979 19.704 12.517 ;
     RECT  23.472 10.835 25.08 12.517 ;
     RECT  27.072 10.883 27.864 12.517 ;
     RECT  28.896 10.741 30.36 12.517 ;
     RECT  31.392 10.117 32.184 12.517 ;
     RECT  33.456 10.741 33.48 12.517 ;
     RECT  34.656 10.883 35.112 12.517 ;
     RECT  36.192 10.883 36.984 12.517 ;
     RECT  38.256 12.325 38.28 12.517 ;
     RECT  39.984 10.789 40.512 12.517 ;
     RECT  43.824 10.883 43.848 12.517 ;
     RECT  45.312 10.885 49.416 12.517 ;
     RECT  50.4 10.453 51.312 12.517 ;
     RECT  53.472 10.931 53.496 12.517 ;
     RECT  54.48 10.883 54.504 12.517 ;
     RECT  56.4 10.883 57.336 12.517 ;
     RECT  60.576 10.883 62.112 12.517 ;
     RECT  63.648 11.171 63.672 12.517 ;
     RECT  64.848 10.931 64.872 12.517 ;
     RECT  66.96 10.883 68.328 12.517 ;
     RECT  69.504 10.789 70.296 12.517 ;
     RECT  76.128 12.325 79.944 12.517 ;
     RECT  81.408 10.789 83.712 12.517 ;
     RECT  84.72 12.325 84.744 12.517 ;
     RECT  86.016 10.789 90.888 12.517 ;
     RECT  93.6 11.941 97.08 12.517 ;
     RECT  99.408 11.941 102.024 12.517 ;
     RECT  103.104 11.365 107.736 12.517 ;
     RECT  109.056 10.453 109.416 12.517 ;
     RECT  110.4 10.789 112.104 12.517 ;
     RECT  113.136 10.981 119.592 12.517 ;
     RECT  120.576 10.883 121.512 12.517 ;
     RECT  124.656 11.269 124.68 12.517 ;
     RECT  125.664 10.981 128.184 12.517 ;
     RECT  131.472 10.883 132.312 12.517 ;
     RECT  133.344 12.325 135.576 12.517 ;
     RECT  52.704 12.517 54.792 12.613 ;
     RECT  55.776 12.517 57.816 12.613 ;
     RECT  2.4 12.517 3.96 12.757 ;
     RECT  2.16 12.757 3.96 12.901 ;
     RECT  5.184 12.517 6.504 12.901 ;
     RECT  7.488 12.325 10.632 12.901 ;
     RECT  11.616 11.941 16.872 12.901 ;
     RECT  17.904 12.517 19.944 12.901 ;
     RECT  20.976 12.517 25.08 12.901 ;
     RECT  27.072 12.517 30.36 12.901 ;
     RECT  31.392 12.517 35.208 12.901 ;
     RECT  36.192 12.517 38.28 12.901 ;
     RECT  39.264 12.517 41.832 12.901 ;
     RECT  43.056 12.517 49.416 12.901 ;
     RECT  50.4 12.517 51.72 12.901 ;
     RECT  52.704 12.613 57.816 12.901 ;
     RECT  59.088 12.517 59.112 12.901 ;
     RECT  60.336 12.517 70.536 12.901 ;
     RECT  71.52 12.325 73.08 12.901 ;
     RECT  74.256 10.835 74.28 12.901 ;
     RECT  75.84 12.517 79.944 12.901 ;
     RECT  81.408 12.517 90.888 12.901 ;
     RECT  92.112 11.941 92.328 12.901 ;
     RECT  93.6 12.517 109.416 12.901 ;
     RECT  110.4 12.517 119.592 12.901 ;
     RECT  120.576 12.517 122.376 12.901 ;
     RECT  123.6 12.517 136.104 12.901 ;
     RECT  2.16 12.901 136.104 14.992 ;
     RECT  11.616 14.992 11.64 15.011 ;
     RECT  25.056 14.992 25.08 15.011 ;
     RECT  28.896 14.992 28.92 15.011 ;
     RECT  36.672 14.992 36.696 15.011 ;
     RECT  39.984 14.992 40.008 15.011 ;
     RECT  46.944 14.992 48.12 15.011 ;
     RECT  61.296 14.992 61.32 15.011 ;
     RECT  64.848 14.992 64.872 15.011 ;
     RECT  69.696 14.992 69.72 15.011 ;
     RECT  74.256 14.992 74.28 15.011 ;
     RECT  76.56 14.992 77.352 15.011 ;
     RECT  113.136 14.992 113.16 15.011 ;
  END
END ot_s81_hc_pad_meta2
END LIBRARY
